VERSION 5.8 ;
BUSBITCHARS "[]" ;
DIVIDERCHAR "/" ;

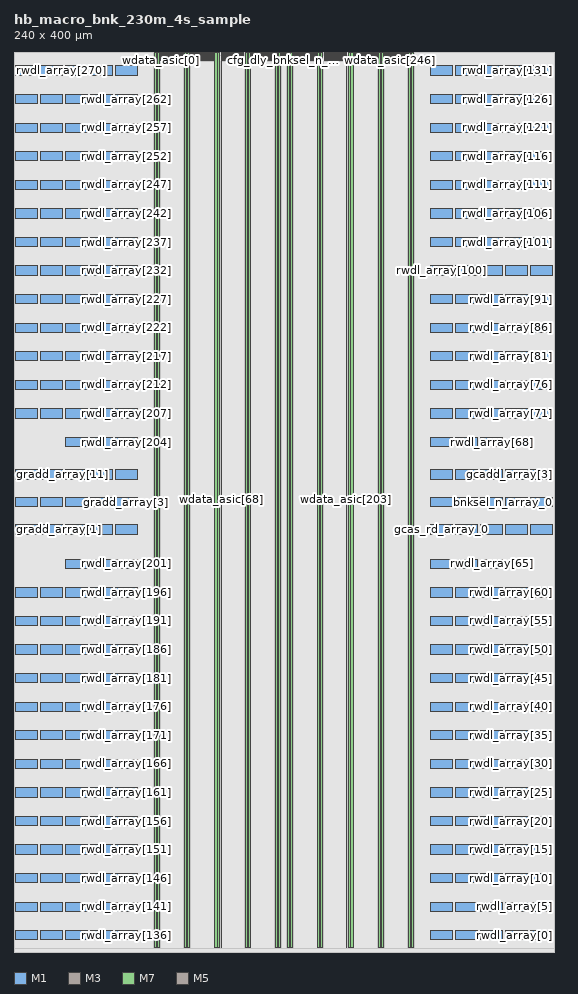
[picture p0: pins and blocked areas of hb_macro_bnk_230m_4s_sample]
MACRO hb_macro_bnk_230m_4s_sample
  CLASS RING ;
  ORIGIN 0 0 ;
  FOREIGN hb_macro_bnk_230m_4s_sample 0 0 ;
  SIZE 240 BY 400 ;
  SYMMETRY X Y R90 ;
  PIN bnksel_n_array_0
    DIRECTION OUTPUT ;
    USE SIGNAL ;
    PORT
      LAYER M1 ;
        RECT 218.53 197.94 228.21 202.06 ;
    END
  END bnksel_n_array_0
  PIN bnksel_n_array_1
    DIRECTION OUTPUT ;
    USE SIGNAL ;
    PORT
      LAYER M1 ;
        RECT 229.65 197.94 239.33 202.06 ;
    END
  END bnksel_n_array_1
  PIN gcadd_array[0]
    DIRECTION OUTPUT ;
    USE SIGNAL ;
    PORT
      LAYER M1 ;
        RECT 207.41 197.94 217.09 202.06 ;
    END
  END gcadd_array[0]
  PIN gcadd_array[1]
    DIRECTION OUTPUT ;
    USE SIGNAL ;
    PORT
      LAYER M1 ;
        RECT 196.29 197.94 205.97 202.06 ;
    END
  END gcadd_array[1]
  PIN gcadd_array[2]
    DIRECTION OUTPUT ;
    USE SIGNAL ;
    PORT
      LAYER M1 ;
        RECT 185.17 197.94 194.85 202.06 ;
    END
  END gcadd_array[2]
  PIN gcadd_array[3]
    DIRECTION OUTPUT ;
    USE SIGNAL ;
    PORT
      LAYER M1 ;
        RECT 229.65 210.22 239.33 214.34 ;
    END
  END gcadd_array[3]
  PIN gcadd_array[4]
    DIRECTION OUTPUT ;
    USE SIGNAL ;
    PORT
      LAYER M1 ;
        RECT 218.53 210.22 228.21 214.34 ;
    END
  END gcadd_array[4]
  PIN gcadd_array[5]
    DIRECTION OUTPUT ;
    USE SIGNAL ;
    PORT
      LAYER M1 ;
        RECT 207.41 210.22 217.09 214.34 ;
    END
  END gcadd_array[5]
  PIN gcadd_array[6]
    DIRECTION OUTPUT ;
    USE SIGNAL ;
    PORT
      LAYER M1 ;
        RECT 196.29 210.22 205.97 214.34 ;
    END
  END gcadd_array[6]
  PIN gcadd_array[7]
    DIRECTION OUTPUT ;
    USE SIGNAL ;
    PORT
      LAYER M1 ;
        RECT 185.17 210.22 194.85 214.34 ;
    END
  END gcadd_array[7]
  PIN gcas_rd_array_0
    DIRECTION OUTPUT ;
    USE SIGNAL ;
    PORT
      LAYER M1 ;
        RECT 185.17 185.66 194.85 189.78 ;
    END
  END gcas_rd_array_0
  PIN gcas_rd_array_1
    DIRECTION OUTPUT ;
    USE SIGNAL ;
    PORT
      LAYER M1 ;
        RECT 196.29 185.66 205.97 189.78 ;
    END
  END gcas_rd_array_1
  PIN gcas_wr_array_0
    DIRECTION OUTPUT ;
    USE SIGNAL ;
    PORT
      LAYER M1 ;
        RECT 207.41 185.66 217.09 189.78 ;
    END
  END gcas_wr_array_0
  PIN gcas_wr_array_1
    DIRECTION OUTPUT ;
    USE SIGNAL ;
    PORT
      LAYER M1 ;
        RECT 218.53 185.66 228.21 189.78 ;
    END
  END gcas_wr_array_1
  PIN gradd_array[0]
    DIRECTION OUTPUT ;
    USE SIGNAL ;
    PORT
      LAYER M1 ;
        RECT 22.91 185.66 32.59 189.78 ;
    END
  END gradd_array[0]
  PIN gradd_array[10]
    DIRECTION OUTPUT ;
    USE SIGNAL ;
    PORT
      LAYER M1 ;
        RECT 22.91 210.22 32.59 214.34 ;
    END
  END gradd_array[10]
  PIN gradd_array[11]
    DIRECTION OUTPUT ;
    USE SIGNAL ;
    PORT
      LAYER M1 ;
        RECT 11.79 210.22 21.47 214.34 ;
    END
  END gradd_array[11]
  PIN gradd_array[12]
    DIRECTION OUTPUT ;
    USE SIGNAL ;
    PORT
      LAYER M1 ;
        RECT 0.67 210.22 10.35 214.34 ;
    END
  END gradd_array[12]
  PIN gradd_array[1]
    DIRECTION OUTPUT ;
    USE SIGNAL ;
    PORT
      LAYER M1 ;
        RECT 11.79 185.66 21.47 189.78 ;
    END
  END gradd_array[1]
  PIN gradd_array[2]
    DIRECTION OUTPUT ;
    USE SIGNAL ;
    PORT
      LAYER M1 ;
        RECT 0.67 185.66 10.35 189.78 ;
    END
  END gradd_array[2]
  PIN gradd_array[3]
    DIRECTION OUTPUT ;
    USE SIGNAL ;
    PORT
      LAYER M1 ;
        RECT 45.15 197.94 54.83 202.06 ;
    END
  END gradd_array[3]
  PIN gradd_array[4]
    DIRECTION OUTPUT ;
    USE SIGNAL ;
    PORT
      LAYER M1 ;
        RECT 34.03 197.94 43.71 202.06 ;
    END
  END gradd_array[4]
  PIN gradd_array[5]
    DIRECTION OUTPUT ;
    USE SIGNAL ;
    PORT
      LAYER M1 ;
        RECT 22.91 197.94 32.59 202.06 ;
    END
  END gradd_array[5]
  PIN gradd_array[6]
    DIRECTION OUTPUT ;
    USE SIGNAL ;
    PORT
      LAYER M1 ;
        RECT 11.79 197.94 21.47 202.06 ;
    END
  END gradd_array[6]
  PIN gradd_array[7]
    DIRECTION OUTPUT ;
    USE SIGNAL ;
    PORT
      LAYER M1 ;
        RECT 0.67 197.94 10.35 202.06 ;
    END
  END gradd_array[7]
  PIN gradd_array[8]
    DIRECTION OUTPUT ;
    USE SIGNAL ;
    PORT
      LAYER M1 ;
        RECT 45.15 210.22 54.83 214.34 ;
    END
  END gradd_array[8]
  PIN gradd_array[9]
    DIRECTION OUTPUT ;
    USE SIGNAL ;
    PORT
      LAYER M1 ;
        RECT 34.03 210.22 43.71 214.34 ;
    END
  END gradd_array[9]
  PIN rdrdy_n_array_0
    DIRECTION INPUT ;
    USE SIGNAL ;
    PORT
      LAYER M1 ;
        RECT 34.03 185.66 43.71 189.78 ;
    END
  END rdrdy_n_array_0
  PIN rdrdy_n_array_1
    DIRECTION INPUT ;
    USE SIGNAL ;
    PORT
      LAYER M1 ;
        RECT 45.15 185.66 54.83 189.78 ;
    END
  END rdrdy_n_array_1
  PIN reset_n_array
    DIRECTION OUTPUT ;
    USE SIGNAL ;
    PORT
      LAYER M1 ;
        RECT 229.65 185.66 239.33 189.78 ;
    END
  END reset_n_array
  PIN rwdl_array[0]
    DIRECTION INOUT ;
    USE SIGNAL ;
    PORT
      LAYER M1 ;
        RECT 229.65 5.36 239.33 9.48 ;
    END
  END rwdl_array[0]
  PIN rwdl_array[100]
    DIRECTION INOUT ;
    USE SIGNAL ;
    PORT
      LAYER M1 ;
        RECT 185.17 300.785 194.85 304.905 ;
    END
  END rwdl_array[100]
  PIN rwdl_array[101]
    DIRECTION INOUT ;
    USE SIGNAL ;
    PORT
      LAYER M1 ;
        RECT 229.65 313.485 239.33 317.605 ;
    END
  END rwdl_array[101]
  PIN rwdl_array[102]
    DIRECTION INOUT ;
    USE SIGNAL ;
    PORT
      LAYER M1 ;
        RECT 218.53 313.485 228.21 317.605 ;
    END
  END rwdl_array[102]
  PIN rwdl_array[103]
    DIRECTION INOUT ;
    USE SIGNAL ;
    PORT
      LAYER M1 ;
        RECT 207.41 313.485 217.09 317.605 ;
    END
  END rwdl_array[103]
  PIN rwdl_array[104]
    DIRECTION INOUT ;
    USE SIGNAL ;
    PORT
      LAYER M1 ;
        RECT 196.29 313.485 205.97 317.605 ;
    END
  END rwdl_array[104]
  PIN rwdl_array[105]
    DIRECTION INOUT ;
    USE SIGNAL ;
    PORT
      LAYER M1 ;
        RECT 185.17 313.485 194.85 317.605 ;
    END
  END rwdl_array[105]
  PIN rwdl_array[106]
    DIRECTION INOUT ;
    USE SIGNAL ;
    PORT
      LAYER M1 ;
        RECT 229.65 326.185 239.33 330.305 ;
    END
  END rwdl_array[106]
  PIN rwdl_array[107]
    DIRECTION INOUT ;
    USE SIGNAL ;
    PORT
      LAYER M1 ;
        RECT 218.53 326.185 228.21 330.305 ;
    END
  END rwdl_array[107]
  PIN rwdl_array[108]
    DIRECTION INOUT ;
    USE SIGNAL ;
    PORT
      LAYER M1 ;
        RECT 207.41 326.185 217.09 330.305 ;
    END
  END rwdl_array[108]
  PIN rwdl_array[109]
    DIRECTION INOUT ;
    USE SIGNAL ;
    PORT
      LAYER M1 ;
        RECT 196.29 326.185 205.97 330.305 ;
    END
  END rwdl_array[109]
  PIN rwdl_array[10]
    DIRECTION INOUT ;
    USE SIGNAL ;
    PORT
      LAYER M1 ;
        RECT 229.65 30.76 239.33 34.88 ;
    END
  END rwdl_array[10]
  PIN rwdl_array[110]
    DIRECTION INOUT ;
    USE SIGNAL ;
    PORT
      LAYER M1 ;
        RECT 185.17 326.185 194.85 330.305 ;
    END
  END rwdl_array[110]
  PIN rwdl_array[111]
    DIRECTION INOUT ;
    USE SIGNAL ;
    PORT
      LAYER M1 ;
        RECT 229.65 338.885 239.33 343.005 ;
    END
  END rwdl_array[111]
  PIN rwdl_array[112]
    DIRECTION INOUT ;
    USE SIGNAL ;
    PORT
      LAYER M1 ;
        RECT 218.53 338.885 228.21 343.005 ;
    END
  END rwdl_array[112]
  PIN rwdl_array[113]
    DIRECTION INOUT ;
    USE SIGNAL ;
    PORT
      LAYER M1 ;
        RECT 207.41 338.885 217.09 343.005 ;
    END
  END rwdl_array[113]
  PIN rwdl_array[114]
    DIRECTION INOUT ;
    USE SIGNAL ;
    PORT
      LAYER M1 ;
        RECT 196.29 338.885 205.97 343.005 ;
    END
  END rwdl_array[114]
  PIN rwdl_array[115]
    DIRECTION INOUT ;
    USE SIGNAL ;
    PORT
      LAYER M1 ;
        RECT 185.17 338.885 194.85 343.005 ;
    END
  END rwdl_array[115]
  PIN rwdl_array[116]
    DIRECTION INOUT ;
    USE SIGNAL ;
    PORT
      LAYER M1 ;
        RECT 229.65 351.585 239.33 355.705 ;
    END
  END rwdl_array[116]
  PIN rwdl_array[117]
    DIRECTION INOUT ;
    USE SIGNAL ;
    PORT
      LAYER M1 ;
        RECT 218.53 351.585 228.21 355.705 ;
    END
  END rwdl_array[117]
  PIN rwdl_array[118]
    DIRECTION INOUT ;
    USE SIGNAL ;
    PORT
      LAYER M1 ;
        RECT 207.41 351.585 217.09 355.705 ;
    END
  END rwdl_array[118]
  PIN rwdl_array[119]
    DIRECTION INOUT ;
    USE SIGNAL ;
    PORT
      LAYER M1 ;
        RECT 196.29 351.585 205.97 355.705 ;
    END
  END rwdl_array[119]
  PIN rwdl_array[11]
    DIRECTION INOUT ;
    USE SIGNAL ;
    PORT
      LAYER M1 ;
        RECT 218.53 30.76 228.21 34.88 ;
    END
  END rwdl_array[11]
  PIN rwdl_array[120]
    DIRECTION INOUT ;
    USE SIGNAL ;
    PORT
      LAYER M1 ;
        RECT 185.17 351.585 194.85 355.705 ;
    END
  END rwdl_array[120]
  PIN rwdl_array[121]
    DIRECTION INOUT ;
    USE SIGNAL ;
    PORT
      LAYER M1 ;
        RECT 229.65 364.285 239.33 368.405 ;
    END
  END rwdl_array[121]
  PIN rwdl_array[122]
    DIRECTION INOUT ;
    USE SIGNAL ;
    PORT
      LAYER M1 ;
        RECT 218.53 364.285 228.21 368.405 ;
    END
  END rwdl_array[122]
  PIN rwdl_array[123]
    DIRECTION INOUT ;
    USE SIGNAL ;
    PORT
      LAYER M1 ;
        RECT 207.41 364.285 217.09 368.405 ;
    END
  END rwdl_array[123]
  PIN rwdl_array[124]
    DIRECTION INOUT ;
    USE SIGNAL ;
    PORT
      LAYER M1 ;
        RECT 196.29 364.285 205.97 368.405 ;
    END
  END rwdl_array[124]
  PIN rwdl_array[125]
    DIRECTION INOUT ;
    USE SIGNAL ;
    PORT
      LAYER M1 ;
        RECT 185.17 364.285 194.85 368.405 ;
    END
  END rwdl_array[125]
  PIN rwdl_array[126]
    DIRECTION INOUT ;
    USE SIGNAL ;
    PORT
      LAYER M1 ;
        RECT 229.65 376.985 239.33 381.105 ;
    END
  END rwdl_array[126]
  PIN rwdl_array[127]
    DIRECTION INOUT ;
    USE SIGNAL ;
    PORT
      LAYER M1 ;
        RECT 218.53 376.985 228.21 381.105 ;
    END
  END rwdl_array[127]
  PIN rwdl_array[128]
    DIRECTION INOUT ;
    USE SIGNAL ;
    PORT
      LAYER M1 ;
        RECT 207.41 376.985 217.09 381.105 ;
    END
  END rwdl_array[128]
  PIN rwdl_array[129]
    DIRECTION INOUT ;
    USE SIGNAL ;
    PORT
      LAYER M1 ;
        RECT 196.29 376.985 205.97 381.105 ;
    END
  END rwdl_array[129]
  PIN rwdl_array[12]
    DIRECTION INOUT ;
    USE SIGNAL ;
    PORT
      LAYER M1 ;
        RECT 207.41 30.76 217.09 34.88 ;
    END
  END rwdl_array[12]
  PIN rwdl_array[130]
    DIRECTION INOUT ;
    USE SIGNAL ;
    PORT
      LAYER M1 ;
        RECT 185.17 376.985 194.85 381.105 ;
    END
  END rwdl_array[130]
  PIN rwdl_array[131]
    DIRECTION INOUT ;
    USE SIGNAL ;
    PORT
      LAYER M1 ;
        RECT 229.65 389.685 239.33 393.805 ;
    END
  END rwdl_array[131]
  PIN rwdl_array[132]
    DIRECTION INOUT ;
    USE SIGNAL ;
    PORT
      LAYER M1 ;
        RECT 218.53 389.685 228.21 393.805 ;
    END
  END rwdl_array[132]
  PIN rwdl_array[133]
    DIRECTION INOUT ;
    USE SIGNAL ;
    PORT
      LAYER M1 ;
        RECT 207.41 389.685 217.09 393.805 ;
    END
  END rwdl_array[133]
  PIN rwdl_array[134]
    DIRECTION INOUT ;
    USE SIGNAL ;
    PORT
      LAYER M1 ;
        RECT 196.29 389.685 205.97 393.805 ;
    END
  END rwdl_array[134]
  PIN rwdl_array[135]
    DIRECTION INOUT ;
    USE SIGNAL ;
    PORT
      LAYER M1 ;
        RECT 185.17 389.685 194.85 393.805 ;
    END
  END rwdl_array[135]
  PIN rwdl_array[136]
    DIRECTION INOUT ;
    USE SIGNAL ;
    PORT
      LAYER M1 ;
        RECT 45.15 5.36 54.83 9.48 ;
    END
  END rwdl_array[136]
  PIN rwdl_array[137]
    DIRECTION INOUT ;
    USE SIGNAL ;
    PORT
      LAYER M1 ;
        RECT 34.03 5.36 43.71 9.48 ;
    END
  END rwdl_array[137]
  PIN rwdl_array[138]
    DIRECTION INOUT ;
    USE SIGNAL ;
    PORT
      LAYER M1 ;
        RECT 22.91 5.36 32.59 9.48 ;
    END
  END rwdl_array[138]
  PIN rwdl_array[139]
    DIRECTION INOUT ;
    USE SIGNAL ;
    PORT
      LAYER M1 ;
        RECT 11.79 5.36 21.47 9.48 ;
    END
  END rwdl_array[139]
  PIN rwdl_array[13]
    DIRECTION INOUT ;
    USE SIGNAL ;
    PORT
      LAYER M1 ;
        RECT 196.29 30.76 205.97 34.88 ;
    END
  END rwdl_array[13]
  PIN rwdl_array[140]
    DIRECTION INOUT ;
    USE SIGNAL ;
    PORT
      LAYER M1 ;
        RECT 0.67 5.36 10.35 9.48 ;
    END
  END rwdl_array[140]
  PIN rwdl_array[141]
    DIRECTION INOUT ;
    USE SIGNAL ;
    PORT
      LAYER M1 ;
        RECT 45.15 18.06 54.83 22.18 ;
    END
  END rwdl_array[141]
  PIN rwdl_array[142]
    DIRECTION INOUT ;
    USE SIGNAL ;
    PORT
      LAYER M1 ;
        RECT 34.03 18.06 43.71 22.18 ;
    END
  END rwdl_array[142]
  PIN rwdl_array[143]
    DIRECTION INOUT ;
    USE SIGNAL ;
    PORT
      LAYER M1 ;
        RECT 22.91 18.06 32.59 22.18 ;
    END
  END rwdl_array[143]
  PIN rwdl_array[144]
    DIRECTION INOUT ;
    USE SIGNAL ;
    PORT
      LAYER M1 ;
        RECT 11.79 18.06 21.47 22.18 ;
    END
  END rwdl_array[144]
  PIN rwdl_array[145]
    DIRECTION INOUT ;
    USE SIGNAL ;
    PORT
      LAYER M1 ;
        RECT 0.67 18.06 10.35 22.18 ;
    END
  END rwdl_array[145]
  PIN rwdl_array[146]
    DIRECTION INOUT ;
    USE SIGNAL ;
    PORT
      LAYER M1 ;
        RECT 45.15 30.76 54.83 34.88 ;
    END
  END rwdl_array[146]
  PIN rwdl_array[147]
    DIRECTION INOUT ;
    USE SIGNAL ;
    PORT
      LAYER M1 ;
        RECT 34.03 30.76 43.71 34.88 ;
    END
  END rwdl_array[147]
  PIN rwdl_array[148]
    DIRECTION INOUT ;
    USE SIGNAL ;
    PORT
      LAYER M1 ;
        RECT 22.91 30.76 32.59 34.88 ;
    END
  END rwdl_array[148]
  PIN rwdl_array[149]
    DIRECTION INOUT ;
    USE SIGNAL ;
    PORT
      LAYER M1 ;
        RECT 11.79 30.76 21.47 34.88 ;
    END
  END rwdl_array[149]
  PIN rwdl_array[14]
    DIRECTION INOUT ;
    USE SIGNAL ;
    PORT
      LAYER M1 ;
        RECT 185.17 30.76 194.85 34.88 ;
    END
  END rwdl_array[14]
  PIN rwdl_array[150]
    DIRECTION INOUT ;
    USE SIGNAL ;
    PORT
      LAYER M1 ;
        RECT 0.67 30.76 10.35 34.88 ;
    END
  END rwdl_array[150]
  PIN rwdl_array[151]
    DIRECTION INOUT ;
    USE SIGNAL ;
    PORT
      LAYER M1 ;
        RECT 45.15 43.46 54.83 47.58 ;
    END
  END rwdl_array[151]
  PIN rwdl_array[152]
    DIRECTION INOUT ;
    USE SIGNAL ;
    PORT
      LAYER M1 ;
        RECT 34.03 43.46 43.71 47.58 ;
    END
  END rwdl_array[152]
  PIN rwdl_array[153]
    DIRECTION INOUT ;
    USE SIGNAL ;
    PORT
      LAYER M1 ;
        RECT 22.91 43.46 32.59 47.58 ;
    END
  END rwdl_array[153]
  PIN rwdl_array[154]
    DIRECTION INOUT ;
    USE SIGNAL ;
    PORT
      LAYER M1 ;
        RECT 11.79 43.46 21.47 47.58 ;
    END
  END rwdl_array[154]
  PIN rwdl_array[155]
    DIRECTION INOUT ;
    USE SIGNAL ;
    PORT
      LAYER M1 ;
        RECT 0.67 43.46 10.35 47.58 ;
    END
  END rwdl_array[155]
  PIN rwdl_array[156]
    DIRECTION INOUT ;
    USE SIGNAL ;
    PORT
      LAYER M1 ;
        RECT 45.15 56.16 54.83 60.28 ;
    END
  END rwdl_array[156]
  PIN rwdl_array[157]
    DIRECTION INOUT ;
    USE SIGNAL ;
    PORT
      LAYER M1 ;
        RECT 34.03 56.16 43.71 60.28 ;
    END
  END rwdl_array[157]
  PIN rwdl_array[158]
    DIRECTION INOUT ;
    USE SIGNAL ;
    PORT
      LAYER M1 ;
        RECT 22.91 56.16 32.59 60.28 ;
    END
  END rwdl_array[158]
  PIN rwdl_array[159]
    DIRECTION INOUT ;
    USE SIGNAL ;
    PORT
      LAYER M1 ;
        RECT 11.79 56.16 21.47 60.28 ;
    END
  END rwdl_array[159]
  PIN rwdl_array[15]
    DIRECTION INOUT ;
    USE SIGNAL ;
    PORT
      LAYER M1 ;
        RECT 229.65 43.46 239.33 47.58 ;
    END
  END rwdl_array[15]
  PIN rwdl_array[160]
    DIRECTION INOUT ;
    USE SIGNAL ;
    PORT
      LAYER M1 ;
        RECT 0.67 56.16 10.35 60.28 ;
    END
  END rwdl_array[160]
  PIN rwdl_array[161]
    DIRECTION INOUT ;
    USE SIGNAL ;
    PORT
      LAYER M1 ;
        RECT 45.15 68.86 54.83 72.98 ;
    END
  END rwdl_array[161]
  PIN rwdl_array[162]
    DIRECTION INOUT ;
    USE SIGNAL ;
    PORT
      LAYER M1 ;
        RECT 34.03 68.86 43.71 72.98 ;
    END
  END rwdl_array[162]
  PIN rwdl_array[163]
    DIRECTION INOUT ;
    USE SIGNAL ;
    PORT
      LAYER M1 ;
        RECT 22.91 68.86 32.59 72.98 ;
    END
  END rwdl_array[163]
  PIN rwdl_array[164]
    DIRECTION INOUT ;
    USE SIGNAL ;
    PORT
      LAYER M1 ;
        RECT 11.79 68.86 21.47 72.98 ;
    END
  END rwdl_array[164]
  PIN rwdl_array[165]
    DIRECTION INOUT ;
    USE SIGNAL ;
    PORT
      LAYER M1 ;
        RECT 0.67 68.86 10.35 72.98 ;
    END
  END rwdl_array[165]
  PIN rwdl_array[166]
    DIRECTION INOUT ;
    USE SIGNAL ;
    PORT
      LAYER M1 ;
        RECT 45.15 81.56 54.83 85.68 ;
    END
  END rwdl_array[166]
  PIN rwdl_array[167]
    DIRECTION INOUT ;
    USE SIGNAL ;
    PORT
      LAYER M1 ;
        RECT 34.03 81.56 43.71 85.68 ;
    END
  END rwdl_array[167]
  PIN rwdl_array[168]
    DIRECTION INOUT ;
    USE SIGNAL ;
    PORT
      LAYER M1 ;
        RECT 22.91 81.56 32.59 85.68 ;
    END
  END rwdl_array[168]
  PIN rwdl_array[169]
    DIRECTION INOUT ;
    USE SIGNAL ;
    PORT
      LAYER M1 ;
        RECT 11.79 81.56 21.47 85.68 ;
    END
  END rwdl_array[169]
  PIN rwdl_array[16]
    DIRECTION INOUT ;
    USE SIGNAL ;
    PORT
      LAYER M1 ;
        RECT 218.53 43.46 228.21 47.58 ;
    END
  END rwdl_array[16]
  PIN rwdl_array[170]
    DIRECTION INOUT ;
    USE SIGNAL ;
    PORT
      LAYER M1 ;
        RECT 0.67 81.56 10.35 85.68 ;
    END
  END rwdl_array[170]
  PIN rwdl_array[171]
    DIRECTION INOUT ;
    USE SIGNAL ;
    PORT
      LAYER M1 ;
        RECT 45.15 94.26 54.83 98.38 ;
    END
  END rwdl_array[171]
  PIN rwdl_array[172]
    DIRECTION INOUT ;
    USE SIGNAL ;
    PORT
      LAYER M1 ;
        RECT 34.03 94.26 43.71 98.38 ;
    END
  END rwdl_array[172]
  PIN rwdl_array[173]
    DIRECTION INOUT ;
    USE SIGNAL ;
    PORT
      LAYER M1 ;
        RECT 22.91 94.26 32.59 98.38 ;
    END
  END rwdl_array[173]
  PIN rwdl_array[174]
    DIRECTION INOUT ;
    USE SIGNAL ;
    PORT
      LAYER M1 ;
        RECT 11.79 94.26 21.47 98.38 ;
    END
  END rwdl_array[174]
  PIN rwdl_array[175]
    DIRECTION INOUT ;
    USE SIGNAL ;
    PORT
      LAYER M1 ;
        RECT 0.67 94.26 10.35 98.38 ;
    END
  END rwdl_array[175]
  PIN rwdl_array[176]
    DIRECTION INOUT ;
    USE SIGNAL ;
    PORT
      LAYER M1 ;
        RECT 45.15 106.96 54.83 111.08 ;
    END
  END rwdl_array[176]
  PIN rwdl_array[177]
    DIRECTION INOUT ;
    USE SIGNAL ;
    PORT
      LAYER M1 ;
        RECT 34.03 106.96 43.71 111.08 ;
    END
  END rwdl_array[177]
  PIN rwdl_array[178]
    DIRECTION INOUT ;
    USE SIGNAL ;
    PORT
      LAYER M1 ;
        RECT 22.91 106.96 32.59 111.08 ;
    END
  END rwdl_array[178]
  PIN rwdl_array[179]
    DIRECTION INOUT ;
    USE SIGNAL ;
    PORT
      LAYER M1 ;
        RECT 11.79 106.96 21.47 111.08 ;
    END
  END rwdl_array[179]
  PIN rwdl_array[17]
    DIRECTION INOUT ;
    USE SIGNAL ;
    PORT
      LAYER M1 ;
        RECT 207.41 43.46 217.09 47.58 ;
    END
  END rwdl_array[17]
  PIN rwdl_array[180]
    DIRECTION INOUT ;
    USE SIGNAL ;
    PORT
      LAYER M1 ;
        RECT 0.67 106.96 10.35 111.08 ;
    END
  END rwdl_array[180]
  PIN rwdl_array[181]
    DIRECTION INOUT ;
    USE SIGNAL ;
    PORT
      LAYER M1 ;
        RECT 45.15 119.66 54.83 123.78 ;
    END
  END rwdl_array[181]
  PIN rwdl_array[182]
    DIRECTION INOUT ;
    USE SIGNAL ;
    PORT
      LAYER M1 ;
        RECT 34.03 119.66 43.71 123.78 ;
    END
  END rwdl_array[182]
  PIN rwdl_array[183]
    DIRECTION INOUT ;
    USE SIGNAL ;
    PORT
      LAYER M1 ;
        RECT 22.91 119.66 32.59 123.78 ;
    END
  END rwdl_array[183]
  PIN rwdl_array[184]
    DIRECTION INOUT ;
    USE SIGNAL ;
    PORT
      LAYER M1 ;
        RECT 11.79 119.66 21.47 123.78 ;
    END
  END rwdl_array[184]
  PIN rwdl_array[185]
    DIRECTION INOUT ;
    USE SIGNAL ;
    PORT
      LAYER M1 ;
        RECT 0.67 119.66 10.35 123.78 ;
    END
  END rwdl_array[185]
  PIN rwdl_array[186]
    DIRECTION INOUT ;
    USE SIGNAL ;
    PORT
      LAYER M1 ;
        RECT 45.15 132.36 54.83 136.48 ;
    END
  END rwdl_array[186]
  PIN rwdl_array[187]
    DIRECTION INOUT ;
    USE SIGNAL ;
    PORT
      LAYER M1 ;
        RECT 34.03 132.36 43.71 136.48 ;
    END
  END rwdl_array[187]
  PIN rwdl_array[188]
    DIRECTION INOUT ;
    USE SIGNAL ;
    PORT
      LAYER M1 ;
        RECT 22.91 132.36 32.59 136.48 ;
    END
  END rwdl_array[188]
  PIN rwdl_array[189]
    DIRECTION INOUT ;
    USE SIGNAL ;
    PORT
      LAYER M1 ;
        RECT 11.79 132.36 21.47 136.48 ;
    END
  END rwdl_array[189]
  PIN rwdl_array[18]
    DIRECTION INOUT ;
    USE SIGNAL ;
    PORT
      LAYER M1 ;
        RECT 196.29 43.46 205.97 47.58 ;
    END
  END rwdl_array[18]
  PIN rwdl_array[190]
    DIRECTION INOUT ;
    USE SIGNAL ;
    PORT
      LAYER M1 ;
        RECT 0.67 132.36 10.35 136.48 ;
    END
  END rwdl_array[190]
  PIN rwdl_array[191]
    DIRECTION INOUT ;
    USE SIGNAL ;
    PORT
      LAYER M1 ;
        RECT 45.15 145.06 54.83 149.18 ;
    END
  END rwdl_array[191]
  PIN rwdl_array[192]
    DIRECTION INOUT ;
    USE SIGNAL ;
    PORT
      LAYER M1 ;
        RECT 34.03 145.06 43.71 149.18 ;
    END
  END rwdl_array[192]
  PIN rwdl_array[193]
    DIRECTION INOUT ;
    USE SIGNAL ;
    PORT
      LAYER M1 ;
        RECT 22.91 145.06 32.59 149.18 ;
    END
  END rwdl_array[193]
  PIN rwdl_array[194]
    DIRECTION INOUT ;
    USE SIGNAL ;
    PORT
      LAYER M1 ;
        RECT 11.79 145.06 21.47 149.18 ;
    END
  END rwdl_array[194]
  PIN rwdl_array[195]
    DIRECTION INOUT ;
    USE SIGNAL ;
    PORT
      LAYER M1 ;
        RECT 0.67 145.06 10.35 149.18 ;
    END
  END rwdl_array[195]
  PIN rwdl_array[196]
    DIRECTION INOUT ;
    USE SIGNAL ;
    PORT
      LAYER M1 ;
        RECT 45.15 157.76 54.83 161.88 ;
    END
  END rwdl_array[196]
  PIN rwdl_array[197]
    DIRECTION INOUT ;
    USE SIGNAL ;
    PORT
      LAYER M1 ;
        RECT 34.03 157.76 43.71 161.88 ;
    END
  END rwdl_array[197]
  PIN rwdl_array[198]
    DIRECTION INOUT ;
    USE SIGNAL ;
    PORT
      LAYER M1 ;
        RECT 22.91 157.76 32.59 161.88 ;
    END
  END rwdl_array[198]
  PIN rwdl_array[199]
    DIRECTION INOUT ;
    USE SIGNAL ;
    PORT
      LAYER M1 ;
        RECT 11.79 157.76 21.47 161.88 ;
    END
  END rwdl_array[199]
  PIN rwdl_array[19]
    DIRECTION INOUT ;
    USE SIGNAL ;
    PORT
      LAYER M1 ;
        RECT 185.17 43.46 194.85 47.58 ;
    END
  END rwdl_array[19]
  PIN rwdl_array[1]
    DIRECTION INOUT ;
    USE SIGNAL ;
    PORT
      LAYER M1 ;
        RECT 218.53 5.36 228.21 9.48 ;
    END
  END rwdl_array[1]
  PIN rwdl_array[200]
    DIRECTION INOUT ;
    USE SIGNAL ;
    PORT
      LAYER M1 ;
        RECT 0.67 157.76 10.35 161.88 ;
    END
  END rwdl_array[200]
  PIN rwdl_array[201]
    DIRECTION INOUT ;
    USE SIGNAL ;
    PORT
      LAYER M1 ;
        RECT 45.15 170.46 54.83 174.58 ;
    END
  END rwdl_array[201]
  PIN rwdl_array[202]
    DIRECTION INOUT ;
    USE SIGNAL ;
    PORT
      LAYER M1 ;
        RECT 34.03 170.46 43.71 174.58 ;
    END
  END rwdl_array[202]
  PIN rwdl_array[203]
    DIRECTION INOUT ;
    USE SIGNAL ;
    PORT
      LAYER M1 ;
        RECT 22.91 170.46 32.59 174.58 ;
    END
  END rwdl_array[203]
  PIN rwdl_array[204]
    DIRECTION INOUT ;
    USE SIGNAL ;
    PORT
      LAYER M1 ;
        RECT 45.15 224.585 54.83 228.705 ;
    END
  END rwdl_array[204]
  PIN rwdl_array[205]
    DIRECTION INOUT ;
    USE SIGNAL ;
    PORT
      LAYER M1 ;
        RECT 34.03 224.585 43.71 228.705 ;
    END
  END rwdl_array[205]
  PIN rwdl_array[206]
    DIRECTION INOUT ;
    USE SIGNAL ;
    PORT
      LAYER M1 ;
        RECT 22.91 224.585 32.59 228.705 ;
    END
  END rwdl_array[206]
  PIN rwdl_array[207]
    DIRECTION INOUT ;
    USE SIGNAL ;
    PORT
      LAYER M1 ;
        RECT 45.15 237.285 54.83 241.405 ;
    END
  END rwdl_array[207]
  PIN rwdl_array[208]
    DIRECTION INOUT ;
    USE SIGNAL ;
    PORT
      LAYER M1 ;
        RECT 34.03 237.285 43.71 241.405 ;
    END
  END rwdl_array[208]
  PIN rwdl_array[209]
    DIRECTION INOUT ;
    USE SIGNAL ;
    PORT
      LAYER M1 ;
        RECT 22.91 237.285 32.59 241.405 ;
    END
  END rwdl_array[209]
  PIN rwdl_array[20]
    DIRECTION INOUT ;
    USE SIGNAL ;
    PORT
      LAYER M1 ;
        RECT 229.65 56.16 239.33 60.28 ;
    END
  END rwdl_array[20]
  PIN rwdl_array[210]
    DIRECTION INOUT ;
    USE SIGNAL ;
    PORT
      LAYER M1 ;
        RECT 11.79 237.285 21.47 241.405 ;
    END
  END rwdl_array[210]
  PIN rwdl_array[211]
    DIRECTION INOUT ;
    USE SIGNAL ;
    PORT
      LAYER M1 ;
        RECT 0.67 237.285 10.35 241.405 ;
    END
  END rwdl_array[211]
  PIN rwdl_array[212]
    DIRECTION INOUT ;
    USE SIGNAL ;
    PORT
      LAYER M1 ;
        RECT 45.15 249.985 54.83 254.105 ;
    END
  END rwdl_array[212]
  PIN rwdl_array[213]
    DIRECTION INOUT ;
    USE SIGNAL ;
    PORT
      LAYER M1 ;
        RECT 34.03 249.985 43.71 254.105 ;
    END
  END rwdl_array[213]
  PIN rwdl_array[214]
    DIRECTION INOUT ;
    USE SIGNAL ;
    PORT
      LAYER M1 ;
        RECT 22.91 249.985 32.59 254.105 ;
    END
  END rwdl_array[214]
  PIN rwdl_array[215]
    DIRECTION INOUT ;
    USE SIGNAL ;
    PORT
      LAYER M1 ;
        RECT 11.79 249.985 21.47 254.105 ;
    END
  END rwdl_array[215]
  PIN rwdl_array[216]
    DIRECTION INOUT ;
    USE SIGNAL ;
    PORT
      LAYER M1 ;
        RECT 0.67 249.985 10.35 254.105 ;
    END
  END rwdl_array[216]
  PIN rwdl_array[217]
    DIRECTION INOUT ;
    USE SIGNAL ;
    PORT
      LAYER M1 ;
        RECT 45.15 262.685 54.83 266.805 ;
    END
  END rwdl_array[217]
  PIN rwdl_array[218]
    DIRECTION INOUT ;
    USE SIGNAL ;
    PORT
      LAYER M1 ;
        RECT 34.03 262.685 43.71 266.805 ;
    END
  END rwdl_array[218]
  PIN rwdl_array[219]
    DIRECTION INOUT ;
    USE SIGNAL ;
    PORT
      LAYER M1 ;
        RECT 22.91 262.685 32.59 266.805 ;
    END
  END rwdl_array[219]
  PIN rwdl_array[21]
    DIRECTION INOUT ;
    USE SIGNAL ;
    PORT
      LAYER M1 ;
        RECT 218.53 56.16 228.21 60.28 ;
    END
  END rwdl_array[21]
  PIN rwdl_array[220]
    DIRECTION INOUT ;
    USE SIGNAL ;
    PORT
      LAYER M1 ;
        RECT 11.79 262.685 21.47 266.805 ;
    END
  END rwdl_array[220]
  PIN rwdl_array[221]
    DIRECTION INOUT ;
    USE SIGNAL ;
    PORT
      LAYER M1 ;
        RECT 0.67 262.685 10.35 266.805 ;
    END
  END rwdl_array[221]
  PIN rwdl_array[222]
    DIRECTION INOUT ;
    USE SIGNAL ;
    PORT
      LAYER M1 ;
        RECT 45.15 275.385 54.83 279.505 ;
    END
  END rwdl_array[222]
  PIN rwdl_array[223]
    DIRECTION INOUT ;
    USE SIGNAL ;
    PORT
      LAYER M1 ;
        RECT 34.03 275.385 43.71 279.505 ;
    END
  END rwdl_array[223]
  PIN rwdl_array[224]
    DIRECTION INOUT ;
    USE SIGNAL ;
    PORT
      LAYER M1 ;
        RECT 22.91 275.385 32.59 279.505 ;
    END
  END rwdl_array[224]
  PIN rwdl_array[225]
    DIRECTION INOUT ;
    USE SIGNAL ;
    PORT
      LAYER M1 ;
        RECT 11.79 275.385 21.47 279.505 ;
    END
  END rwdl_array[225]
  PIN rwdl_array[226]
    DIRECTION INOUT ;
    USE SIGNAL ;
    PORT
      LAYER M1 ;
        RECT 0.67 275.385 10.35 279.505 ;
    END
  END rwdl_array[226]
  PIN rwdl_array[227]
    DIRECTION INOUT ;
    USE SIGNAL ;
    PORT
      LAYER M1 ;
        RECT 45.15 288.085 54.83 292.205 ;
    END
  END rwdl_array[227]
  PIN rwdl_array[228]
    DIRECTION INOUT ;
    USE SIGNAL ;
    PORT
      LAYER M1 ;
        RECT 34.03 288.085 43.71 292.205 ;
    END
  END rwdl_array[228]
  PIN rwdl_array[229]
    DIRECTION INOUT ;
    USE SIGNAL ;
    PORT
      LAYER M1 ;
        RECT 22.91 288.085 32.59 292.205 ;
    END
  END rwdl_array[229]
  PIN rwdl_array[22]
    DIRECTION INOUT ;
    USE SIGNAL ;
    PORT
      LAYER M1 ;
        RECT 207.41 56.16 217.09 60.28 ;
    END
  END rwdl_array[22]
  PIN rwdl_array[230]
    DIRECTION INOUT ;
    USE SIGNAL ;
    PORT
      LAYER M1 ;
        RECT 11.79 288.085 21.47 292.205 ;
    END
  END rwdl_array[230]
  PIN rwdl_array[231]
    DIRECTION INOUT ;
    USE SIGNAL ;
    PORT
      LAYER M1 ;
        RECT 0.67 288.085 10.35 292.205 ;
    END
  END rwdl_array[231]
  PIN rwdl_array[232]
    DIRECTION INOUT ;
    USE SIGNAL ;
    PORT
      LAYER M1 ;
        RECT 45.15 300.785 54.83 304.905 ;
    END
  END rwdl_array[232]
  PIN rwdl_array[233]
    DIRECTION INOUT ;
    USE SIGNAL ;
    PORT
      LAYER M1 ;
        RECT 34.03 300.785 43.71 304.905 ;
    END
  END rwdl_array[233]
  PIN rwdl_array[234]
    DIRECTION INOUT ;
    USE SIGNAL ;
    PORT
      LAYER M1 ;
        RECT 22.91 300.785 32.59 304.905 ;
    END
  END rwdl_array[234]
  PIN rwdl_array[235]
    DIRECTION INOUT ;
    USE SIGNAL ;
    PORT
      LAYER M1 ;
        RECT 11.79 300.785 21.47 304.905 ;
    END
  END rwdl_array[235]
  PIN rwdl_array[236]
    DIRECTION INOUT ;
    USE SIGNAL ;
    PORT
      LAYER M1 ;
        RECT 0.67 300.785 10.35 304.905 ;
    END
  END rwdl_array[236]
  PIN rwdl_array[237]
    DIRECTION INOUT ;
    USE SIGNAL ;
    PORT
      LAYER M1 ;
        RECT 45.15 313.485 54.83 317.605 ;
    END
  END rwdl_array[237]
  PIN rwdl_array[238]
    DIRECTION INOUT ;
    USE SIGNAL ;
    PORT
      LAYER M1 ;
        RECT 34.03 313.485 43.71 317.605 ;
    END
  END rwdl_array[238]
  PIN rwdl_array[239]
    DIRECTION INOUT ;
    USE SIGNAL ;
    PORT
      LAYER M1 ;
        RECT 22.91 313.485 32.59 317.605 ;
    END
  END rwdl_array[239]
  PIN rwdl_array[23]
    DIRECTION INOUT ;
    USE SIGNAL ;
    PORT
      LAYER M1 ;
        RECT 196.29 56.16 205.97 60.28 ;
    END
  END rwdl_array[23]
  PIN rwdl_array[240]
    DIRECTION INOUT ;
    USE SIGNAL ;
    PORT
      LAYER M1 ;
        RECT 11.79 313.485 21.47 317.605 ;
    END
  END rwdl_array[240]
  PIN rwdl_array[241]
    DIRECTION INOUT ;
    USE SIGNAL ;
    PORT
      LAYER M1 ;
        RECT 0.67 313.485 10.35 317.605 ;
    END
  END rwdl_array[241]
  PIN rwdl_array[242]
    DIRECTION INOUT ;
    USE SIGNAL ;
    PORT
      LAYER M1 ;
        RECT 45.15 326.185 54.83 330.305 ;
    END
  END rwdl_array[242]
  PIN rwdl_array[243]
    DIRECTION INOUT ;
    USE SIGNAL ;
    PORT
      LAYER M1 ;
        RECT 34.03 326.185 43.71 330.305 ;
    END
  END rwdl_array[243]
  PIN rwdl_array[244]
    DIRECTION INOUT ;
    USE SIGNAL ;
    PORT
      LAYER M1 ;
        RECT 22.91 326.185 32.59 330.305 ;
    END
  END rwdl_array[244]
  PIN rwdl_array[245]
    DIRECTION INOUT ;
    USE SIGNAL ;
    PORT
      LAYER M1 ;
        RECT 11.79 326.185 21.47 330.305 ;
    END
  END rwdl_array[245]
  PIN rwdl_array[246]
    DIRECTION INOUT ;
    USE SIGNAL ;
    PORT
      LAYER M1 ;
        RECT 0.67 326.185 10.35 330.305 ;
    END
  END rwdl_array[246]
  PIN rwdl_array[247]
    DIRECTION INOUT ;
    USE SIGNAL ;
    PORT
      LAYER M1 ;
        RECT 45.15 338.885 54.83 343.005 ;
    END
  END rwdl_array[247]
  PIN rwdl_array[248]
    DIRECTION INOUT ;
    USE SIGNAL ;
    PORT
      LAYER M1 ;
        RECT 34.03 338.885 43.71 343.005 ;
    END
  END rwdl_array[248]
  PIN rwdl_array[249]
    DIRECTION INOUT ;
    USE SIGNAL ;
    PORT
      LAYER M1 ;
        RECT 22.91 338.885 32.59 343.005 ;
    END
  END rwdl_array[249]
  PIN rwdl_array[24]
    DIRECTION INOUT ;
    USE SIGNAL ;
    PORT
      LAYER M1 ;
        RECT 185.17 56.16 194.85 60.28 ;
    END
  END rwdl_array[24]
  PIN rwdl_array[250]
    DIRECTION INOUT ;
    USE SIGNAL ;
    PORT
      LAYER M1 ;
        RECT 11.79 338.885 21.47 343.005 ;
    END
  END rwdl_array[250]
  PIN rwdl_array[251]
    DIRECTION INOUT ;
    USE SIGNAL ;
    PORT
      LAYER M1 ;
        RECT 0.67 338.885 10.35 343.005 ;
    END
  END rwdl_array[251]
  PIN rwdl_array[252]
    DIRECTION INOUT ;
    USE SIGNAL ;
    PORT
      LAYER M1 ;
        RECT 45.15 351.585 54.83 355.705 ;
    END
  END rwdl_array[252]
  PIN rwdl_array[253]
    DIRECTION INOUT ;
    USE SIGNAL ;
    PORT
      LAYER M1 ;
        RECT 34.03 351.585 43.71 355.705 ;
    END
  END rwdl_array[253]
  PIN rwdl_array[254]
    DIRECTION INOUT ;
    USE SIGNAL ;
    PORT
      LAYER M1 ;
        RECT 22.91 351.585 32.59 355.705 ;
    END
  END rwdl_array[254]
  PIN rwdl_array[255]
    DIRECTION INOUT ;
    USE SIGNAL ;
    PORT
      LAYER M1 ;
        RECT 11.79 351.585 21.47 355.705 ;
    END
  END rwdl_array[255]
  PIN rwdl_array[256]
    DIRECTION INOUT ;
    USE SIGNAL ;
    PORT
      LAYER M1 ;
        RECT 0.67 351.585 10.35 355.705 ;
    END
  END rwdl_array[256]
  PIN rwdl_array[257]
    DIRECTION INOUT ;
    USE SIGNAL ;
    PORT
      LAYER M1 ;
        RECT 45.15 364.285 54.83 368.405 ;
    END
  END rwdl_array[257]
  PIN rwdl_array[258]
    DIRECTION INOUT ;
    USE SIGNAL ;
    PORT
      LAYER M1 ;
        RECT 34.03 364.285 43.71 368.405 ;
    END
  END rwdl_array[258]
  PIN rwdl_array[259]
    DIRECTION INOUT ;
    USE SIGNAL ;
    PORT
      LAYER M1 ;
        RECT 22.91 364.285 32.59 368.405 ;
    END
  END rwdl_array[259]
  PIN rwdl_array[25]
    DIRECTION INOUT ;
    USE SIGNAL ;
    PORT
      LAYER M1 ;
        RECT 229.65 68.86 239.33 72.98 ;
    END
  END rwdl_array[25]
  PIN rwdl_array[260]
    DIRECTION INOUT ;
    USE SIGNAL ;
    PORT
      LAYER M1 ;
        RECT 11.79 364.285 21.47 368.405 ;
    END
  END rwdl_array[260]
  PIN rwdl_array[261]
    DIRECTION INOUT ;
    USE SIGNAL ;
    PORT
      LAYER M1 ;
        RECT 0.67 364.285 10.35 368.405 ;
    END
  END rwdl_array[261]
  PIN rwdl_array[262]
    DIRECTION INOUT ;
    USE SIGNAL ;
    PORT
      LAYER M1 ;
        RECT 45.15 376.985 54.83 381.105 ;
    END
  END rwdl_array[262]
  PIN rwdl_array[263]
    DIRECTION INOUT ;
    USE SIGNAL ;
    PORT
      LAYER M1 ;
        RECT 34.03 376.985 43.71 381.105 ;
    END
  END rwdl_array[263]
  PIN rwdl_array[264]
    DIRECTION INOUT ;
    USE SIGNAL ;
    PORT
      LAYER M1 ;
        RECT 22.91 376.985 32.59 381.105 ;
    END
  END rwdl_array[264]
  PIN rwdl_array[265]
    DIRECTION INOUT ;
    USE SIGNAL ;
    PORT
      LAYER M1 ;
        RECT 11.79 376.985 21.47 381.105 ;
    END
  END rwdl_array[265]
  PIN rwdl_array[266]
    DIRECTION INOUT ;
    USE SIGNAL ;
    PORT
      LAYER M1 ;
        RECT 0.67 376.985 10.35 381.105 ;
    END
  END rwdl_array[266]
  PIN rwdl_array[267]
    DIRECTION INOUT ;
    USE SIGNAL ;
    PORT
      LAYER M1 ;
        RECT 45.15 389.685 54.83 393.805 ;
    END
  END rwdl_array[267]
  PIN rwdl_array[268]
    DIRECTION INOUT ;
    USE SIGNAL ;
    PORT
      LAYER M1 ;
        RECT 34.03 389.685 43.71 393.805 ;
    END
  END rwdl_array[268]
  PIN rwdl_array[269]
    DIRECTION INOUT ;
    USE SIGNAL ;
    PORT
      LAYER M1 ;
        RECT 22.91 389.685 32.59 393.805 ;
    END
  END rwdl_array[269]
  PIN rwdl_array[26]
    DIRECTION INOUT ;
    USE SIGNAL ;
    PORT
      LAYER M1 ;
        RECT 218.53 68.86 228.21 72.98 ;
    END
  END rwdl_array[26]
  PIN rwdl_array[270]
    DIRECTION INOUT ;
    USE SIGNAL ;
    PORT
      LAYER M1 ;
        RECT 11.79 389.685 21.47 393.805 ;
    END
  END rwdl_array[270]
  PIN rwdl_array[271]
    DIRECTION INOUT ;
    USE SIGNAL ;
    PORT
      LAYER M1 ;
        RECT 0.67 389.685 10.35 393.805 ;
    END
  END rwdl_array[271]
  PIN rwdl_array[27]
    DIRECTION INOUT ;
    USE SIGNAL ;
    PORT
      LAYER M1 ;
        RECT 207.41 68.86 217.09 72.98 ;
    END
  END rwdl_array[27]
  PIN rwdl_array[28]
    DIRECTION INOUT ;
    USE SIGNAL ;
    PORT
      LAYER M1 ;
        RECT 196.29 68.86 205.97 72.98 ;
    END
  END rwdl_array[28]
  PIN rwdl_array[29]
    DIRECTION INOUT ;
    USE SIGNAL ;
    PORT
      LAYER M1 ;
        RECT 185.17 68.86 194.85 72.98 ;
    END
  END rwdl_array[29]
  PIN rwdl_array[2]
    DIRECTION INOUT ;
    USE SIGNAL ;
    PORT
      LAYER M1 ;
        RECT 207.41 5.36 217.09 9.48 ;
    END
  END rwdl_array[2]
  PIN rwdl_array[30]
    DIRECTION INOUT ;
    USE SIGNAL ;
    PORT
      LAYER M1 ;
        RECT 229.65 81.56 239.33 85.68 ;
    END
  END rwdl_array[30]
  PIN rwdl_array[31]
    DIRECTION INOUT ;
    USE SIGNAL ;
    PORT
      LAYER M1 ;
        RECT 218.53 81.56 228.21 85.68 ;
    END
  END rwdl_array[31]
  PIN rwdl_array[32]
    DIRECTION INOUT ;
    USE SIGNAL ;
    PORT
      LAYER M1 ;
        RECT 207.41 81.56 217.09 85.68 ;
    END
  END rwdl_array[32]
  PIN rwdl_array[33]
    DIRECTION INOUT ;
    USE SIGNAL ;
    PORT
      LAYER M1 ;
        RECT 196.29 81.56 205.97 85.68 ;
    END
  END rwdl_array[33]
  PIN rwdl_array[34]
    DIRECTION INOUT ;
    USE SIGNAL ;
    PORT
      LAYER M1 ;
        RECT 185.17 81.56 194.85 85.68 ;
    END
  END rwdl_array[34]
  PIN rwdl_array[35]
    DIRECTION INOUT ;
    USE SIGNAL ;
    PORT
      LAYER M1 ;
        RECT 229.65 94.26 239.33 98.38 ;
    END
  END rwdl_array[35]
  PIN rwdl_array[36]
    DIRECTION INOUT ;
    USE SIGNAL ;
    PORT
      LAYER M1 ;
        RECT 218.53 94.26 228.21 98.38 ;
    END
  END rwdl_array[36]
  PIN rwdl_array[37]
    DIRECTION INOUT ;
    USE SIGNAL ;
    PORT
      LAYER M1 ;
        RECT 207.41 94.26 217.09 98.38 ;
    END
  END rwdl_array[37]
  PIN rwdl_array[38]
    DIRECTION INOUT ;
    USE SIGNAL ;
    PORT
      LAYER M1 ;
        RECT 196.29 94.26 205.97 98.38 ;
    END
  END rwdl_array[38]
  PIN rwdl_array[39]
    DIRECTION INOUT ;
    USE SIGNAL ;
    PORT
      LAYER M1 ;
        RECT 185.17 94.26 194.85 98.38 ;
    END
  END rwdl_array[39]
  PIN rwdl_array[3]
    DIRECTION INOUT ;
    USE SIGNAL ;
    PORT
      LAYER M1 ;
        RECT 196.29 5.36 205.97 9.48 ;
    END
  END rwdl_array[3]
  PIN rwdl_array[40]
    DIRECTION INOUT ;
    USE SIGNAL ;
    PORT
      LAYER M1 ;
        RECT 229.65 106.96 239.33 111.08 ;
    END
  END rwdl_array[40]
  PIN rwdl_array[41]
    DIRECTION INOUT ;
    USE SIGNAL ;
    PORT
      LAYER M1 ;
        RECT 218.53 106.96 228.21 111.08 ;
    END
  END rwdl_array[41]
  PIN rwdl_array[42]
    DIRECTION INOUT ;
    USE SIGNAL ;
    PORT
      LAYER M1 ;
        RECT 207.41 106.96 217.09 111.08 ;
    END
  END rwdl_array[42]
  PIN rwdl_array[43]
    DIRECTION INOUT ;
    USE SIGNAL ;
    PORT
      LAYER M1 ;
        RECT 196.29 106.96 205.97 111.08 ;
    END
  END rwdl_array[43]
  PIN rwdl_array[44]
    DIRECTION INOUT ;
    USE SIGNAL ;
    PORT
      LAYER M1 ;
        RECT 185.17 106.96 194.85 111.08 ;
    END
  END rwdl_array[44]
  PIN rwdl_array[45]
    DIRECTION INOUT ;
    USE SIGNAL ;
    PORT
      LAYER M1 ;
        RECT 229.65 119.66 239.33 123.78 ;
    END
  END rwdl_array[45]
  PIN rwdl_array[46]
    DIRECTION INOUT ;
    USE SIGNAL ;
    PORT
      LAYER M1 ;
        RECT 218.53 119.66 228.21 123.78 ;
    END
  END rwdl_array[46]
  PIN rwdl_array[47]
    DIRECTION INOUT ;
    USE SIGNAL ;
    PORT
      LAYER M1 ;
        RECT 207.41 119.66 217.09 123.78 ;
    END
  END rwdl_array[47]
  PIN rwdl_array[48]
    DIRECTION INOUT ;
    USE SIGNAL ;
    PORT
      LAYER M1 ;
        RECT 196.29 119.66 205.97 123.78 ;
    END
  END rwdl_array[48]
  PIN rwdl_array[49]
    DIRECTION INOUT ;
    USE SIGNAL ;
    PORT
      LAYER M1 ;
        RECT 185.17 119.66 194.85 123.78 ;
    END
  END rwdl_array[49]
  PIN rwdl_array[4]
    DIRECTION INOUT ;
    USE SIGNAL ;
    PORT
      LAYER M1 ;
        RECT 185.17 5.36 194.85 9.48 ;
    END
  END rwdl_array[4]
  PIN rwdl_array[50]
    DIRECTION INOUT ;
    USE SIGNAL ;
    PORT
      LAYER M1 ;
        RECT 229.65 132.36 239.33 136.48 ;
    END
  END rwdl_array[50]
  PIN rwdl_array[51]
    DIRECTION INOUT ;
    USE SIGNAL ;
    PORT
      LAYER M1 ;
        RECT 218.53 132.36 228.21 136.48 ;
    END
  END rwdl_array[51]
  PIN rwdl_array[52]
    DIRECTION INOUT ;
    USE SIGNAL ;
    PORT
      LAYER M1 ;
        RECT 207.41 132.36 217.09 136.48 ;
    END
  END rwdl_array[52]
  PIN rwdl_array[53]
    DIRECTION INOUT ;
    USE SIGNAL ;
    PORT
      LAYER M1 ;
        RECT 196.29 132.36 205.97 136.48 ;
    END
  END rwdl_array[53]
  PIN rwdl_array[54]
    DIRECTION INOUT ;
    USE SIGNAL ;
    PORT
      LAYER M1 ;
        RECT 185.17 132.36 194.85 136.48 ;
    END
  END rwdl_array[54]
  PIN rwdl_array[55]
    DIRECTION INOUT ;
    USE SIGNAL ;
    PORT
      LAYER M1 ;
        RECT 229.65 145.06 239.33 149.18 ;
    END
  END rwdl_array[55]
  PIN rwdl_array[56]
    DIRECTION INOUT ;
    USE SIGNAL ;
    PORT
      LAYER M1 ;
        RECT 218.53 145.06 228.21 149.18 ;
    END
  END rwdl_array[56]
  PIN rwdl_array[57]
    DIRECTION INOUT ;
    USE SIGNAL ;
    PORT
      LAYER M1 ;
        RECT 207.41 145.06 217.09 149.18 ;
    END
  END rwdl_array[57]
  PIN rwdl_array[58]
    DIRECTION INOUT ;
    USE SIGNAL ;
    PORT
      LAYER M1 ;
        RECT 196.29 145.06 205.97 149.18 ;
    END
  END rwdl_array[58]
  PIN rwdl_array[59]
    DIRECTION INOUT ;
    USE SIGNAL ;
    PORT
      LAYER M1 ;
        RECT 185.17 145.06 194.85 149.18 ;
    END
  END rwdl_array[59]
  PIN rwdl_array[5]
    DIRECTION INOUT ;
    USE SIGNAL ;
    PORT
      LAYER M1 ;
        RECT 229.65 18.06 239.33 22.18 ;
    END
  END rwdl_array[5]
  PIN rwdl_array[60]
    DIRECTION INOUT ;
    USE SIGNAL ;
    PORT
      LAYER M1 ;
        RECT 229.65 157.76 239.33 161.88 ;
    END
  END rwdl_array[60]
  PIN rwdl_array[61]
    DIRECTION INOUT ;
    USE SIGNAL ;
    PORT
      LAYER M1 ;
        RECT 218.53 157.76 228.21 161.88 ;
    END
  END rwdl_array[61]
  PIN rwdl_array[62]
    DIRECTION INOUT ;
    USE SIGNAL ;
    PORT
      LAYER M1 ;
        RECT 207.41 157.76 217.09 161.88 ;
    END
  END rwdl_array[62]
  PIN rwdl_array[63]
    DIRECTION INOUT ;
    USE SIGNAL ;
    PORT
      LAYER M1 ;
        RECT 196.29 157.76 205.97 161.88 ;
    END
  END rwdl_array[63]
  PIN rwdl_array[64]
    DIRECTION INOUT ;
    USE SIGNAL ;
    PORT
      LAYER M1 ;
        RECT 185.17 157.76 194.85 161.88 ;
    END
  END rwdl_array[64]
  PIN rwdl_array[65]
    DIRECTION INOUT ;
    USE SIGNAL ;
    PORT
      LAYER M1 ;
        RECT 207.41 170.46 217.09 174.58 ;
    END
  END rwdl_array[65]
  PIN rwdl_array[66]
    DIRECTION INOUT ;
    USE SIGNAL ;
    PORT
      LAYER M1 ;
        RECT 196.29 170.46 205.97 174.58 ;
    END
  END rwdl_array[66]
  PIN rwdl_array[67]
    DIRECTION INOUT ;
    USE SIGNAL ;
    PORT
      LAYER M1 ;
        RECT 185.17 170.46 194.85 174.58 ;
    END
  END rwdl_array[67]
  PIN rwdl_array[68]
    DIRECTION INOUT ;
    USE SIGNAL ;
    PORT
      LAYER M1 ;
        RECT 207.41 224.585 217.09 228.705 ;
    END
  END rwdl_array[68]
  PIN rwdl_array[69]
    DIRECTION INOUT ;
    USE SIGNAL ;
    PORT
      LAYER M1 ;
        RECT 196.29 224.585 205.97 228.705 ;
    END
  END rwdl_array[69]
  PIN rwdl_array[6]
    DIRECTION INOUT ;
    USE SIGNAL ;
    PORT
      LAYER M1 ;
        RECT 218.53 18.06 228.21 22.18 ;
    END
  END rwdl_array[6]
  PIN rwdl_array[70]
    DIRECTION INOUT ;
    USE SIGNAL ;
    PORT
      LAYER M1 ;
        RECT 185.17 224.585 194.85 228.705 ;
    END
  END rwdl_array[70]
  PIN rwdl_array[71]
    DIRECTION INOUT ;
    USE SIGNAL ;
    PORT
      LAYER M1 ;
        RECT 229.65 237.285 239.33 241.405 ;
    END
  END rwdl_array[71]
  PIN rwdl_array[72]
    DIRECTION INOUT ;
    USE SIGNAL ;
    PORT
      LAYER M1 ;
        RECT 218.53 237.285 228.21 241.405 ;
    END
  END rwdl_array[72]
  PIN rwdl_array[73]
    DIRECTION INOUT ;
    USE SIGNAL ;
    PORT
      LAYER M1 ;
        RECT 207.41 237.285 217.09 241.405 ;
    END
  END rwdl_array[73]
  PIN rwdl_array[74]
    DIRECTION INOUT ;
    USE SIGNAL ;
    PORT
      LAYER M1 ;
        RECT 196.29 237.285 205.97 241.405 ;
    END
  END rwdl_array[74]
  PIN rwdl_array[75]
    DIRECTION INOUT ;
    USE SIGNAL ;
    PORT
      LAYER M1 ;
        RECT 185.17 237.285 194.85 241.405 ;
    END
  END rwdl_array[75]
  PIN rwdl_array[76]
    DIRECTION INOUT ;
    USE SIGNAL ;
    PORT
      LAYER M1 ;
        RECT 229.65 249.985 239.33 254.105 ;
    END
  END rwdl_array[76]
  PIN rwdl_array[77]
    DIRECTION INOUT ;
    USE SIGNAL ;
    PORT
      LAYER M1 ;
        RECT 218.53 249.985 228.21 254.105 ;
    END
  END rwdl_array[77]
  PIN rwdl_array[78]
    DIRECTION INOUT ;
    USE SIGNAL ;
    PORT
      LAYER M1 ;
        RECT 207.41 249.985 217.09 254.105 ;
    END
  END rwdl_array[78]
  PIN rwdl_array[79]
    DIRECTION INOUT ;
    USE SIGNAL ;
    PORT
      LAYER M1 ;
        RECT 196.29 249.985 205.97 254.105 ;
    END
  END rwdl_array[79]
  PIN rwdl_array[7]
    DIRECTION INOUT ;
    USE SIGNAL ;
    PORT
      LAYER M1 ;
        RECT 207.41 18.06 217.09 22.18 ;
    END
  END rwdl_array[7]
  PIN rwdl_array[80]
    DIRECTION INOUT ;
    USE SIGNAL ;
    PORT
      LAYER M1 ;
        RECT 185.17 249.985 194.85 254.105 ;
    END
  END rwdl_array[80]
  PIN rwdl_array[81]
    DIRECTION INOUT ;
    USE SIGNAL ;
    PORT
      LAYER M1 ;
        RECT 229.65 262.685 239.33 266.805 ;
    END
  END rwdl_array[81]
  PIN rwdl_array[82]
    DIRECTION INOUT ;
    USE SIGNAL ;
    PORT
      LAYER M1 ;
        RECT 218.53 262.685 228.21 266.805 ;
    END
  END rwdl_array[82]
  PIN rwdl_array[83]
    DIRECTION INOUT ;
    USE SIGNAL ;
    PORT
      LAYER M1 ;
        RECT 207.41 262.685 217.09 266.805 ;
    END
  END rwdl_array[83]
  PIN rwdl_array[84]
    DIRECTION INOUT ;
    USE SIGNAL ;
    PORT
      LAYER M1 ;
        RECT 196.29 262.685 205.97 266.805 ;
    END
  END rwdl_array[84]
  PIN rwdl_array[85]
    DIRECTION INOUT ;
    USE SIGNAL ;
    PORT
      LAYER M1 ;
        RECT 185.17 262.685 194.85 266.805 ;
    END
  END rwdl_array[85]
  PIN rwdl_array[86]
    DIRECTION INOUT ;
    USE SIGNAL ;
    PORT
      LAYER M1 ;
        RECT 229.65 275.385 239.33 279.505 ;
    END
  END rwdl_array[86]
  PIN rwdl_array[87]
    DIRECTION INOUT ;
    USE SIGNAL ;
    PORT
      LAYER M1 ;
        RECT 218.53 275.385 228.21 279.505 ;
    END
  END rwdl_array[87]
  PIN rwdl_array[88]
    DIRECTION INOUT ;
    USE SIGNAL ;
    PORT
      LAYER M1 ;
        RECT 207.41 275.385 217.09 279.505 ;
    END
  END rwdl_array[88]
  PIN rwdl_array[89]
    DIRECTION INOUT ;
    USE SIGNAL ;
    PORT
      LAYER M1 ;
        RECT 196.29 275.385 205.97 279.505 ;
    END
  END rwdl_array[89]
  PIN rwdl_array[8]
    DIRECTION INOUT ;
    USE SIGNAL ;
    PORT
      LAYER M1 ;
        RECT 196.29 18.06 205.97 22.18 ;
    END
  END rwdl_array[8]
  PIN rwdl_array[90]
    DIRECTION INOUT ;
    USE SIGNAL ;
    PORT
      LAYER M1 ;
        RECT 185.17 275.385 194.85 279.505 ;
    END
  END rwdl_array[90]
  PIN rwdl_array[91]
    DIRECTION INOUT ;
    USE SIGNAL ;
    PORT
      LAYER M1 ;
        RECT 229.65 288.085 239.33 292.205 ;
    END
  END rwdl_array[91]
  PIN rwdl_array[92]
    DIRECTION INOUT ;
    USE SIGNAL ;
    PORT
      LAYER M1 ;
        RECT 218.53 288.085 228.21 292.205 ;
    END
  END rwdl_array[92]
  PIN rwdl_array[93]
    DIRECTION INOUT ;
    USE SIGNAL ;
    PORT
      LAYER M1 ;
        RECT 207.41 288.085 217.09 292.205 ;
    END
  END rwdl_array[93]
  PIN rwdl_array[94]
    DIRECTION INOUT ;
    USE SIGNAL ;
    PORT
      LAYER M1 ;
        RECT 196.29 288.085 205.97 292.205 ;
    END
  END rwdl_array[94]
  PIN rwdl_array[95]
    DIRECTION INOUT ;
    USE SIGNAL ;
    PORT
      LAYER M1 ;
        RECT 185.17 288.085 194.85 292.205 ;
    END
  END rwdl_array[95]
  PIN rwdl_array[96]
    DIRECTION INOUT ;
    USE SIGNAL ;
    PORT
      LAYER M1 ;
        RECT 229.65 300.785 239.33 304.905 ;
    END
  END rwdl_array[96]
  PIN rwdl_array[97]
    DIRECTION INOUT ;
    USE SIGNAL ;
    PORT
      LAYER M1 ;
        RECT 218.53 300.785 228.21 304.905 ;
    END
  END rwdl_array[97]
  PIN rwdl_array[98]
    DIRECTION INOUT ;
    USE SIGNAL ;
    PORT
      LAYER M1 ;
        RECT 207.41 300.785 217.09 304.905 ;
    END
  END rwdl_array[98]
  PIN rwdl_array[99]
    DIRECTION INOUT ;
    USE SIGNAL ;
    PORT
      LAYER M1 ;
        RECT 196.29 300.785 205.97 304.905 ;
    END
  END rwdl_array[99]
  PIN rwdl_array[9]
    DIRECTION INOUT ;
    USE SIGNAL ;
    PORT
      LAYER M1 ;
        RECT 185.17 18.06 194.85 22.18 ;
    END
  END rwdl_array[9]
  PIN bnksel_n_asic_0
    DIRECTION INPUT ;
    USE SIGNAL ;
    PORT
      LAYER M3 ;
        RECT 111.205 398.59 111.305 400 ;
    END
  END bnksel_n_asic_0
  PIN bnksel_n_asic_1
    DIRECTION INPUT ;
    USE SIGNAL ;
    PORT
      LAYER M3 ;
        RECT 111.505 398.59 111.605 400 ;
    END
  END bnksel_n_asic_1
  PIN cfg_dly_gcadd[0]
    DIRECTION INPUT ;
    USE SIGNAL ;
    PORT
      LAYER M3 ;
        RECT 114.205 398.59 114.305 400 ;
    END
  END cfg_dly_gcadd[0]
  PIN cfg_dly_gcadd[1]
    DIRECTION INPUT ;
    USE SIGNAL ;
    PORT
      LAYER M3 ;
        RECT 113.905 398.59 114.005 400 ;
    END
  END cfg_dly_gcadd[1]
  PIN cfg_dly_gcas_wr_0[0]
    DIRECTION INPUT ;
    USE SIGNAL ;
    PORT
      LAYER M3 ;
        RECT 115.405 398.59 115.505 400 ;
    END
  END cfg_dly_gcas_wr_0[0]
  PIN cfg_dly_gcas_wr_0[1]
    DIRECTION INPUT ;
    USE SIGNAL ;
    PORT
      LAYER M3 ;
        RECT 115.105 398.59 115.205 400 ;
    END
  END cfg_dly_gcas_wr_0[1]
  PIN cfg_dly_gcas_wr_1[0]
    DIRECTION INPUT ;
    USE SIGNAL ;
    PORT
      LAYER M3 ;
        RECT 114.805 398.59 114.905 400 ;
    END
  END cfg_dly_gcas_wr_1[0]
  PIN cfg_dly_gcas_wr_1[1]
    DIRECTION INPUT ;
    USE SIGNAL ;
    PORT
      LAYER M3 ;
        RECT 114.505 398.59 114.605 400 ;
    END
  END cfg_dly_gcas_wr_1[1]
  PIN clk_in_asic
    DIRECTION INPUT ;
    USE SIGNAL ;
    PORT
      LAYER M3 ;
        RECT 110.305 398.59 110.405 400 ;
    END
  END clk_in_asic
  PIN gcas_rd_en_asic_0
    DIRECTION INPUT ;
    USE SIGNAL ;
    PORT
      LAYER M3 ;
        RECT 111.805 398.59 111.905 400 ;
    END
  END gcas_rd_en_asic_0
  PIN gcas_rd_en_asic_1
    DIRECTION INPUT ;
    USE SIGNAL ;
    PORT
      LAYER M3 ;
        RECT 112.105 398.59 112.205 400 ;
    END
  END gcas_rd_en_asic_1
  PIN gcas_wr_en_asic_0
    DIRECTION INPUT ;
    USE SIGNAL ;
    PORT
      LAYER M3 ;
        RECT 112.405 398.59 112.505 400 ;
    END
  END gcas_wr_en_asic_0
  PIN gcas_wr_en_asic_1
    DIRECTION INPUT ;
    USE SIGNAL ;
    PORT
      LAYER M3 ;
        RECT 112.705 398.59 112.805 400 ;
    END
  END gcas_wr_en_asic_1
  PIN gradd_asic[0]
    DIRECTION INPUT ;
    USE SIGNAL ;
    PORT
      LAYER M3 ;
        RECT 109.705 398.59 109.805 400 ;
    END
  END gradd_asic[0]
  PIN gradd_asic[10]
    DIRECTION INPUT ;
    USE SIGNAL ;
    PORT
      LAYER M3 ;
        RECT 106.705 398.59 106.805 400 ;
    END
  END gradd_asic[10]
  PIN gradd_asic[11]
    DIRECTION INPUT ;
    USE SIGNAL ;
    PORT
      LAYER M3 ;
        RECT 106.405 398.59 106.505 400 ;
    END
  END gradd_asic[11]
  PIN gradd_asic[12]
    DIRECTION INPUT ;
    USE SIGNAL ;
    PORT
      LAYER M3 ;
        RECT 106.105 398.59 106.205 400 ;
    END
  END gradd_asic[12]
  PIN gradd_asic[1]
    DIRECTION INPUT ;
    USE SIGNAL ;
    PORT
      LAYER M3 ;
        RECT 109.405 398.59 109.505 400 ;
    END
  END gradd_asic[1]
  PIN gradd_asic[2]
    DIRECTION INPUT ;
    USE SIGNAL ;
    PORT
      LAYER M3 ;
        RECT 109.105 398.59 109.205 400 ;
    END
  END gradd_asic[2]
  PIN gradd_asic[3]
    DIRECTION INPUT ;
    USE SIGNAL ;
    PORT
      LAYER M3 ;
        RECT 108.805 398.59 108.905 400 ;
    END
  END gradd_asic[3]
  PIN gradd_asic[4]
    DIRECTION INPUT ;
    USE SIGNAL ;
    PORT
      LAYER M3 ;
        RECT 108.505 398.59 108.605 400 ;
    END
  END gradd_asic[4]
  PIN gradd_asic[5]
    DIRECTION INPUT ;
    USE SIGNAL ;
    PORT
      LAYER M3 ;
        RECT 108.205 398.59 108.305 400 ;
    END
  END gradd_asic[5]
  PIN gradd_asic[6]
    DIRECTION INPUT ;
    USE SIGNAL ;
    PORT
      LAYER M3 ;
        RECT 107.905 398.59 108.005 400 ;
    END
  END gradd_asic[6]
  PIN gradd_asic[7]
    DIRECTION INPUT ;
    USE SIGNAL ;
    PORT
      LAYER M3 ;
        RECT 107.605 398.59 107.705 400 ;
    END
  END gradd_asic[7]
  PIN gradd_asic[8]
    DIRECTION INPUT ;
    USE SIGNAL ;
    PORT
      LAYER M3 ;
        RECT 107.305 398.59 107.405 400 ;
    END
  END gradd_asic[8]
  PIN gradd_asic[9]
    DIRECTION INPUT ;
    USE SIGNAL ;
    PORT
      LAYER M3 ;
        RECT 107.005 398.59 107.105 400 ;
    END
  END gradd_asic[9]
  PIN ls_en_asic
    DIRECTION INPUT ;
    USE SIGNAL ;
    PORT
      LAYER M3 ;
        RECT 113.605 398.59 113.705 400 ;
    END
  END ls_en_asic
  PIN rdrdy_n_asic
    DIRECTION OUTPUT ;
    USE SIGNAL ;
    PORT
      LAYER M3 ;
        RECT 113.005 398.59 113.105 400 ;
    END
  END rdrdy_n_asic
  PIN reset_n_asic
    DIRECTION INPUT ;
    USE SIGNAL ;
    PORT
      LAYER M3 ;
        RECT 110.905 398.59 111.005 400 ;
    END
  END reset_n_asic
  PIN vss
    DIRECTION INOUT ;
    USE GROUND ;
    SHAPE RING ;
    PORT
      LAYER M7 ;
        RECT 62.355 1.98 63.355 400 ;
    END
    PORT
      LAYER M7 ;
        RECT 75.805 1.98 76.805 400 ;
    END
    PORT
      LAYER M7 ;
        RECT 89.255 1.98 90.255 400 ;
    END
    PORT
      LAYER M7 ;
        RECT 102.705 1.98 103.705 400 ;
    END
    PORT
      LAYER M7 ;
        RECT 116.155 1.98 117.155 400 ;
    END
    PORT
      LAYER M7 ;
        RECT 122.845 1.98 123.845 400 ;
    END
    PORT
      LAYER M7 ;
        RECT 136.295 1.98 137.295 400 ;
    END
    PORT
      LAYER M7 ;
        RECT 149.745 1.98 150.745 400 ;
    END
    PORT
      LAYER M7 ;
        RECT 163.195 1.98 164.195 400 ;
    END
    PORT
      LAYER M7 ;
        RECT 176.645 1.98 177.645 400 ;
    END
    PORT
      LAYER M3 ;
        RECT 110.005 398.59 110.105 400 ;
    END
    PORT
      LAYER M3 ;
        RECT 110.605 398.59 110.705 400 ;
    END
  END vss
  PIN wdata_oe_asic
    DIRECTION INPUT ;
    USE SIGNAL ;
    PORT
      LAYER M3 ;
        RECT 113.305 398.59 113.405 400 ;
    END
  END wdata_oe_asic
  PIN cfg_dly_bnksel_n_0[0]
    DIRECTION INPUT ;
    USE SIGNAL ;
    PORT
      LAYER M5 ;
        RECT 119.255 398.59 119.355 400 ;
    END
  END cfg_dly_bnksel_n_0[0]
  PIN cfg_dly_bnksel_n_0[1]
    DIRECTION INPUT ;
    USE SIGNAL ;
    PORT
      LAYER M5 ;
        RECT 118.955 398.59 119.055 400 ;
    END
  END cfg_dly_bnksel_n_0[1]
  PIN cfg_dly_bnksel_n_1[0]
    DIRECTION INPUT ;
    USE SIGNAL ;
    PORT
      LAYER M5 ;
        RECT 119.855 398.59 119.955 400 ;
    END
  END cfg_dly_bnksel_n_1[0]
  PIN cfg_dly_bnksel_n_1[1]
    DIRECTION INPUT ;
    USE SIGNAL ;
    PORT
      LAYER M5 ;
        RECT 119.555 398.59 119.655 400 ;
    END
  END cfg_dly_bnksel_n_1[1]
  PIN cfg_dly_gcas_rd_0[0]
    DIRECTION INPUT ;
    USE SIGNAL ;
    PORT
      LAYER M5 ;
        RECT 120.455 398.59 120.555 400 ;
    END
  END cfg_dly_gcas_rd_0[0]
  PIN cfg_dly_gcas_rd_0[1]
    DIRECTION INPUT ;
    USE SIGNAL ;
    PORT
      LAYER M5 ;
        RECT 120.155 398.59 120.255 400 ;
    END
  END cfg_dly_gcas_rd_0[1]
  PIN cfg_dly_gcas_rd_1[0]
    DIRECTION INPUT ;
    USE SIGNAL ;
    PORT
      LAYER M5 ;
        RECT 121.055 398.59 121.155 400 ;
    END
  END cfg_dly_gcas_rd_1[0]
  PIN cfg_dly_gcas_rd_1[1]
    DIRECTION INPUT ;
    USE SIGNAL ;
    PORT
      LAYER M5 ;
        RECT 120.755 398.59 120.855 400 ;
    END
  END cfg_dly_gcas_rd_1[1]
  PIN wdata_asic[0]
    DIRECTION INPUT ;
    USE SIGNAL ;
    PORT
      LAYER M5 ;
        RECT 65.305 398.59 65.405 400 ;
    END
  END wdata_asic[0]
  PIN wdata_asic[100]
    DIRECTION INPUT ;
    USE SIGNAL ;
    PORT
      LAYER M5 ;
        RECT 101.805 398.59 101.905 400 ;
    END
  END wdata_asic[100]
  PIN wdata_asic[101]
    DIRECTION INPUT ;
    USE SIGNAL ;
    PORT
      LAYER M5 ;
        RECT 102.105 398.59 102.205 400 ;
    END
  END wdata_asic[101]
  PIN wdata_asic[102]
    DIRECTION INPUT ;
    USE SIGNAL ;
    PORT
      LAYER M5 ;
        RECT 105.655 398.59 105.755 400 ;
    END
  END wdata_asic[102]
  PIN wdata_asic[103]
    DIRECTION INPUT ;
    USE SIGNAL ;
    PORT
      LAYER M5 ;
        RECT 105.955 398.59 106.055 400 ;
    END
  END wdata_asic[103]
  PIN wdata_asic[104]
    DIRECTION INPUT ;
    USE SIGNAL ;
    PORT
      LAYER M5 ;
        RECT 106.255 398.59 106.355 400 ;
    END
  END wdata_asic[104]
  PIN wdata_asic[105]
    DIRECTION INPUT ;
    USE SIGNAL ;
    PORT
      LAYER M5 ;
        RECT 106.555 398.59 106.655 400 ;
    END
  END wdata_asic[105]
  PIN wdata_asic[106]
    DIRECTION INPUT ;
    USE SIGNAL ;
    PORT
      LAYER M5 ;
        RECT 106.855 398.59 106.955 400 ;
    END
  END wdata_asic[106]
  PIN wdata_asic[107]
    DIRECTION INPUT ;
    USE SIGNAL ;
    PORT
      LAYER M5 ;
        RECT 107.155 398.59 107.255 400 ;
    END
  END wdata_asic[107]
  PIN wdata_asic[108]
    DIRECTION INPUT ;
    USE SIGNAL ;
    PORT
      LAYER M5 ;
        RECT 107.455 398.59 107.555 400 ;
    END
  END wdata_asic[108]
  PIN wdata_asic[109]
    DIRECTION INPUT ;
    USE SIGNAL ;
    PORT
      LAYER M5 ;
        RECT 107.755 398.59 107.855 400 ;
    END
  END wdata_asic[109]
  PIN wdata_asic[10]
    DIRECTION INPUT ;
    USE SIGNAL ;
    PORT
      LAYER M5 ;
        RECT 68.305 398.59 68.405 400 ;
    END
  END wdata_asic[10]
  PIN wdata_asic[110]
    DIRECTION INPUT ;
    USE SIGNAL ;
    PORT
      LAYER M5 ;
        RECT 108.055 398.59 108.155 400 ;
    END
  END wdata_asic[110]
  PIN wdata_asic[111]
    DIRECTION INPUT ;
    USE SIGNAL ;
    PORT
      LAYER M5 ;
        RECT 108.355 398.59 108.455 400 ;
    END
  END wdata_asic[111]
  PIN wdata_asic[112]
    DIRECTION INPUT ;
    USE SIGNAL ;
    PORT
      LAYER M5 ;
        RECT 108.655 398.59 108.755 400 ;
    END
  END wdata_asic[112]
  PIN wdata_asic[113]
    DIRECTION INPUT ;
    USE SIGNAL ;
    PORT
      LAYER M5 ;
        RECT 108.955 398.59 109.055 400 ;
    END
  END wdata_asic[113]
  PIN wdata_asic[114]
    DIRECTION INPUT ;
    USE SIGNAL ;
    PORT
      LAYER M5 ;
        RECT 109.255 398.59 109.355 400 ;
    END
  END wdata_asic[114]
  PIN wdata_asic[115]
    DIRECTION INPUT ;
    USE SIGNAL ;
    PORT
      LAYER M5 ;
        RECT 109.555 398.59 109.655 400 ;
    END
  END wdata_asic[115]
  PIN wdata_asic[116]
    DIRECTION INPUT ;
    USE SIGNAL ;
    PORT
      LAYER M5 ;
        RECT 109.855 398.59 109.955 400 ;
    END
  END wdata_asic[116]
  PIN wdata_asic[117]
    DIRECTION INPUT ;
    USE SIGNAL ;
    PORT
      LAYER M5 ;
        RECT 110.155 398.59 110.255 400 ;
    END
  END wdata_asic[117]
  PIN wdata_asic[118]
    DIRECTION INPUT ;
    USE SIGNAL ;
    PORT
      LAYER M5 ;
        RECT 110.455 398.59 110.555 400 ;
    END
  END wdata_asic[118]
  PIN wdata_asic[119]
    DIRECTION INPUT ;
    USE SIGNAL ;
    PORT
      LAYER M5 ;
        RECT 110.755 398.59 110.855 400 ;
    END
  END wdata_asic[119]
  PIN wdata_asic[11]
    DIRECTION INPUT ;
    USE SIGNAL ;
    PORT
      LAYER M5 ;
        RECT 68.605 398.59 68.705 400 ;
    END
  END wdata_asic[11]
  PIN wdata_asic[120]
    DIRECTION INPUT ;
    USE SIGNAL ;
    PORT
      LAYER M5 ;
        RECT 111.055 398.59 111.155 400 ;
    END
  END wdata_asic[120]
  PIN wdata_asic[121]
    DIRECTION INPUT ;
    USE SIGNAL ;
    PORT
      LAYER M5 ;
        RECT 111.355 398.59 111.455 400 ;
    END
  END wdata_asic[121]
  PIN wdata_asic[122]
    DIRECTION INPUT ;
    USE SIGNAL ;
    PORT
      LAYER M5 ;
        RECT 111.655 398.59 111.755 400 ;
    END
  END wdata_asic[122]
  PIN wdata_asic[123]
    DIRECTION INPUT ;
    USE SIGNAL ;
    PORT
      LAYER M5 ;
        RECT 111.955 398.59 112.055 400 ;
    END
  END wdata_asic[123]
  PIN wdata_asic[124]
    DIRECTION INPUT ;
    USE SIGNAL ;
    PORT
      LAYER M5 ;
        RECT 112.255 398.59 112.355 400 ;
    END
  END wdata_asic[124]
  PIN wdata_asic[125]
    DIRECTION INPUT ;
    USE SIGNAL ;
    PORT
      LAYER M5 ;
        RECT 112.555 398.59 112.655 400 ;
    END
  END wdata_asic[125]
  PIN wdata_asic[126]
    DIRECTION INPUT ;
    USE SIGNAL ;
    PORT
      LAYER M5 ;
        RECT 112.855 398.59 112.955 400 ;
    END
  END wdata_asic[126]
  PIN wdata_asic[127]
    DIRECTION INPUT ;
    USE SIGNAL ;
    PORT
      LAYER M5 ;
        RECT 113.155 398.59 113.255 400 ;
    END
  END wdata_asic[127]
  PIN wdata_asic[128]
    DIRECTION INPUT ;
    USE SIGNAL ;
    PORT
      LAYER M5 ;
        RECT 113.455 398.59 113.555 400 ;
    END
  END wdata_asic[128]
  PIN wdata_asic[129]
    DIRECTION INPUT ;
    USE SIGNAL ;
    PORT
      LAYER M5 ;
        RECT 113.755 398.59 113.855 400 ;
    END
  END wdata_asic[129]
  PIN wdata_asic[12]
    DIRECTION INPUT ;
    USE SIGNAL ;
    PORT
      LAYER M5 ;
        RECT 68.905 398.59 69.005 400 ;
    END
  END wdata_asic[12]
  PIN wdata_asic[130]
    DIRECTION INPUT ;
    USE SIGNAL ;
    PORT
      LAYER M5 ;
        RECT 114.055 398.59 114.155 400 ;
    END
  END wdata_asic[130]
  PIN wdata_asic[131]
    DIRECTION INPUT ;
    USE SIGNAL ;
    PORT
      LAYER M5 ;
        RECT 114.355 398.59 114.455 400 ;
    END
  END wdata_asic[131]
  PIN wdata_asic[132]
    DIRECTION INPUT ;
    USE SIGNAL ;
    PORT
      LAYER M5 ;
        RECT 114.655 398.59 114.755 400 ;
    END
  END wdata_asic[132]
  PIN wdata_asic[133]
    DIRECTION INPUT ;
    USE SIGNAL ;
    PORT
      LAYER M5 ;
        RECT 114.955 398.59 115.055 400 ;
    END
  END wdata_asic[133]
  PIN wdata_asic[134]
    DIRECTION INPUT ;
    USE SIGNAL ;
    PORT
      LAYER M5 ;
        RECT 115.255 398.59 115.355 400 ;
    END
  END wdata_asic[134]
  PIN wdata_asic[135]
    DIRECTION INPUT ;
    USE SIGNAL ;
    PORT
      LAYER M5 ;
        RECT 115.555 398.59 115.655 400 ;
    END
  END wdata_asic[135]
  PIN wdata_asic[136]
    DIRECTION INPUT ;
    USE SIGNAL ;
    PORT
      LAYER M5 ;
        RECT 124.345 398.59 124.445 400 ;
    END
  END wdata_asic[136]
  PIN wdata_asic[137]
    DIRECTION INPUT ;
    USE SIGNAL ;
    PORT
      LAYER M5 ;
        RECT 124.645 398.59 124.745 400 ;
    END
  END wdata_asic[137]
  PIN wdata_asic[138]
    DIRECTION INPUT ;
    USE SIGNAL ;
    PORT
      LAYER M5 ;
        RECT 124.945 398.59 125.045 400 ;
    END
  END wdata_asic[138]
  PIN wdata_asic[139]
    DIRECTION INPUT ;
    USE SIGNAL ;
    PORT
      LAYER M5 ;
        RECT 125.245 398.59 125.345 400 ;
    END
  END wdata_asic[139]
  PIN wdata_asic[13]
    DIRECTION INPUT ;
    USE SIGNAL ;
    PORT
      LAYER M5 ;
        RECT 69.205 398.59 69.305 400 ;
    END
  END wdata_asic[13]
  PIN wdata_asic[140]
    DIRECTION INPUT ;
    USE SIGNAL ;
    PORT
      LAYER M5 ;
        RECT 125.545 398.59 125.645 400 ;
    END
  END wdata_asic[140]
  PIN wdata_asic[141]
    DIRECTION INPUT ;
    USE SIGNAL ;
    PORT
      LAYER M5 ;
        RECT 125.845 398.59 125.945 400 ;
    END
  END wdata_asic[141]
  PIN wdata_asic[142]
    DIRECTION INPUT ;
    USE SIGNAL ;
    PORT
      LAYER M5 ;
        RECT 126.145 398.59 126.245 400 ;
    END
  END wdata_asic[142]
  PIN wdata_asic[143]
    DIRECTION INPUT ;
    USE SIGNAL ;
    PORT
      LAYER M5 ;
        RECT 126.445 398.59 126.545 400 ;
    END
  END wdata_asic[143]
  PIN wdata_asic[144]
    DIRECTION INPUT ;
    USE SIGNAL ;
    PORT
      LAYER M5 ;
        RECT 126.745 398.59 126.845 400 ;
    END
  END wdata_asic[144]
  PIN wdata_asic[145]
    DIRECTION INPUT ;
    USE SIGNAL ;
    PORT
      LAYER M5 ;
        RECT 127.045 398.59 127.145 400 ;
    END
  END wdata_asic[145]
  PIN wdata_asic[146]
    DIRECTION INPUT ;
    USE SIGNAL ;
    PORT
      LAYER M5 ;
        RECT 127.345 398.59 127.445 400 ;
    END
  END wdata_asic[146]
  PIN wdata_asic[147]
    DIRECTION INPUT ;
    USE SIGNAL ;
    PORT
      LAYER M5 ;
        RECT 127.645 398.59 127.745 400 ;
    END
  END wdata_asic[147]
  PIN wdata_asic[148]
    DIRECTION INPUT ;
    USE SIGNAL ;
    PORT
      LAYER M5 ;
        RECT 127.945 398.59 128.045 400 ;
    END
  END wdata_asic[148]
  PIN wdata_asic[149]
    DIRECTION INPUT ;
    USE SIGNAL ;
    PORT
      LAYER M5 ;
        RECT 128.245 398.59 128.345 400 ;
    END
  END wdata_asic[149]
  PIN wdata_asic[14]
    DIRECTION INPUT ;
    USE SIGNAL ;
    PORT
      LAYER M5 ;
        RECT 69.505 398.59 69.605 400 ;
    END
  END wdata_asic[14]
  PIN wdata_asic[150]
    DIRECTION INPUT ;
    USE SIGNAL ;
    PORT
      LAYER M5 ;
        RECT 128.545 398.59 128.645 400 ;
    END
  END wdata_asic[150]
  PIN wdata_asic[151]
    DIRECTION INPUT ;
    USE SIGNAL ;
    PORT
      LAYER M5 ;
        RECT 128.845 398.59 128.945 400 ;
    END
  END wdata_asic[151]
  PIN wdata_asic[152]
    DIRECTION INPUT ;
    USE SIGNAL ;
    PORT
      LAYER M5 ;
        RECT 129.145 398.59 129.245 400 ;
    END
  END wdata_asic[152]
  PIN wdata_asic[153]
    DIRECTION INPUT ;
    USE SIGNAL ;
    PORT
      LAYER M5 ;
        RECT 129.445 398.59 129.545 400 ;
    END
  END wdata_asic[153]
  PIN wdata_asic[154]
    DIRECTION INPUT ;
    USE SIGNAL ;
    PORT
      LAYER M5 ;
        RECT 129.745 398.59 129.845 400 ;
    END
  END wdata_asic[154]
  PIN wdata_asic[155]
    DIRECTION INPUT ;
    USE SIGNAL ;
    PORT
      LAYER M5 ;
        RECT 130.045 398.59 130.145 400 ;
    END
  END wdata_asic[155]
  PIN wdata_asic[156]
    DIRECTION INPUT ;
    USE SIGNAL ;
    PORT
      LAYER M5 ;
        RECT 130.345 398.59 130.445 400 ;
    END
  END wdata_asic[156]
  PIN wdata_asic[157]
    DIRECTION INPUT ;
    USE SIGNAL ;
    PORT
      LAYER M5 ;
        RECT 130.645 398.59 130.745 400 ;
    END
  END wdata_asic[157]
  PIN wdata_asic[158]
    DIRECTION INPUT ;
    USE SIGNAL ;
    PORT
      LAYER M5 ;
        RECT 130.945 398.59 131.045 400 ;
    END
  END wdata_asic[158]
  PIN wdata_asic[159]
    DIRECTION INPUT ;
    USE SIGNAL ;
    PORT
      LAYER M5 ;
        RECT 131.245 398.59 131.345 400 ;
    END
  END wdata_asic[159]
  PIN wdata_asic[15]
    DIRECTION INPUT ;
    USE SIGNAL ;
    PORT
      LAYER M5 ;
        RECT 69.805 398.59 69.905 400 ;
    END
  END wdata_asic[15]
  PIN wdata_asic[160]
    DIRECTION INPUT ;
    USE SIGNAL ;
    PORT
      LAYER M5 ;
        RECT 131.545 398.59 131.645 400 ;
    END
  END wdata_asic[160]
  PIN wdata_asic[161]
    DIRECTION INPUT ;
    USE SIGNAL ;
    PORT
      LAYER M5 ;
        RECT 131.845 398.59 131.945 400 ;
    END
  END wdata_asic[161]
  PIN wdata_asic[162]
    DIRECTION INPUT ;
    USE SIGNAL ;
    PORT
      LAYER M5 ;
        RECT 132.145 398.59 132.245 400 ;
    END
  END wdata_asic[162]
  PIN wdata_asic[163]
    DIRECTION INPUT ;
    USE SIGNAL ;
    PORT
      LAYER M5 ;
        RECT 132.445 398.59 132.545 400 ;
    END
  END wdata_asic[163]
  PIN wdata_asic[164]
    DIRECTION INPUT ;
    USE SIGNAL ;
    PORT
      LAYER M5 ;
        RECT 132.745 398.59 132.845 400 ;
    END
  END wdata_asic[164]
  PIN wdata_asic[165]
    DIRECTION INPUT ;
    USE SIGNAL ;
    PORT
      LAYER M5 ;
        RECT 133.045 398.59 133.145 400 ;
    END
  END wdata_asic[165]
  PIN wdata_asic[166]
    DIRECTION INPUT ;
    USE SIGNAL ;
    PORT
      LAYER M5 ;
        RECT 133.345 398.59 133.445 400 ;
    END
  END wdata_asic[166]
  PIN wdata_asic[167]
    DIRECTION INPUT ;
    USE SIGNAL ;
    PORT
      LAYER M5 ;
        RECT 133.645 398.59 133.745 400 ;
    END
  END wdata_asic[167]
  PIN wdata_asic[168]
    DIRECTION INPUT ;
    USE SIGNAL ;
    PORT
      LAYER M5 ;
        RECT 133.945 398.59 134.045 400 ;
    END
  END wdata_asic[168]
  PIN wdata_asic[169]
    DIRECTION INPUT ;
    USE SIGNAL ;
    PORT
      LAYER M5 ;
        RECT 134.245 398.59 134.345 400 ;
    END
  END wdata_asic[169]
  PIN wdata_asic[16]
    DIRECTION INPUT ;
    USE SIGNAL ;
    PORT
      LAYER M5 ;
        RECT 70.105 398.59 70.205 400 ;
    END
  END wdata_asic[16]
  PIN wdata_asic[170]
    DIRECTION INPUT ;
    USE SIGNAL ;
    PORT
      LAYER M5 ;
        RECT 137.795 398.59 137.895 400 ;
    END
  END wdata_asic[170]
  PIN wdata_asic[171]
    DIRECTION INPUT ;
    USE SIGNAL ;
    PORT
      LAYER M5 ;
        RECT 138.095 398.59 138.195 400 ;
    END
  END wdata_asic[171]
  PIN wdata_asic[172]
    DIRECTION INPUT ;
    USE SIGNAL ;
    PORT
      LAYER M5 ;
        RECT 138.395 398.59 138.495 400 ;
    END
  END wdata_asic[172]
  PIN wdata_asic[173]
    DIRECTION INPUT ;
    USE SIGNAL ;
    PORT
      LAYER M5 ;
        RECT 138.695 398.59 138.795 400 ;
    END
  END wdata_asic[173]
  PIN wdata_asic[174]
    DIRECTION INPUT ;
    USE SIGNAL ;
    PORT
      LAYER M5 ;
        RECT 138.995 398.59 139.095 400 ;
    END
  END wdata_asic[174]
  PIN wdata_asic[175]
    DIRECTION INPUT ;
    USE SIGNAL ;
    PORT
      LAYER M5 ;
        RECT 139.295 398.59 139.395 400 ;
    END
  END wdata_asic[175]
  PIN wdata_asic[176]
    DIRECTION INPUT ;
    USE SIGNAL ;
    PORT
      LAYER M5 ;
        RECT 139.595 398.59 139.695 400 ;
    END
  END wdata_asic[176]
  PIN wdata_asic[177]
    DIRECTION INPUT ;
    USE SIGNAL ;
    PORT
      LAYER M5 ;
        RECT 139.895 398.59 139.995 400 ;
    END
  END wdata_asic[177]
  PIN wdata_asic[178]
    DIRECTION INPUT ;
    USE SIGNAL ;
    PORT
      LAYER M5 ;
        RECT 140.195 398.59 140.295 400 ;
    END
  END wdata_asic[178]
  PIN wdata_asic[179]
    DIRECTION INPUT ;
    USE SIGNAL ;
    PORT
      LAYER M5 ;
        RECT 140.495 398.59 140.595 400 ;
    END
  END wdata_asic[179]
  PIN wdata_asic[17]
    DIRECTION INPUT ;
    USE SIGNAL ;
    PORT
      LAYER M5 ;
        RECT 70.405 398.59 70.505 400 ;
    END
  END wdata_asic[17]
  PIN wdata_asic[180]
    DIRECTION INPUT ;
    USE SIGNAL ;
    PORT
      LAYER M5 ;
        RECT 140.795 398.59 140.895 400 ;
    END
  END wdata_asic[180]
  PIN wdata_asic[181]
    DIRECTION INPUT ;
    USE SIGNAL ;
    PORT
      LAYER M5 ;
        RECT 141.095 398.59 141.195 400 ;
    END
  END wdata_asic[181]
  PIN wdata_asic[182]
    DIRECTION INPUT ;
    USE SIGNAL ;
    PORT
      LAYER M5 ;
        RECT 141.395 398.59 141.495 400 ;
    END
  END wdata_asic[182]
  PIN wdata_asic[183]
    DIRECTION INPUT ;
    USE SIGNAL ;
    PORT
      LAYER M5 ;
        RECT 141.695 398.59 141.795 400 ;
    END
  END wdata_asic[183]
  PIN wdata_asic[184]
    DIRECTION INPUT ;
    USE SIGNAL ;
    PORT
      LAYER M5 ;
        RECT 141.995 398.59 142.095 400 ;
    END
  END wdata_asic[184]
  PIN wdata_asic[185]
    DIRECTION INPUT ;
    USE SIGNAL ;
    PORT
      LAYER M5 ;
        RECT 142.295 398.59 142.395 400 ;
    END
  END wdata_asic[185]
  PIN wdata_asic[186]
    DIRECTION INPUT ;
    USE SIGNAL ;
    PORT
      LAYER M5 ;
        RECT 142.595 398.59 142.695 400 ;
    END
  END wdata_asic[186]
  PIN wdata_asic[187]
    DIRECTION INPUT ;
    USE SIGNAL ;
    PORT
      LAYER M5 ;
        RECT 142.895 398.59 142.995 400 ;
    END
  END wdata_asic[187]
  PIN wdata_asic[188]
    DIRECTION INPUT ;
    USE SIGNAL ;
    PORT
      LAYER M5 ;
        RECT 143.195 398.59 143.295 400 ;
    END
  END wdata_asic[188]
  PIN wdata_asic[189]
    DIRECTION INPUT ;
    USE SIGNAL ;
    PORT
      LAYER M5 ;
        RECT 143.495 398.59 143.595 400 ;
    END
  END wdata_asic[189]
  PIN wdata_asic[18]
    DIRECTION INPUT ;
    USE SIGNAL ;
    PORT
      LAYER M5 ;
        RECT 70.705 398.59 70.805 400 ;
    END
  END wdata_asic[18]
  PIN wdata_asic[190]
    DIRECTION INPUT ;
    USE SIGNAL ;
    PORT
      LAYER M5 ;
        RECT 143.795 398.59 143.895 400 ;
    END
  END wdata_asic[190]
  PIN wdata_asic[191]
    DIRECTION INPUT ;
    USE SIGNAL ;
    PORT
      LAYER M5 ;
        RECT 144.095 398.59 144.195 400 ;
    END
  END wdata_asic[191]
  PIN wdata_asic[192]
    DIRECTION INPUT ;
    USE SIGNAL ;
    PORT
      LAYER M5 ;
        RECT 144.395 398.59 144.495 400 ;
    END
  END wdata_asic[192]
  PIN wdata_asic[193]
    DIRECTION INPUT ;
    USE SIGNAL ;
    PORT
      LAYER M5 ;
        RECT 144.695 398.59 144.795 400 ;
    END
  END wdata_asic[193]
  PIN wdata_asic[194]
    DIRECTION INPUT ;
    USE SIGNAL ;
    PORT
      LAYER M5 ;
        RECT 144.995 398.59 145.095 400 ;
    END
  END wdata_asic[194]
  PIN wdata_asic[195]
    DIRECTION INPUT ;
    USE SIGNAL ;
    PORT
      LAYER M5 ;
        RECT 145.295 398.59 145.395 400 ;
    END
  END wdata_asic[195]
  PIN wdata_asic[196]
    DIRECTION INPUT ;
    USE SIGNAL ;
    PORT
      LAYER M5 ;
        RECT 145.595 398.59 145.695 400 ;
    END
  END wdata_asic[196]
  PIN wdata_asic[197]
    DIRECTION INPUT ;
    USE SIGNAL ;
    PORT
      LAYER M5 ;
        RECT 145.895 398.59 145.995 400 ;
    END
  END wdata_asic[197]
  PIN wdata_asic[198]
    DIRECTION INPUT ;
    USE SIGNAL ;
    PORT
      LAYER M5 ;
        RECT 146.195 398.59 146.295 400 ;
    END
  END wdata_asic[198]
  PIN wdata_asic[199]
    DIRECTION INPUT ;
    USE SIGNAL ;
    PORT
      LAYER M5 ;
        RECT 146.495 398.59 146.595 400 ;
    END
  END wdata_asic[199]
  PIN wdata_asic[19]
    DIRECTION INPUT ;
    USE SIGNAL ;
    PORT
      LAYER M5 ;
        RECT 71.005 398.59 71.105 400 ;
    END
  END wdata_asic[19]
  PIN wdata_asic[1]
    DIRECTION INPUT ;
    USE SIGNAL ;
    PORT
      LAYER M5 ;
        RECT 65.605 398.59 65.705 400 ;
    END
  END wdata_asic[1]
  PIN wdata_asic[200]
    DIRECTION INPUT ;
    USE SIGNAL ;
    PORT
      LAYER M5 ;
        RECT 146.795 398.59 146.895 400 ;
    END
  END wdata_asic[200]
  PIN wdata_asic[201]
    DIRECTION INPUT ;
    USE SIGNAL ;
    PORT
      LAYER M5 ;
        RECT 147.095 398.59 147.195 400 ;
    END
  END wdata_asic[201]
  PIN wdata_asic[202]
    DIRECTION INPUT ;
    USE SIGNAL ;
    PORT
      LAYER M5 ;
        RECT 147.395 398.59 147.495 400 ;
    END
  END wdata_asic[202]
  PIN wdata_asic[203]
    DIRECTION INPUT ;
    USE SIGNAL ;
    PORT
      LAYER M5 ;
        RECT 147.695 2.015 147.795 400 ;
    END
  END wdata_asic[203]
  PIN wdata_asic[204]
    DIRECTION INPUT ;
    USE SIGNAL ;
    PORT
      LAYER M5 ;
        RECT 151.245 398.59 151.345 400 ;
    END
  END wdata_asic[204]
  PIN wdata_asic[205]
    DIRECTION INPUT ;
    USE SIGNAL ;
    PORT
      LAYER M5 ;
        RECT 151.545 398.59 151.645 400 ;
    END
  END wdata_asic[205]
  PIN wdata_asic[206]
    DIRECTION INPUT ;
    USE SIGNAL ;
    PORT
      LAYER M5 ;
        RECT 151.845 398.59 151.945 400 ;
    END
  END wdata_asic[206]
  PIN wdata_asic[207]
    DIRECTION INPUT ;
    USE SIGNAL ;
    PORT
      LAYER M5 ;
        RECT 152.145 398.59 152.245 400 ;
    END
  END wdata_asic[207]
  PIN wdata_asic[208]
    DIRECTION INPUT ;
    USE SIGNAL ;
    PORT
      LAYER M5 ;
        RECT 152.445 398.59 152.545 400 ;
    END
  END wdata_asic[208]
  PIN wdata_asic[209]
    DIRECTION INPUT ;
    USE SIGNAL ;
    PORT
      LAYER M5 ;
        RECT 152.745 398.59 152.845 400 ;
    END
  END wdata_asic[209]
  PIN wdata_asic[20]
    DIRECTION INPUT ;
    USE SIGNAL ;
    PORT
      LAYER M5 ;
        RECT 71.305 398.59 71.405 400 ;
    END
  END wdata_asic[20]
  PIN wdata_asic[210]
    DIRECTION INPUT ;
    USE SIGNAL ;
    PORT
      LAYER M5 ;
        RECT 153.045 398.59 153.145 400 ;
    END
  END wdata_asic[210]
  PIN wdata_asic[211]
    DIRECTION INPUT ;
    USE SIGNAL ;
    PORT
      LAYER M5 ;
        RECT 153.345 398.59 153.445 400 ;
    END
  END wdata_asic[211]
  PIN wdata_asic[212]
    DIRECTION INPUT ;
    USE SIGNAL ;
    PORT
      LAYER M5 ;
        RECT 153.645 398.59 153.745 400 ;
    END
  END wdata_asic[212]
  PIN wdata_asic[213]
    DIRECTION INPUT ;
    USE SIGNAL ;
    PORT
      LAYER M5 ;
        RECT 153.945 398.59 154.045 400 ;
    END
  END wdata_asic[213]
  PIN wdata_asic[214]
    DIRECTION INPUT ;
    USE SIGNAL ;
    PORT
      LAYER M5 ;
        RECT 154.245 398.59 154.345 400 ;
    END
  END wdata_asic[214]
  PIN wdata_asic[215]
    DIRECTION INPUT ;
    USE SIGNAL ;
    PORT
      LAYER M5 ;
        RECT 154.545 398.59 154.645 400 ;
    END
  END wdata_asic[215]
  PIN wdata_asic[216]
    DIRECTION INPUT ;
    USE SIGNAL ;
    PORT
      LAYER M5 ;
        RECT 154.845 398.59 154.945 400 ;
    END
  END wdata_asic[216]
  PIN wdata_asic[217]
    DIRECTION INPUT ;
    USE SIGNAL ;
    PORT
      LAYER M5 ;
        RECT 155.145 398.59 155.245 400 ;
    END
  END wdata_asic[217]
  PIN wdata_asic[218]
    DIRECTION INPUT ;
    USE SIGNAL ;
    PORT
      LAYER M5 ;
        RECT 155.445 398.59 155.545 400 ;
    END
  END wdata_asic[218]
  PIN wdata_asic[219]
    DIRECTION INPUT ;
    USE SIGNAL ;
    PORT
      LAYER M5 ;
        RECT 155.745 398.59 155.845 400 ;
    END
  END wdata_asic[219]
  PIN wdata_asic[21]
    DIRECTION INPUT ;
    USE SIGNAL ;
    PORT
      LAYER M5 ;
        RECT 71.605 398.59 71.705 400 ;
    END
  END wdata_asic[21]
  PIN wdata_asic[220]
    DIRECTION INPUT ;
    USE SIGNAL ;
    PORT
      LAYER M5 ;
        RECT 156.045 398.59 156.145 400 ;
    END
  END wdata_asic[220]
  PIN wdata_asic[221]
    DIRECTION INPUT ;
    USE SIGNAL ;
    PORT
      LAYER M5 ;
        RECT 156.345 398.59 156.445 400 ;
    END
  END wdata_asic[221]
  PIN wdata_asic[222]
    DIRECTION INPUT ;
    USE SIGNAL ;
    PORT
      LAYER M5 ;
        RECT 156.645 398.59 156.745 400 ;
    END
  END wdata_asic[222]
  PIN wdata_asic[223]
    DIRECTION INPUT ;
    USE SIGNAL ;
    PORT
      LAYER M5 ;
        RECT 156.945 398.59 157.045 400 ;
    END
  END wdata_asic[223]
  PIN wdata_asic[224]
    DIRECTION INPUT ;
    USE SIGNAL ;
    PORT
      LAYER M5 ;
        RECT 157.245 398.59 157.345 400 ;
    END
  END wdata_asic[224]
  PIN wdata_asic[225]
    DIRECTION INPUT ;
    USE SIGNAL ;
    PORT
      LAYER M5 ;
        RECT 157.545 398.59 157.645 400 ;
    END
  END wdata_asic[225]
  PIN wdata_asic[226]
    DIRECTION INPUT ;
    USE SIGNAL ;
    PORT
      LAYER M5 ;
        RECT 157.845 398.59 157.945 400 ;
    END
  END wdata_asic[226]
  PIN wdata_asic[227]
    DIRECTION INPUT ;
    USE SIGNAL ;
    PORT
      LAYER M5 ;
        RECT 158.145 398.59 158.245 400 ;
    END
  END wdata_asic[227]
  PIN wdata_asic[228]
    DIRECTION INPUT ;
    USE SIGNAL ;
    PORT
      LAYER M5 ;
        RECT 158.445 398.59 158.545 400 ;
    END
  END wdata_asic[228]
  PIN wdata_asic[229]
    DIRECTION INPUT ;
    USE SIGNAL ;
    PORT
      LAYER M5 ;
        RECT 158.745 398.59 158.845 400 ;
    END
  END wdata_asic[229]
  PIN wdata_asic[22]
    DIRECTION INPUT ;
    USE SIGNAL ;
    PORT
      LAYER M5 ;
        RECT 71.905 398.59 72.005 400 ;
    END
  END wdata_asic[22]
  PIN wdata_asic[230]
    DIRECTION INPUT ;
    USE SIGNAL ;
    PORT
      LAYER M5 ;
        RECT 159.045 398.59 159.145 400 ;
    END
  END wdata_asic[230]
  PIN wdata_asic[231]
    DIRECTION INPUT ;
    USE SIGNAL ;
    PORT
      LAYER M5 ;
        RECT 159.345 398.59 159.445 400 ;
    END
  END wdata_asic[231]
  PIN wdata_asic[232]
    DIRECTION INPUT ;
    USE SIGNAL ;
    PORT
      LAYER M5 ;
        RECT 159.645 398.59 159.745 400 ;
    END
  END wdata_asic[232]
  PIN wdata_asic[233]
    DIRECTION INPUT ;
    USE SIGNAL ;
    PORT
      LAYER M5 ;
        RECT 159.945 398.59 160.045 400 ;
    END
  END wdata_asic[233]
  PIN wdata_asic[234]
    DIRECTION INPUT ;
    USE SIGNAL ;
    PORT
      LAYER M5 ;
        RECT 160.245 398.59 160.345 400 ;
    END
  END wdata_asic[234]
  PIN wdata_asic[235]
    DIRECTION INPUT ;
    USE SIGNAL ;
    PORT
      LAYER M5 ;
        RECT 160.545 398.59 160.645 400 ;
    END
  END wdata_asic[235]
  PIN wdata_asic[236]
    DIRECTION INPUT ;
    USE SIGNAL ;
    PORT
      LAYER M5 ;
        RECT 160.845 398.59 160.945 400 ;
    END
  END wdata_asic[236]
  PIN wdata_asic[237]
    DIRECTION INPUT ;
    USE SIGNAL ;
    PORT
      LAYER M5 ;
        RECT 161.145 398.59 161.245 400 ;
    END
  END wdata_asic[237]
  PIN wdata_asic[238]
    DIRECTION INPUT ;
    USE SIGNAL ;
    PORT
      LAYER M5 ;
        RECT 164.695 398.59 164.795 400 ;
    END
  END wdata_asic[238]
  PIN wdata_asic[239]
    DIRECTION INPUT ;
    USE SIGNAL ;
    PORT
      LAYER M5 ;
        RECT 164.995 398.59 165.095 400 ;
    END
  END wdata_asic[239]
  PIN wdata_asic[23]
    DIRECTION INPUT ;
    USE SIGNAL ;
    PORT
      LAYER M5 ;
        RECT 72.205 398.59 72.305 400 ;
    END
  END wdata_asic[23]
  PIN wdata_asic[240]
    DIRECTION INPUT ;
    USE SIGNAL ;
    PORT
      LAYER M5 ;
        RECT 165.295 398.59 165.395 400 ;
    END
  END wdata_asic[240]
  PIN wdata_asic[241]
    DIRECTION INPUT ;
    USE SIGNAL ;
    PORT
      LAYER M5 ;
        RECT 165.595 398.59 165.695 400 ;
    END
  END wdata_asic[241]
  PIN wdata_asic[242]
    DIRECTION INPUT ;
    USE SIGNAL ;
    PORT
      LAYER M5 ;
        RECT 165.895 398.59 165.995 400 ;
    END
  END wdata_asic[242]
  PIN wdata_asic[243]
    DIRECTION INPUT ;
    USE SIGNAL ;
    PORT
      LAYER M5 ;
        RECT 166.195 398.59 166.295 400 ;
    END
  END wdata_asic[243]
  PIN wdata_asic[244]
    DIRECTION INPUT ;
    USE SIGNAL ;
    PORT
      LAYER M5 ;
        RECT 166.495 398.59 166.595 400 ;
    END
  END wdata_asic[244]
  PIN wdata_asic[245]
    DIRECTION INPUT ;
    USE SIGNAL ;
    PORT
      LAYER M5 ;
        RECT 166.795 398.59 166.895 400 ;
    END
  END wdata_asic[245]
  PIN wdata_asic[246]
    DIRECTION INPUT ;
    USE SIGNAL ;
    PORT
      LAYER M5 ;
        RECT 167.095 398.59 167.195 400 ;
    END
  END wdata_asic[246]
  PIN wdata_asic[247]
    DIRECTION INPUT ;
    USE SIGNAL ;
    PORT
      LAYER M5 ;
        RECT 167.395 398.59 167.495 400 ;
    END
  END wdata_asic[247]
  PIN wdata_asic[248]
    DIRECTION INPUT ;
    USE SIGNAL ;
    PORT
      LAYER M5 ;
        RECT 167.695 398.59 167.795 400 ;
    END
  END wdata_asic[248]
  PIN wdata_asic[249]
    DIRECTION INPUT ;
    USE SIGNAL ;
    PORT
      LAYER M5 ;
        RECT 167.995 398.59 168.095 400 ;
    END
  END wdata_asic[249]
  PIN wdata_asic[24]
    DIRECTION INPUT ;
    USE SIGNAL ;
    PORT
      LAYER M5 ;
        RECT 72.505 398.59 72.605 400 ;
    END
  END wdata_asic[24]
  PIN wdata_asic[250]
    DIRECTION INPUT ;
    USE SIGNAL ;
    PORT
      LAYER M5 ;
        RECT 168.295 398.59 168.395 400 ;
    END
  END wdata_asic[250]
  PIN wdata_asic[251]
    DIRECTION INPUT ;
    USE SIGNAL ;
    PORT
      LAYER M5 ;
        RECT 168.595 398.59 168.695 400 ;
    END
  END wdata_asic[251]
  PIN wdata_asic[252]
    DIRECTION INPUT ;
    USE SIGNAL ;
    PORT
      LAYER M5 ;
        RECT 168.895 398.59 168.995 400 ;
    END
  END wdata_asic[252]
  PIN wdata_asic[253]
    DIRECTION INPUT ;
    USE SIGNAL ;
    PORT
      LAYER M5 ;
        RECT 169.195 398.59 169.295 400 ;
    END
  END wdata_asic[253]
  PIN wdata_asic[254]
    DIRECTION INPUT ;
    USE SIGNAL ;
    PORT
      LAYER M5 ;
        RECT 169.495 398.59 169.595 400 ;
    END
  END wdata_asic[254]
  PIN wdata_asic[255]
    DIRECTION INPUT ;
    USE SIGNAL ;
    PORT
      LAYER M5 ;
        RECT 169.795 398.59 169.895 400 ;
    END
  END wdata_asic[255]
  PIN wdata_asic[256]
    DIRECTION INPUT ;
    USE SIGNAL ;
    PORT
      LAYER M5 ;
        RECT 170.095 398.59 170.195 400 ;
    END
  END wdata_asic[256]
  PIN wdata_asic[257]
    DIRECTION INPUT ;
    USE SIGNAL ;
    PORT
      LAYER M5 ;
        RECT 170.395 398.59 170.495 400 ;
    END
  END wdata_asic[257]
  PIN wdata_asic[258]
    DIRECTION INPUT ;
    USE SIGNAL ;
    PORT
      LAYER M5 ;
        RECT 170.695 398.59 170.795 400 ;
    END
  END wdata_asic[258]
  PIN wdata_asic[259]
    DIRECTION INPUT ;
    USE SIGNAL ;
    PORT
      LAYER M5 ;
        RECT 170.995 398.59 171.095 400 ;
    END
  END wdata_asic[259]
  PIN wdata_asic[25]
    DIRECTION INPUT ;
    USE SIGNAL ;
    PORT
      LAYER M5 ;
        RECT 72.805 398.59 72.905 400 ;
    END
  END wdata_asic[25]
  PIN wdata_asic[260]
    DIRECTION INPUT ;
    USE SIGNAL ;
    PORT
      LAYER M5 ;
        RECT 171.295 398.59 171.395 400 ;
    END
  END wdata_asic[260]
  PIN wdata_asic[261]
    DIRECTION INPUT ;
    USE SIGNAL ;
    PORT
      LAYER M5 ;
        RECT 171.595 398.59 171.695 400 ;
    END
  END wdata_asic[261]
  PIN wdata_asic[262]
    DIRECTION INPUT ;
    USE SIGNAL ;
    PORT
      LAYER M5 ;
        RECT 171.895 398.59 171.995 400 ;
    END
  END wdata_asic[262]
  PIN wdata_asic[263]
    DIRECTION INPUT ;
    USE SIGNAL ;
    PORT
      LAYER M5 ;
        RECT 172.195 398.59 172.295 400 ;
    END
  END wdata_asic[263]
  PIN wdata_asic[264]
    DIRECTION INPUT ;
    USE SIGNAL ;
    PORT
      LAYER M5 ;
        RECT 172.495 398.59 172.595 400 ;
    END
  END wdata_asic[264]
  PIN wdata_asic[265]
    DIRECTION INPUT ;
    USE SIGNAL ;
    PORT
      LAYER M5 ;
        RECT 172.795 398.59 172.895 400 ;
    END
  END wdata_asic[265]
  PIN wdata_asic[266]
    DIRECTION INPUT ;
    USE SIGNAL ;
    PORT
      LAYER M5 ;
        RECT 173.095 398.59 173.195 400 ;
    END
  END wdata_asic[266]
  PIN wdata_asic[267]
    DIRECTION INPUT ;
    USE SIGNAL ;
    PORT
      LAYER M5 ;
        RECT 173.395 398.59 173.495 400 ;
    END
  END wdata_asic[267]
  PIN wdata_asic[268]
    DIRECTION INPUT ;
    USE SIGNAL ;
    PORT
      LAYER M5 ;
        RECT 173.695 398.59 173.795 400 ;
    END
  END wdata_asic[268]
  PIN wdata_asic[269]
    DIRECTION INPUT ;
    USE SIGNAL ;
    PORT
      LAYER M5 ;
        RECT 173.995 398.59 174.095 400 ;
    END
  END wdata_asic[269]
  PIN wdata_asic[26]
    DIRECTION INPUT ;
    USE SIGNAL ;
    PORT
      LAYER M5 ;
        RECT 73.105 398.59 73.205 400 ;
    END
  END wdata_asic[26]
  PIN wdata_asic[270]
    DIRECTION INPUT ;
    USE SIGNAL ;
    PORT
      LAYER M5 ;
        RECT 174.295 398.59 174.395 400 ;
    END
  END wdata_asic[270]
  PIN wdata_asic[271]
    DIRECTION INPUT ;
    USE SIGNAL ;
    PORT
      LAYER M5 ;
        RECT 174.595 398.59 174.695 400 ;
    END
  END wdata_asic[271]
  PIN wdata_asic[27]
    DIRECTION INPUT ;
    USE SIGNAL ;
    PORT
      LAYER M5 ;
        RECT 73.405 398.59 73.505 400 ;
    END
  END wdata_asic[27]
  PIN wdata_asic[28]
    DIRECTION INPUT ;
    USE SIGNAL ;
    PORT
      LAYER M5 ;
        RECT 73.705 398.59 73.805 400 ;
    END
  END wdata_asic[28]
  PIN wdata_asic[29]
    DIRECTION INPUT ;
    USE SIGNAL ;
    PORT
      LAYER M5 ;
        RECT 74.005 398.59 74.105 400 ;
    END
  END wdata_asic[29]
  PIN wdata_asic[2]
    DIRECTION INPUT ;
    USE SIGNAL ;
    PORT
      LAYER M5 ;
        RECT 65.905 398.59 66.005 400 ;
    END
  END wdata_asic[2]
  PIN wdata_asic[30]
    DIRECTION INPUT ;
    USE SIGNAL ;
    PORT
      LAYER M5 ;
        RECT 74.305 398.59 74.405 400 ;
    END
  END wdata_asic[30]
  PIN wdata_asic[31]
    DIRECTION INPUT ;
    USE SIGNAL ;
    PORT
      LAYER M5 ;
        RECT 74.605 398.59 74.705 400 ;
    END
  END wdata_asic[31]
  PIN wdata_asic[32]
    DIRECTION INPUT ;
    USE SIGNAL ;
    PORT
      LAYER M5 ;
        RECT 74.905 398.59 75.005 400 ;
    END
  END wdata_asic[32]
  PIN wdata_asic[33]
    DIRECTION INPUT ;
    USE SIGNAL ;
    PORT
      LAYER M5 ;
        RECT 75.205 398.59 75.305 400 ;
    END
  END wdata_asic[33]
  PIN wdata_asic[34]
    DIRECTION INPUT ;
    USE SIGNAL ;
    PORT
      LAYER M5 ;
        RECT 78.755 398.59 78.855 400 ;
    END
  END wdata_asic[34]
  PIN wdata_asic[35]
    DIRECTION INPUT ;
    USE SIGNAL ;
    PORT
      LAYER M5 ;
        RECT 79.055 398.59 79.155 400 ;
    END
  END wdata_asic[35]
  PIN wdata_asic[36]
    DIRECTION INPUT ;
    USE SIGNAL ;
    PORT
      LAYER M5 ;
        RECT 79.355 398.59 79.455 400 ;
    END
  END wdata_asic[36]
  PIN wdata_asic[37]
    DIRECTION INPUT ;
    USE SIGNAL ;
    PORT
      LAYER M5 ;
        RECT 79.655 398.59 79.755 400 ;
    END
  END wdata_asic[37]
  PIN wdata_asic[38]
    DIRECTION INPUT ;
    USE SIGNAL ;
    PORT
      LAYER M5 ;
        RECT 79.955 398.59 80.055 400 ;
    END
  END wdata_asic[38]
  PIN wdata_asic[39]
    DIRECTION INPUT ;
    USE SIGNAL ;
    PORT
      LAYER M5 ;
        RECT 80.255 398.59 80.355 400 ;
    END
  END wdata_asic[39]
  PIN wdata_asic[3]
    DIRECTION INPUT ;
    USE SIGNAL ;
    PORT
      LAYER M5 ;
        RECT 66.205 398.59 66.305 400 ;
    END
  END wdata_asic[3]
  PIN wdata_asic[40]
    DIRECTION INPUT ;
    USE SIGNAL ;
    PORT
      LAYER M5 ;
        RECT 80.555 398.59 80.655 400 ;
    END
  END wdata_asic[40]
  PIN wdata_asic[41]
    DIRECTION INPUT ;
    USE SIGNAL ;
    PORT
      LAYER M5 ;
        RECT 80.855 398.59 80.955 400 ;
    END
  END wdata_asic[41]
  PIN wdata_asic[42]
    DIRECTION INPUT ;
    USE SIGNAL ;
    PORT
      LAYER M5 ;
        RECT 81.155 398.59 81.255 400 ;
    END
  END wdata_asic[42]
  PIN wdata_asic[43]
    DIRECTION INPUT ;
    USE SIGNAL ;
    PORT
      LAYER M5 ;
        RECT 81.455 398.59 81.555 400 ;
    END
  END wdata_asic[43]
  PIN wdata_asic[44]
    DIRECTION INPUT ;
    USE SIGNAL ;
    PORT
      LAYER M5 ;
        RECT 81.755 398.59 81.855 400 ;
    END
  END wdata_asic[44]
  PIN wdata_asic[45]
    DIRECTION INPUT ;
    USE SIGNAL ;
    PORT
      LAYER M5 ;
        RECT 82.055 398.59 82.155 400 ;
    END
  END wdata_asic[45]
  PIN wdata_asic[46]
    DIRECTION INPUT ;
    USE SIGNAL ;
    PORT
      LAYER M5 ;
        RECT 82.355 398.59 82.455 400 ;
    END
  END wdata_asic[46]
  PIN wdata_asic[47]
    DIRECTION INPUT ;
    USE SIGNAL ;
    PORT
      LAYER M5 ;
        RECT 82.655 398.59 82.755 400 ;
    END
  END wdata_asic[47]
  PIN wdata_asic[48]
    DIRECTION INPUT ;
    USE SIGNAL ;
    PORT
      LAYER M5 ;
        RECT 82.955 398.59 83.055 400 ;
    END
  END wdata_asic[48]
  PIN wdata_asic[49]
    DIRECTION INPUT ;
    USE SIGNAL ;
    PORT
      LAYER M5 ;
        RECT 83.255 398.59 83.355 400 ;
    END
  END wdata_asic[49]
  PIN wdata_asic[4]
    DIRECTION INPUT ;
    USE SIGNAL ;
    PORT
      LAYER M5 ;
        RECT 66.505 398.59 66.605 400 ;
    END
  END wdata_asic[4]
  PIN wdata_asic[50]
    DIRECTION INPUT ;
    USE SIGNAL ;
    PORT
      LAYER M5 ;
        RECT 83.555 398.59 83.655 400 ;
    END
  END wdata_asic[50]
  PIN wdata_asic[51]
    DIRECTION INPUT ;
    USE SIGNAL ;
    PORT
      LAYER M5 ;
        RECT 83.855 398.59 83.955 400 ;
    END
  END wdata_asic[51]
  PIN wdata_asic[52]
    DIRECTION INPUT ;
    USE SIGNAL ;
    PORT
      LAYER M5 ;
        RECT 84.155 398.59 84.255 400 ;
    END
  END wdata_asic[52]
  PIN wdata_asic[53]
    DIRECTION INPUT ;
    USE SIGNAL ;
    PORT
      LAYER M5 ;
        RECT 84.455 398.59 84.555 400 ;
    END
  END wdata_asic[53]
  PIN wdata_asic[54]
    DIRECTION INPUT ;
    USE SIGNAL ;
    PORT
      LAYER M5 ;
        RECT 84.755 398.59 84.855 400 ;
    END
  END wdata_asic[54]
  PIN wdata_asic[55]
    DIRECTION INPUT ;
    USE SIGNAL ;
    PORT
      LAYER M5 ;
        RECT 85.055 398.59 85.155 400 ;
    END
  END wdata_asic[55]
  PIN wdata_asic[56]
    DIRECTION INPUT ;
    USE SIGNAL ;
    PORT
      LAYER M5 ;
        RECT 85.355 398.59 85.455 400 ;
    END
  END wdata_asic[56]
  PIN wdata_asic[57]
    DIRECTION INPUT ;
    USE SIGNAL ;
    PORT
      LAYER M5 ;
        RECT 85.655 398.59 85.755 400 ;
    END
  END wdata_asic[57]
  PIN wdata_asic[58]
    DIRECTION INPUT ;
    USE SIGNAL ;
    PORT
      LAYER M5 ;
        RECT 85.955 398.59 86.055 400 ;
    END
  END wdata_asic[58]
  PIN wdata_asic[59]
    DIRECTION INPUT ;
    USE SIGNAL ;
    PORT
      LAYER M5 ;
        RECT 86.255 398.59 86.355 400 ;
    END
  END wdata_asic[59]
  PIN wdata_asic[5]
    DIRECTION INPUT ;
    USE SIGNAL ;
    PORT
      LAYER M5 ;
        RECT 66.805 398.59 66.905 400 ;
    END
  END wdata_asic[5]
  PIN wdata_asic[60]
    DIRECTION INPUT ;
    USE SIGNAL ;
    PORT
      LAYER M5 ;
        RECT 86.555 398.59 86.655 400 ;
    END
  END wdata_asic[60]
  PIN wdata_asic[61]
    DIRECTION INPUT ;
    USE SIGNAL ;
    PORT
      LAYER M5 ;
        RECT 86.855 398.59 86.955 400 ;
    END
  END wdata_asic[61]
  PIN wdata_asic[62]
    DIRECTION INPUT ;
    USE SIGNAL ;
    PORT
      LAYER M5 ;
        RECT 87.155 398.59 87.255 400 ;
    END
  END wdata_asic[62]
  PIN wdata_asic[63]
    DIRECTION INPUT ;
    USE SIGNAL ;
    PORT
      LAYER M5 ;
        RECT 87.455 398.59 87.555 400 ;
    END
  END wdata_asic[63]
  PIN wdata_asic[64]
    DIRECTION INPUT ;
    USE SIGNAL ;
    PORT
      LAYER M5 ;
        RECT 87.755 398.59 87.855 400 ;
    END
  END wdata_asic[64]
  PIN wdata_asic[65]
    DIRECTION INPUT ;
    USE SIGNAL ;
    PORT
      LAYER M5 ;
        RECT 88.055 398.59 88.155 400 ;
    END
  END wdata_asic[65]
  PIN wdata_asic[66]
    DIRECTION INPUT ;
    USE SIGNAL ;
    PORT
      LAYER M5 ;
        RECT 88.355 398.59 88.455 400 ;
    END
  END wdata_asic[66]
  PIN wdata_asic[67]
    DIRECTION INPUT ;
    USE SIGNAL ;
    PORT
      LAYER M5 ;
        RECT 88.655 398.59 88.755 400 ;
    END
  END wdata_asic[67]
  PIN wdata_asic[68]
    DIRECTION INPUT ;
    USE SIGNAL ;
    PORT
      LAYER M5 ;
        RECT 92.205 2.015 92.305 400 ;
    END
  END wdata_asic[68]
  PIN wdata_asic[69]
    DIRECTION INPUT ;
    USE SIGNAL ;
    PORT
      LAYER M5 ;
        RECT 92.505 398.59 92.605 400 ;
    END
  END wdata_asic[69]
  PIN wdata_asic[6]
    DIRECTION INPUT ;
    USE SIGNAL ;
    PORT
      LAYER M5 ;
        RECT 67.105 398.59 67.205 400 ;
    END
  END wdata_asic[6]
  PIN wdata_asic[70]
    DIRECTION INPUT ;
    USE SIGNAL ;
    PORT
      LAYER M5 ;
        RECT 92.805 398.59 92.905 400 ;
    END
  END wdata_asic[70]
  PIN wdata_asic[71]
    DIRECTION INPUT ;
    USE SIGNAL ;
    PORT
      LAYER M5 ;
        RECT 93.105 398.59 93.205 400 ;
    END
  END wdata_asic[71]
  PIN wdata_asic[72]
    DIRECTION INPUT ;
    USE SIGNAL ;
    PORT
      LAYER M5 ;
        RECT 93.405 398.59 93.505 400 ;
    END
  END wdata_asic[72]
  PIN wdata_asic[73]
    DIRECTION INPUT ;
    USE SIGNAL ;
    PORT
      LAYER M5 ;
        RECT 93.705 398.59 93.805 400 ;
    END
  END wdata_asic[73]
  PIN wdata_asic[74]
    DIRECTION INPUT ;
    USE SIGNAL ;
    PORT
      LAYER M5 ;
        RECT 94.005 398.59 94.105 400 ;
    END
  END wdata_asic[74]
  PIN wdata_asic[75]
    DIRECTION INPUT ;
    USE SIGNAL ;
    PORT
      LAYER M5 ;
        RECT 94.305 398.59 94.405 400 ;
    END
  END wdata_asic[75]
  PIN wdata_asic[76]
    DIRECTION INPUT ;
    USE SIGNAL ;
    PORT
      LAYER M5 ;
        RECT 94.605 398.59 94.705 400 ;
    END
  END wdata_asic[76]
  PIN wdata_asic[77]
    DIRECTION INPUT ;
    USE SIGNAL ;
    PORT
      LAYER M5 ;
        RECT 94.905 398.59 95.005 400 ;
    END
  END wdata_asic[77]
  PIN wdata_asic[78]
    DIRECTION INPUT ;
    USE SIGNAL ;
    PORT
      LAYER M5 ;
        RECT 95.205 398.59 95.305 400 ;
    END
  END wdata_asic[78]
  PIN wdata_asic[79]
    DIRECTION INPUT ;
    USE SIGNAL ;
    PORT
      LAYER M5 ;
        RECT 95.505 398.59 95.605 400 ;
    END
  END wdata_asic[79]
  PIN wdata_asic[7]
    DIRECTION INPUT ;
    USE SIGNAL ;
    PORT
      LAYER M5 ;
        RECT 67.405 398.59 67.505 400 ;
    END
  END wdata_asic[7]
  PIN wdata_asic[80]
    DIRECTION INPUT ;
    USE SIGNAL ;
    PORT
      LAYER M5 ;
        RECT 95.805 398.59 95.905 400 ;
    END
  END wdata_asic[80]
  PIN wdata_asic[81]
    DIRECTION INPUT ;
    USE SIGNAL ;
    PORT
      LAYER M5 ;
        RECT 96.105 398.59 96.205 400 ;
    END
  END wdata_asic[81]
  PIN wdata_asic[82]
    DIRECTION INPUT ;
    USE SIGNAL ;
    PORT
      LAYER M5 ;
        RECT 96.405 398.59 96.505 400 ;
    END
  END wdata_asic[82]
  PIN wdata_asic[83]
    DIRECTION INPUT ;
    USE SIGNAL ;
    PORT
      LAYER M5 ;
        RECT 96.705 398.59 96.805 400 ;
    END
  END wdata_asic[83]
  PIN wdata_asic[84]
    DIRECTION INPUT ;
    USE SIGNAL ;
    PORT
      LAYER M5 ;
        RECT 97.005 398.59 97.105 400 ;
    END
  END wdata_asic[84]
  PIN wdata_asic[85]
    DIRECTION INPUT ;
    USE SIGNAL ;
    PORT
      LAYER M5 ;
        RECT 97.305 398.59 97.405 400 ;
    END
  END wdata_asic[85]
  PIN wdata_asic[86]
    DIRECTION INPUT ;
    USE SIGNAL ;
    PORT
      LAYER M5 ;
        RECT 97.605 398.59 97.705 400 ;
    END
  END wdata_asic[86]
  PIN wdata_asic[87]
    DIRECTION INPUT ;
    USE SIGNAL ;
    PORT
      LAYER M5 ;
        RECT 97.905 398.59 98.005 400 ;
    END
  END wdata_asic[87]
  PIN wdata_asic[88]
    DIRECTION INPUT ;
    USE SIGNAL ;
    PORT
      LAYER M5 ;
        RECT 98.205 398.59 98.305 400 ;
    END
  END wdata_asic[88]
  PIN wdata_asic[89]
    DIRECTION INPUT ;
    USE SIGNAL ;
    PORT
      LAYER M5 ;
        RECT 98.505 398.59 98.605 400 ;
    END
  END wdata_asic[89]
  PIN wdata_asic[8]
    DIRECTION INPUT ;
    USE SIGNAL ;
    PORT
      LAYER M5 ;
        RECT 67.705 398.59 67.805 400 ;
    END
  END wdata_asic[8]
  PIN wdata_asic[90]
    DIRECTION INPUT ;
    USE SIGNAL ;
    PORT
      LAYER M5 ;
        RECT 98.805 398.59 98.905 400 ;
    END
  END wdata_asic[90]
  PIN wdata_asic[91]
    DIRECTION INPUT ;
    USE SIGNAL ;
    PORT
      LAYER M5 ;
        RECT 99.105 398.59 99.205 400 ;
    END
  END wdata_asic[91]
  PIN wdata_asic[92]
    DIRECTION INPUT ;
    USE SIGNAL ;
    PORT
      LAYER M5 ;
        RECT 99.405 398.59 99.505 400 ;
    END
  END wdata_asic[92]
  PIN wdata_asic[93]
    DIRECTION INPUT ;
    USE SIGNAL ;
    PORT
      LAYER M5 ;
        RECT 99.705 398.59 99.805 400 ;
    END
  END wdata_asic[93]
  PIN wdata_asic[94]
    DIRECTION INPUT ;
    USE SIGNAL ;
    PORT
      LAYER M5 ;
        RECT 100.005 398.59 100.105 400 ;
    END
  END wdata_asic[94]
  PIN wdata_asic[95]
    DIRECTION INPUT ;
    USE SIGNAL ;
    PORT
      LAYER M5 ;
        RECT 100.305 398.59 100.405 400 ;
    END
  END wdata_asic[95]
  PIN wdata_asic[96]
    DIRECTION INPUT ;
    USE SIGNAL ;
    PORT
      LAYER M5 ;
        RECT 100.605 398.59 100.705 400 ;
    END
  END wdata_asic[96]
  PIN wdata_asic[97]
    DIRECTION INPUT ;
    USE SIGNAL ;
    PORT
      LAYER M5 ;
        RECT 100.905 398.59 101.005 400 ;
    END
  END wdata_asic[97]
  PIN wdata_asic[98]
    DIRECTION INPUT ;
    USE SIGNAL ;
    PORT
      LAYER M5 ;
        RECT 101.205 398.59 101.305 400 ;
    END
  END wdata_asic[98]
  PIN wdata_asic[99]
    DIRECTION INPUT ;
    USE SIGNAL ;
    PORT
      LAYER M5 ;
        RECT 101.505 398.59 101.605 400 ;
    END
  END wdata_asic[99]
  PIN wdata_asic[9]
    DIRECTION INPUT ;
    USE SIGNAL ;
    PORT
      LAYER M5 ;
        RECT 68.005 398.59 68.105 400 ;
    END
  END wdata_asic[9]
  PIN rdata_asic[0]
    DIRECTION OUTPUT ;
    USE SIGNAL ;
    PORT
      LAYER M7 ;
        RECT 65.155 396.265 65.255 400 ;
    END
  END rdata_asic[0]
  PIN rdata_asic[100]
    DIRECTION OUTPUT ;
    USE SIGNAL ;
    PORT
      LAYER M7 ;
        RECT 101.655 396.265 101.755 400 ;
    END
  END rdata_asic[100]
  PIN rdata_asic[101]
    DIRECTION OUTPUT ;
    USE SIGNAL ;
    PORT
      LAYER M7 ;
        RECT 101.955 396.265 102.055 400 ;
    END
  END rdata_asic[101]
  PIN rdata_asic[102]
    DIRECTION OUTPUT ;
    USE SIGNAL ;
    PORT
      LAYER M7 ;
        RECT 105.505 396.265 105.605 400 ;
    END
  END rdata_asic[102]
  PIN rdata_asic[103]
    DIRECTION OUTPUT ;
    USE SIGNAL ;
    PORT
      LAYER M7 ;
        RECT 105.805 396.265 105.905 400 ;
    END
  END rdata_asic[103]
  PIN rdata_asic[104]
    DIRECTION OUTPUT ;
    USE SIGNAL ;
    PORT
      LAYER M7 ;
        RECT 106.105 396.265 106.205 400 ;
    END
  END rdata_asic[104]
  PIN rdata_asic[105]
    DIRECTION OUTPUT ;
    USE SIGNAL ;
    PORT
      LAYER M7 ;
        RECT 106.405 396.265 106.505 400 ;
    END
  END rdata_asic[105]
  PIN rdata_asic[106]
    DIRECTION OUTPUT ;
    USE SIGNAL ;
    PORT
      LAYER M7 ;
        RECT 106.705 396.265 106.805 400 ;
    END
  END rdata_asic[106]
  PIN rdata_asic[107]
    DIRECTION OUTPUT ;
    USE SIGNAL ;
    PORT
      LAYER M7 ;
        RECT 107.005 396.265 107.105 400 ;
    END
  END rdata_asic[107]
  PIN rdata_asic[108]
    DIRECTION OUTPUT ;
    USE SIGNAL ;
    PORT
      LAYER M7 ;
        RECT 107.305 396.265 107.405 400 ;
    END
  END rdata_asic[108]
  PIN rdata_asic[109]
    DIRECTION OUTPUT ;
    USE SIGNAL ;
    PORT
      LAYER M7 ;
        RECT 107.605 396.265 107.705 400 ;
    END
  END rdata_asic[109]
  PIN rdata_asic[10]
    DIRECTION OUTPUT ;
    USE SIGNAL ;
    PORT
      LAYER M7 ;
        RECT 68.155 396.265 68.255 400 ;
    END
  END rdata_asic[10]
  PIN rdata_asic[110]
    DIRECTION OUTPUT ;
    USE SIGNAL ;
    PORT
      LAYER M7 ;
        RECT 107.905 396.265 108.005 400 ;
    END
  END rdata_asic[110]
  PIN rdata_asic[111]
    DIRECTION OUTPUT ;
    USE SIGNAL ;
    PORT
      LAYER M7 ;
        RECT 108.205 396.265 108.305 400 ;
    END
  END rdata_asic[111]
  PIN rdata_asic[112]
    DIRECTION OUTPUT ;
    USE SIGNAL ;
    PORT
      LAYER M7 ;
        RECT 108.505 396.265 108.605 400 ;
    END
  END rdata_asic[112]
  PIN rdata_asic[113]
    DIRECTION OUTPUT ;
    USE SIGNAL ;
    PORT
      LAYER M7 ;
        RECT 108.805 396.265 108.905 400 ;
    END
  END rdata_asic[113]
  PIN rdata_asic[114]
    DIRECTION OUTPUT ;
    USE SIGNAL ;
    PORT
      LAYER M7 ;
        RECT 109.105 396.265 109.205 400 ;
    END
  END rdata_asic[114]
  PIN rdata_asic[115]
    DIRECTION OUTPUT ;
    USE SIGNAL ;
    PORT
      LAYER M7 ;
        RECT 109.405 396.265 109.505 400 ;
    END
  END rdata_asic[115]
  PIN rdata_asic[116]
    DIRECTION OUTPUT ;
    USE SIGNAL ;
    PORT
      LAYER M7 ;
        RECT 109.705 396.265 109.805 400 ;
    END
  END rdata_asic[116]
  PIN rdata_asic[117]
    DIRECTION OUTPUT ;
    USE SIGNAL ;
    PORT
      LAYER M7 ;
        RECT 110.005 396.265 110.105 400 ;
    END
  END rdata_asic[117]
  PIN rdata_asic[118]
    DIRECTION OUTPUT ;
    USE SIGNAL ;
    PORT
      LAYER M7 ;
        RECT 110.305 396.265 110.405 400 ;
    END
  END rdata_asic[118]
  PIN rdata_asic[119]
    DIRECTION OUTPUT ;
    USE SIGNAL ;
    PORT
      LAYER M7 ;
        RECT 110.605 396.265 110.705 400 ;
    END
  END rdata_asic[119]
  PIN rdata_asic[11]
    DIRECTION OUTPUT ;
    USE SIGNAL ;
    PORT
      LAYER M7 ;
        RECT 68.455 396.265 68.555 400 ;
    END
  END rdata_asic[11]
  PIN rdata_asic[120]
    DIRECTION OUTPUT ;
    USE SIGNAL ;
    PORT
      LAYER M7 ;
        RECT 110.905 396.265 111.005 400 ;
    END
  END rdata_asic[120]
  PIN rdata_asic[121]
    DIRECTION OUTPUT ;
    USE SIGNAL ;
    PORT
      LAYER M7 ;
        RECT 111.205 396.265 111.305 400 ;
    END
  END rdata_asic[121]
  PIN rdata_asic[122]
    DIRECTION OUTPUT ;
    USE SIGNAL ;
    PORT
      LAYER M7 ;
        RECT 111.505 396.265 111.605 400 ;
    END
  END rdata_asic[122]
  PIN rdata_asic[123]
    DIRECTION OUTPUT ;
    USE SIGNAL ;
    PORT
      LAYER M7 ;
        RECT 111.805 396.265 111.905 400 ;
    END
  END rdata_asic[123]
  PIN rdata_asic[124]
    DIRECTION OUTPUT ;
    USE SIGNAL ;
    PORT
      LAYER M7 ;
        RECT 112.105 396.265 112.205 400 ;
    END
  END rdata_asic[124]
  PIN rdata_asic[125]
    DIRECTION OUTPUT ;
    USE SIGNAL ;
    PORT
      LAYER M7 ;
        RECT 112.405 396.265 112.505 400 ;
    END
  END rdata_asic[125]
  PIN rdata_asic[126]
    DIRECTION OUTPUT ;
    USE SIGNAL ;
    PORT
      LAYER M7 ;
        RECT 112.705 396.265 112.805 400 ;
    END
  END rdata_asic[126]
  PIN rdata_asic[127]
    DIRECTION OUTPUT ;
    USE SIGNAL ;
    PORT
      LAYER M7 ;
        RECT 113.005 396.265 113.105 400 ;
    END
  END rdata_asic[127]
  PIN rdata_asic[128]
    DIRECTION OUTPUT ;
    USE SIGNAL ;
    PORT
      LAYER M7 ;
        RECT 113.305 396.265 113.405 400 ;
    END
  END rdata_asic[128]
  PIN rdata_asic[129]
    DIRECTION OUTPUT ;
    USE SIGNAL ;
    PORT
      LAYER M7 ;
        RECT 113.605 396.265 113.705 400 ;
    END
  END rdata_asic[129]
  PIN rdata_asic[12]
    DIRECTION OUTPUT ;
    USE SIGNAL ;
    PORT
      LAYER M7 ;
        RECT 68.755 396.265 68.855 400 ;
    END
  END rdata_asic[12]
  PIN rdata_asic[130]
    DIRECTION OUTPUT ;
    USE SIGNAL ;
    PORT
      LAYER M7 ;
        RECT 113.905 396.265 114.005 400 ;
    END
  END rdata_asic[130]
  PIN rdata_asic[131]
    DIRECTION OUTPUT ;
    USE SIGNAL ;
    PORT
      LAYER M7 ;
        RECT 114.205 396.265 114.305 400 ;
    END
  END rdata_asic[131]
  PIN rdata_asic[132]
    DIRECTION OUTPUT ;
    USE SIGNAL ;
    PORT
      LAYER M7 ;
        RECT 114.505 396.265 114.605 400 ;
    END
  END rdata_asic[132]
  PIN rdata_asic[133]
    DIRECTION OUTPUT ;
    USE SIGNAL ;
    PORT
      LAYER M7 ;
        RECT 114.805 396.265 114.905 400 ;
    END
  END rdata_asic[133]
  PIN rdata_asic[134]
    DIRECTION OUTPUT ;
    USE SIGNAL ;
    PORT
      LAYER M7 ;
        RECT 115.105 396.265 115.205 400 ;
    END
  END rdata_asic[134]
  PIN rdata_asic[135]
    DIRECTION OUTPUT ;
    USE SIGNAL ;
    PORT
      LAYER M7 ;
        RECT 115.405 396.265 115.505 400 ;
    END
  END rdata_asic[135]
  PIN rdata_asic[136]
    DIRECTION OUTPUT ;
    USE SIGNAL ;
    PORT
      LAYER M7 ;
        RECT 124.495 396.265 124.595 400 ;
    END
  END rdata_asic[136]
  PIN rdata_asic[137]
    DIRECTION OUTPUT ;
    USE SIGNAL ;
    PORT
      LAYER M7 ;
        RECT 124.795 396.265 124.895 400 ;
    END
  END rdata_asic[137]
  PIN rdata_asic[138]
    DIRECTION OUTPUT ;
    USE SIGNAL ;
    PORT
      LAYER M7 ;
        RECT 125.095 396.265 125.195 400 ;
    END
  END rdata_asic[138]
  PIN rdata_asic[139]
    DIRECTION OUTPUT ;
    USE SIGNAL ;
    PORT
      LAYER M7 ;
        RECT 125.395 396.265 125.495 400 ;
    END
  END rdata_asic[139]
  PIN rdata_asic[13]
    DIRECTION OUTPUT ;
    USE SIGNAL ;
    PORT
      LAYER M7 ;
        RECT 69.055 396.265 69.155 400 ;
    END
  END rdata_asic[13]
  PIN rdata_asic[140]
    DIRECTION OUTPUT ;
    USE SIGNAL ;
    PORT
      LAYER M7 ;
        RECT 125.695 396.265 125.795 400 ;
    END
  END rdata_asic[140]
  PIN rdata_asic[141]
    DIRECTION OUTPUT ;
    USE SIGNAL ;
    PORT
      LAYER M7 ;
        RECT 125.995 396.265 126.095 400 ;
    END
  END rdata_asic[141]
  PIN rdata_asic[142]
    DIRECTION OUTPUT ;
    USE SIGNAL ;
    PORT
      LAYER M7 ;
        RECT 126.295 396.265 126.395 400 ;
    END
  END rdata_asic[142]
  PIN rdata_asic[143]
    DIRECTION OUTPUT ;
    USE SIGNAL ;
    PORT
      LAYER M7 ;
        RECT 126.595 396.265 126.695 400 ;
    END
  END rdata_asic[143]
  PIN rdata_asic[144]
    DIRECTION OUTPUT ;
    USE SIGNAL ;
    PORT
      LAYER M7 ;
        RECT 126.895 396.265 126.995 400 ;
    END
  END rdata_asic[144]
  PIN rdata_asic[145]
    DIRECTION OUTPUT ;
    USE SIGNAL ;
    PORT
      LAYER M7 ;
        RECT 127.195 396.265 127.295 400 ;
    END
  END rdata_asic[145]
  PIN rdata_asic[146]
    DIRECTION OUTPUT ;
    USE SIGNAL ;
    PORT
      LAYER M7 ;
        RECT 127.495 396.265 127.595 400 ;
    END
  END rdata_asic[146]
  PIN rdata_asic[147]
    DIRECTION OUTPUT ;
    USE SIGNAL ;
    PORT
      LAYER M7 ;
        RECT 127.795 396.265 127.895 400 ;
    END
  END rdata_asic[147]
  PIN rdata_asic[148]
    DIRECTION OUTPUT ;
    USE SIGNAL ;
    PORT
      LAYER M7 ;
        RECT 128.095 396.265 128.195 400 ;
    END
  END rdata_asic[148]
  PIN rdata_asic[149]
    DIRECTION OUTPUT ;
    USE SIGNAL ;
    PORT
      LAYER M7 ;
        RECT 128.395 396.265 128.495 400 ;
    END
  END rdata_asic[149]
  PIN rdata_asic[14]
    DIRECTION OUTPUT ;
    USE SIGNAL ;
    PORT
      LAYER M7 ;
        RECT 69.355 396.265 69.455 400 ;
    END
  END rdata_asic[14]
  PIN rdata_asic[150]
    DIRECTION OUTPUT ;
    USE SIGNAL ;
    PORT
      LAYER M7 ;
        RECT 128.695 396.265 128.795 400 ;
    END
  END rdata_asic[150]
  PIN rdata_asic[151]
    DIRECTION OUTPUT ;
    USE SIGNAL ;
    PORT
      LAYER M7 ;
        RECT 128.995 396.265 129.095 400 ;
    END
  END rdata_asic[151]
  PIN rdata_asic[152]
    DIRECTION OUTPUT ;
    USE SIGNAL ;
    PORT
      LAYER M7 ;
        RECT 129.295 396.265 129.395 400 ;
    END
  END rdata_asic[152]
  PIN rdata_asic[153]
    DIRECTION OUTPUT ;
    USE SIGNAL ;
    PORT
      LAYER M7 ;
        RECT 129.595 396.265 129.695 400 ;
    END
  END rdata_asic[153]
  PIN rdata_asic[154]
    DIRECTION OUTPUT ;
    USE SIGNAL ;
    PORT
      LAYER M7 ;
        RECT 129.895 396.265 129.995 400 ;
    END
  END rdata_asic[154]
  PIN rdata_asic[155]
    DIRECTION OUTPUT ;
    USE SIGNAL ;
    PORT
      LAYER M7 ;
        RECT 130.195 396.265 130.295 400 ;
    END
  END rdata_asic[155]
  PIN rdata_asic[156]
    DIRECTION OUTPUT ;
    USE SIGNAL ;
    PORT
      LAYER M7 ;
        RECT 130.495 396.265 130.595 400 ;
    END
  END rdata_asic[156]
  PIN rdata_asic[157]
    DIRECTION OUTPUT ;
    USE SIGNAL ;
    PORT
      LAYER M7 ;
        RECT 130.795 396.265 130.895 400 ;
    END
  END rdata_asic[157]
  PIN rdata_asic[158]
    DIRECTION OUTPUT ;
    USE SIGNAL ;
    PORT
      LAYER M7 ;
        RECT 131.095 396.265 131.195 400 ;
    END
  END rdata_asic[158]
  PIN rdata_asic[159]
    DIRECTION OUTPUT ;
    USE SIGNAL ;
    PORT
      LAYER M7 ;
        RECT 131.395 396.265 131.495 400 ;
    END
  END rdata_asic[159]
  PIN rdata_asic[15]
    DIRECTION OUTPUT ;
    USE SIGNAL ;
    PORT
      LAYER M7 ;
        RECT 69.655 396.265 69.755 400 ;
    END
  END rdata_asic[15]
  PIN rdata_asic[160]
    DIRECTION OUTPUT ;
    USE SIGNAL ;
    PORT
      LAYER M7 ;
        RECT 131.695 396.265 131.795 400 ;
    END
  END rdata_asic[160]
  PIN rdata_asic[161]
    DIRECTION OUTPUT ;
    USE SIGNAL ;
    PORT
      LAYER M7 ;
        RECT 131.995 396.265 132.095 400 ;
    END
  END rdata_asic[161]
  PIN rdata_asic[162]
    DIRECTION OUTPUT ;
    USE SIGNAL ;
    PORT
      LAYER M7 ;
        RECT 132.295 396.265 132.395 400 ;
    END
  END rdata_asic[162]
  PIN rdata_asic[163]
    DIRECTION OUTPUT ;
    USE SIGNAL ;
    PORT
      LAYER M7 ;
        RECT 132.595 396.265 132.695 400 ;
    END
  END rdata_asic[163]
  PIN rdata_asic[164]
    DIRECTION OUTPUT ;
    USE SIGNAL ;
    PORT
      LAYER M7 ;
        RECT 132.895 396.265 132.995 400 ;
    END
  END rdata_asic[164]
  PIN rdata_asic[165]
    DIRECTION OUTPUT ;
    USE SIGNAL ;
    PORT
      LAYER M7 ;
        RECT 133.195 396.265 133.295 400 ;
    END
  END rdata_asic[165]
  PIN rdata_asic[166]
    DIRECTION OUTPUT ;
    USE SIGNAL ;
    PORT
      LAYER M7 ;
        RECT 133.495 396.265 133.595 400 ;
    END
  END rdata_asic[166]
  PIN rdata_asic[167]
    DIRECTION OUTPUT ;
    USE SIGNAL ;
    PORT
      LAYER M7 ;
        RECT 133.795 396.265 133.895 400 ;
    END
  END rdata_asic[167]
  PIN rdata_asic[168]
    DIRECTION OUTPUT ;
    USE SIGNAL ;
    PORT
      LAYER M7 ;
        RECT 134.095 396.265 134.195 400 ;
    END
  END rdata_asic[168]
  PIN rdata_asic[169]
    DIRECTION OUTPUT ;
    USE SIGNAL ;
    PORT
      LAYER M7 ;
        RECT 134.395 396.265 134.495 400 ;
    END
  END rdata_asic[169]
  PIN rdata_asic[16]
    DIRECTION OUTPUT ;
    USE SIGNAL ;
    PORT
      LAYER M7 ;
        RECT 69.955 396.265 70.055 400 ;
    END
  END rdata_asic[16]
  PIN rdata_asic[170]
    DIRECTION OUTPUT ;
    USE SIGNAL ;
    PORT
      LAYER M7 ;
        RECT 137.945 396.265 138.045 400 ;
    END
  END rdata_asic[170]
  PIN rdata_asic[171]
    DIRECTION OUTPUT ;
    USE SIGNAL ;
    PORT
      LAYER M7 ;
        RECT 138.245 396.265 138.345 400 ;
    END
  END rdata_asic[171]
  PIN rdata_asic[172]
    DIRECTION OUTPUT ;
    USE SIGNAL ;
    PORT
      LAYER M7 ;
        RECT 138.545 396.265 138.645 400 ;
    END
  END rdata_asic[172]
  PIN rdata_asic[173]
    DIRECTION OUTPUT ;
    USE SIGNAL ;
    PORT
      LAYER M7 ;
        RECT 138.845 396.265 138.945 400 ;
    END
  END rdata_asic[173]
  PIN rdata_asic[174]
    DIRECTION OUTPUT ;
    USE SIGNAL ;
    PORT
      LAYER M7 ;
        RECT 139.145 396.265 139.245 400 ;
    END
  END rdata_asic[174]
  PIN rdata_asic[175]
    DIRECTION OUTPUT ;
    USE SIGNAL ;
    PORT
      LAYER M7 ;
        RECT 139.445 396.265 139.545 400 ;
    END
  END rdata_asic[175]
  PIN rdata_asic[176]
    DIRECTION OUTPUT ;
    USE SIGNAL ;
    PORT
      LAYER M7 ;
        RECT 139.745 396.265 139.845 400 ;
    END
  END rdata_asic[176]
  PIN rdata_asic[177]
    DIRECTION OUTPUT ;
    USE SIGNAL ;
    PORT
      LAYER M7 ;
        RECT 140.045 396.265 140.145 400 ;
    END
  END rdata_asic[177]
  PIN rdata_asic[178]
    DIRECTION OUTPUT ;
    USE SIGNAL ;
    PORT
      LAYER M7 ;
        RECT 140.345 396.265 140.445 400 ;
    END
  END rdata_asic[178]
  PIN rdata_asic[179]
    DIRECTION OUTPUT ;
    USE SIGNAL ;
    PORT
      LAYER M7 ;
        RECT 140.645 396.265 140.745 400 ;
    END
  END rdata_asic[179]
  PIN rdata_asic[17]
    DIRECTION OUTPUT ;
    USE SIGNAL ;
    PORT
      LAYER M7 ;
        RECT 70.255 396.265 70.355 400 ;
    END
  END rdata_asic[17]
  PIN rdata_asic[180]
    DIRECTION OUTPUT ;
    USE SIGNAL ;
    PORT
      LAYER M7 ;
        RECT 140.945 396.265 141.045 400 ;
    END
  END rdata_asic[180]
  PIN rdata_asic[181]
    DIRECTION OUTPUT ;
    USE SIGNAL ;
    PORT
      LAYER M7 ;
        RECT 141.245 396.265 141.345 400 ;
    END
  END rdata_asic[181]
  PIN rdata_asic[182]
    DIRECTION OUTPUT ;
    USE SIGNAL ;
    PORT
      LAYER M7 ;
        RECT 141.545 396.265 141.645 400 ;
    END
  END rdata_asic[182]
  PIN rdata_asic[183]
    DIRECTION OUTPUT ;
    USE SIGNAL ;
    PORT
      LAYER M7 ;
        RECT 141.845 396.265 141.945 400 ;
    END
  END rdata_asic[183]
  PIN rdata_asic[184]
    DIRECTION OUTPUT ;
    USE SIGNAL ;
    PORT
      LAYER M7 ;
        RECT 142.145 396.265 142.245 400 ;
    END
  END rdata_asic[184]
  PIN rdata_asic[185]
    DIRECTION OUTPUT ;
    USE SIGNAL ;
    PORT
      LAYER M7 ;
        RECT 142.445 396.265 142.545 400 ;
    END
  END rdata_asic[185]
  PIN rdata_asic[186]
    DIRECTION OUTPUT ;
    USE SIGNAL ;
    PORT
      LAYER M7 ;
        RECT 142.745 396.265 142.845 400 ;
    END
  END rdata_asic[186]
  PIN rdata_asic[187]
    DIRECTION OUTPUT ;
    USE SIGNAL ;
    PORT
      LAYER M7 ;
        RECT 143.045 396.265 143.145 400 ;
    END
  END rdata_asic[187]
  PIN rdata_asic[188]
    DIRECTION OUTPUT ;
    USE SIGNAL ;
    PORT
      LAYER M7 ;
        RECT 143.345 396.265 143.445 400 ;
    END
  END rdata_asic[188]
  PIN rdata_asic[189]
    DIRECTION OUTPUT ;
    USE SIGNAL ;
    PORT
      LAYER M7 ;
        RECT 143.645 396.265 143.745 400 ;
    END
  END rdata_asic[189]
  PIN rdata_asic[18]
    DIRECTION OUTPUT ;
    USE SIGNAL ;
    PORT
      LAYER M7 ;
        RECT 70.555 396.265 70.655 400 ;
    END
  END rdata_asic[18]
  PIN rdata_asic[190]
    DIRECTION OUTPUT ;
    USE SIGNAL ;
    PORT
      LAYER M7 ;
        RECT 143.945 396.265 144.045 400 ;
    END
  END rdata_asic[190]
  PIN rdata_asic[191]
    DIRECTION OUTPUT ;
    USE SIGNAL ;
    PORT
      LAYER M7 ;
        RECT 144.245 396.265 144.345 400 ;
    END
  END rdata_asic[191]
  PIN rdata_asic[192]
    DIRECTION OUTPUT ;
    USE SIGNAL ;
    PORT
      LAYER M7 ;
        RECT 144.545 396.265 144.645 400 ;
    END
  END rdata_asic[192]
  PIN rdata_asic[193]
    DIRECTION OUTPUT ;
    USE SIGNAL ;
    PORT
      LAYER M7 ;
        RECT 144.845 396.265 144.945 400 ;
    END
  END rdata_asic[193]
  PIN rdata_asic[194]
    DIRECTION OUTPUT ;
    USE SIGNAL ;
    PORT
      LAYER M7 ;
        RECT 145.145 396.265 145.245 400 ;
    END
  END rdata_asic[194]
  PIN rdata_asic[195]
    DIRECTION OUTPUT ;
    USE SIGNAL ;
    PORT
      LAYER M7 ;
        RECT 145.445 396.265 145.545 400 ;
    END
  END rdata_asic[195]
  PIN rdata_asic[196]
    DIRECTION OUTPUT ;
    USE SIGNAL ;
    PORT
      LAYER M7 ;
        RECT 145.745 396.265 145.845 400 ;
    END
  END rdata_asic[196]
  PIN rdata_asic[197]
    DIRECTION OUTPUT ;
    USE SIGNAL ;
    PORT
      LAYER M7 ;
        RECT 146.045 396.265 146.145 400 ;
    END
  END rdata_asic[197]
  PIN rdata_asic[198]
    DIRECTION OUTPUT ;
    USE SIGNAL ;
    PORT
      LAYER M7 ;
        RECT 146.345 396.265 146.445 400 ;
    END
  END rdata_asic[198]
  PIN rdata_asic[199]
    DIRECTION OUTPUT ;
    USE SIGNAL ;
    PORT
      LAYER M7 ;
        RECT 146.645 396.265 146.745 400 ;
    END
  END rdata_asic[199]
  PIN rdata_asic[19]
    DIRECTION OUTPUT ;
    USE SIGNAL ;
    PORT
      LAYER M7 ;
        RECT 70.855 396.265 70.955 400 ;
    END
  END rdata_asic[19]
  PIN rdata_asic[1]
    DIRECTION OUTPUT ;
    USE SIGNAL ;
    PORT
      LAYER M7 ;
        RECT 65.455 396.265 65.555 400 ;
    END
  END rdata_asic[1]
  PIN rdata_asic[200]
    DIRECTION OUTPUT ;
    USE SIGNAL ;
    PORT
      LAYER M7 ;
        RECT 146.945 396.265 147.045 400 ;
    END
  END rdata_asic[200]
  PIN rdata_asic[201]
    DIRECTION OUTPUT ;
    USE SIGNAL ;
    PORT
      LAYER M7 ;
        RECT 147.245 396.265 147.345 400 ;
    END
  END rdata_asic[201]
  PIN rdata_asic[202]
    DIRECTION OUTPUT ;
    USE SIGNAL ;
    PORT
      LAYER M7 ;
        RECT 147.545 396.265 147.645 400 ;
    END
  END rdata_asic[202]
  PIN rdata_asic[203]
    DIRECTION OUTPUT ;
    USE SIGNAL ;
    PORT
      LAYER M7 ;
        RECT 147.845 396.265 147.945 400 ;
    END
  END rdata_asic[203]
  PIN rdata_asic[204]
    DIRECTION OUTPUT ;
    USE SIGNAL ;
    PORT
      LAYER M7 ;
        RECT 151.395 396.265 151.495 400 ;
    END
  END rdata_asic[204]
  PIN rdata_asic[205]
    DIRECTION OUTPUT ;
    USE SIGNAL ;
    PORT
      LAYER M7 ;
        RECT 151.695 396.265 151.795 400 ;
    END
  END rdata_asic[205]
  PIN rdata_asic[206]
    DIRECTION OUTPUT ;
    USE SIGNAL ;
    PORT
      LAYER M7 ;
        RECT 151.995 396.265 152.095 400 ;
    END
  END rdata_asic[206]
  PIN rdata_asic[207]
    DIRECTION OUTPUT ;
    USE SIGNAL ;
    PORT
      LAYER M7 ;
        RECT 152.295 396.265 152.395 400 ;
    END
  END rdata_asic[207]
  PIN rdata_asic[208]
    DIRECTION OUTPUT ;
    USE SIGNAL ;
    PORT
      LAYER M7 ;
        RECT 152.595 396.265 152.695 400 ;
    END
  END rdata_asic[208]
  PIN rdata_asic[209]
    DIRECTION OUTPUT ;
    USE SIGNAL ;
    PORT
      LAYER M7 ;
        RECT 152.895 396.265 152.995 400 ;
    END
  END rdata_asic[209]
  PIN rdata_asic[20]
    DIRECTION OUTPUT ;
    USE SIGNAL ;
    PORT
      LAYER M7 ;
        RECT 71.155 396.265 71.255 400 ;
    END
  END rdata_asic[20]
  PIN rdata_asic[210]
    DIRECTION OUTPUT ;
    USE SIGNAL ;
    PORT
      LAYER M7 ;
        RECT 153.195 396.265 153.295 400 ;
    END
  END rdata_asic[210]
  PIN rdata_asic[211]
    DIRECTION OUTPUT ;
    USE SIGNAL ;
    PORT
      LAYER M7 ;
        RECT 153.495 396.265 153.595 400 ;
    END
  END rdata_asic[211]
  PIN rdata_asic[212]
    DIRECTION OUTPUT ;
    USE SIGNAL ;
    PORT
      LAYER M7 ;
        RECT 153.795 396.265 153.895 400 ;
    END
  END rdata_asic[212]
  PIN rdata_asic[213]
    DIRECTION OUTPUT ;
    USE SIGNAL ;
    PORT
      LAYER M7 ;
        RECT 154.095 396.265 154.195 400 ;
    END
  END rdata_asic[213]
  PIN rdata_asic[214]
    DIRECTION OUTPUT ;
    USE SIGNAL ;
    PORT
      LAYER M7 ;
        RECT 154.395 396.265 154.495 400 ;
    END
  END rdata_asic[214]
  PIN rdata_asic[215]
    DIRECTION OUTPUT ;
    USE SIGNAL ;
    PORT
      LAYER M7 ;
        RECT 154.695 396.265 154.795 400 ;
    END
  END rdata_asic[215]
  PIN rdata_asic[216]
    DIRECTION OUTPUT ;
    USE SIGNAL ;
    PORT
      LAYER M7 ;
        RECT 154.995 396.265 155.095 400 ;
    END
  END rdata_asic[216]
  PIN rdata_asic[217]
    DIRECTION OUTPUT ;
    USE SIGNAL ;
    PORT
      LAYER M7 ;
        RECT 155.295 396.265 155.395 400 ;
    END
  END rdata_asic[217]
  PIN rdata_asic[218]
    DIRECTION OUTPUT ;
    USE SIGNAL ;
    PORT
      LAYER M7 ;
        RECT 155.595 396.265 155.695 400 ;
    END
  END rdata_asic[218]
  PIN rdata_asic[219]
    DIRECTION OUTPUT ;
    USE SIGNAL ;
    PORT
      LAYER M7 ;
        RECT 155.895 396.265 155.995 400 ;
    END
  END rdata_asic[219]
  PIN rdata_asic[21]
    DIRECTION OUTPUT ;
    USE SIGNAL ;
    PORT
      LAYER M7 ;
        RECT 71.455 396.265 71.555 400 ;
    END
  END rdata_asic[21]
  PIN rdata_asic[220]
    DIRECTION OUTPUT ;
    USE SIGNAL ;
    PORT
      LAYER M7 ;
        RECT 156.195 396.265 156.295 400 ;
    END
  END rdata_asic[220]
  PIN rdata_asic[221]
    DIRECTION OUTPUT ;
    USE SIGNAL ;
    PORT
      LAYER M7 ;
        RECT 156.495 396.265 156.595 400 ;
    END
  END rdata_asic[221]
  PIN rdata_asic[222]
    DIRECTION OUTPUT ;
    USE SIGNAL ;
    PORT
      LAYER M7 ;
        RECT 156.795 396.265 156.895 400 ;
    END
  END rdata_asic[222]
  PIN rdata_asic[223]
    DIRECTION OUTPUT ;
    USE SIGNAL ;
    PORT
      LAYER M7 ;
        RECT 157.095 396.265 157.195 400 ;
    END
  END rdata_asic[223]
  PIN rdata_asic[224]
    DIRECTION OUTPUT ;
    USE SIGNAL ;
    PORT
      LAYER M7 ;
        RECT 157.395 396.265 157.495 400 ;
    END
  END rdata_asic[224]
  PIN rdata_asic[225]
    DIRECTION OUTPUT ;
    USE SIGNAL ;
    PORT
      LAYER M7 ;
        RECT 157.695 396.265 157.795 400 ;
    END
  END rdata_asic[225]
  PIN rdata_asic[226]
    DIRECTION OUTPUT ;
    USE SIGNAL ;
    PORT
      LAYER M7 ;
        RECT 157.995 396.265 158.095 400 ;
    END
  END rdata_asic[226]
  PIN rdata_asic[227]
    DIRECTION OUTPUT ;
    USE SIGNAL ;
    PORT
      LAYER M7 ;
        RECT 158.295 396.265 158.395 400 ;
    END
  END rdata_asic[227]
  PIN rdata_asic[228]
    DIRECTION OUTPUT ;
    USE SIGNAL ;
    PORT
      LAYER M7 ;
        RECT 158.595 396.265 158.695 400 ;
    END
  END rdata_asic[228]
  PIN rdata_asic[229]
    DIRECTION OUTPUT ;
    USE SIGNAL ;
    PORT
      LAYER M7 ;
        RECT 158.895 396.265 158.995 400 ;
    END
  END rdata_asic[229]
  PIN rdata_asic[22]
    DIRECTION OUTPUT ;
    USE SIGNAL ;
    PORT
      LAYER M7 ;
        RECT 71.755 396.265 71.855 400 ;
    END
  END rdata_asic[22]
  PIN rdata_asic[230]
    DIRECTION OUTPUT ;
    USE SIGNAL ;
    PORT
      LAYER M7 ;
        RECT 159.195 396.265 159.295 400 ;
    END
  END rdata_asic[230]
  PIN rdata_asic[231]
    DIRECTION OUTPUT ;
    USE SIGNAL ;
    PORT
      LAYER M7 ;
        RECT 159.495 396.265 159.595 400 ;
    END
  END rdata_asic[231]
  PIN rdata_asic[232]
    DIRECTION OUTPUT ;
    USE SIGNAL ;
    PORT
      LAYER M7 ;
        RECT 159.795 396.265 159.895 400 ;
    END
  END rdata_asic[232]
  PIN rdata_asic[233]
    DIRECTION OUTPUT ;
    USE SIGNAL ;
    PORT
      LAYER M7 ;
        RECT 160.095 396.265 160.195 400 ;
    END
  END rdata_asic[233]
  PIN rdata_asic[234]
    DIRECTION OUTPUT ;
    USE SIGNAL ;
    PORT
      LAYER M7 ;
        RECT 160.395 396.265 160.495 400 ;
    END
  END rdata_asic[234]
  PIN rdata_asic[235]
    DIRECTION OUTPUT ;
    USE SIGNAL ;
    PORT
      LAYER M7 ;
        RECT 160.695 396.265 160.795 400 ;
    END
  END rdata_asic[235]
  PIN rdata_asic[236]
    DIRECTION OUTPUT ;
    USE SIGNAL ;
    PORT
      LAYER M7 ;
        RECT 160.995 396.265 161.095 400 ;
    END
  END rdata_asic[236]
  PIN rdata_asic[237]
    DIRECTION OUTPUT ;
    USE SIGNAL ;
    PORT
      LAYER M7 ;
        RECT 161.295 396.265 161.395 400 ;
    END
  END rdata_asic[237]
  PIN rdata_asic[238]
    DIRECTION OUTPUT ;
    USE SIGNAL ;
    PORT
      LAYER M7 ;
        RECT 164.845 396.265 164.945 400 ;
    END
  END rdata_asic[238]
  PIN rdata_asic[239]
    DIRECTION OUTPUT ;
    USE SIGNAL ;
    PORT
      LAYER M7 ;
        RECT 165.145 396.265 165.245 400 ;
    END
  END rdata_asic[239]
  PIN rdata_asic[23]
    DIRECTION OUTPUT ;
    USE SIGNAL ;
    PORT
      LAYER M7 ;
        RECT 72.055 396.265 72.155 400 ;
    END
  END rdata_asic[23]
  PIN rdata_asic[240]
    DIRECTION OUTPUT ;
    USE SIGNAL ;
    PORT
      LAYER M7 ;
        RECT 165.445 396.265 165.545 400 ;
    END
  END rdata_asic[240]
  PIN rdata_asic[241]
    DIRECTION OUTPUT ;
    USE SIGNAL ;
    PORT
      LAYER M7 ;
        RECT 165.745 396.265 165.845 400 ;
    END
  END rdata_asic[241]
  PIN rdata_asic[242]
    DIRECTION OUTPUT ;
    USE SIGNAL ;
    PORT
      LAYER M7 ;
        RECT 166.045 396.265 166.145 400 ;
    END
  END rdata_asic[242]
  PIN rdata_asic[243]
    DIRECTION OUTPUT ;
    USE SIGNAL ;
    PORT
      LAYER M7 ;
        RECT 166.345 396.265 166.445 400 ;
    END
  END rdata_asic[243]
  PIN rdata_asic[244]
    DIRECTION OUTPUT ;
    USE SIGNAL ;
    PORT
      LAYER M7 ;
        RECT 166.645 396.265 166.745 400 ;
    END
  END rdata_asic[244]
  PIN rdata_asic[245]
    DIRECTION OUTPUT ;
    USE SIGNAL ;
    PORT
      LAYER M7 ;
        RECT 166.945 396.265 167.045 400 ;
    END
  END rdata_asic[245]
  PIN rdata_asic[246]
    DIRECTION OUTPUT ;
    USE SIGNAL ;
    PORT
      LAYER M7 ;
        RECT 167.245 396.265 167.345 400 ;
    END
  END rdata_asic[246]
  PIN rdata_asic[247]
    DIRECTION OUTPUT ;
    USE SIGNAL ;
    PORT
      LAYER M7 ;
        RECT 167.545 396.265 167.645 400 ;
    END
  END rdata_asic[247]
  PIN rdata_asic[248]
    DIRECTION OUTPUT ;
    USE SIGNAL ;
    PORT
      LAYER M7 ;
        RECT 167.845 396.265 167.945 400 ;
    END
  END rdata_asic[248]
  PIN rdata_asic[249]
    DIRECTION OUTPUT ;
    USE SIGNAL ;
    PORT
      LAYER M7 ;
        RECT 168.145 396.265 168.245 400 ;
    END
  END rdata_asic[249]
  PIN rdata_asic[24]
    DIRECTION OUTPUT ;
    USE SIGNAL ;
    PORT
      LAYER M7 ;
        RECT 72.355 396.265 72.455 400 ;
    END
  END rdata_asic[24]
  PIN rdata_asic[250]
    DIRECTION OUTPUT ;
    USE SIGNAL ;
    PORT
      LAYER M7 ;
        RECT 168.445 396.265 168.545 400 ;
    END
  END rdata_asic[250]
  PIN rdata_asic[251]
    DIRECTION OUTPUT ;
    USE SIGNAL ;
    PORT
      LAYER M7 ;
        RECT 168.745 396.265 168.845 400 ;
    END
  END rdata_asic[251]
  PIN rdata_asic[252]
    DIRECTION OUTPUT ;
    USE SIGNAL ;
    PORT
      LAYER M7 ;
        RECT 169.045 396.265 169.145 400 ;
    END
  END rdata_asic[252]
  PIN rdata_asic[253]
    DIRECTION OUTPUT ;
    USE SIGNAL ;
    PORT
      LAYER M7 ;
        RECT 169.345 396.265 169.445 400 ;
    END
  END rdata_asic[253]
  PIN rdata_asic[254]
    DIRECTION OUTPUT ;
    USE SIGNAL ;
    PORT
      LAYER M7 ;
        RECT 169.645 396.265 169.745 400 ;
    END
  END rdata_asic[254]
  PIN rdata_asic[255]
    DIRECTION OUTPUT ;
    USE SIGNAL ;
    PORT
      LAYER M7 ;
        RECT 169.945 396.265 170.045 400 ;
    END
  END rdata_asic[255]
  PIN rdata_asic[256]
    DIRECTION OUTPUT ;
    USE SIGNAL ;
    PORT
      LAYER M7 ;
        RECT 170.245 396.265 170.345 400 ;
    END
  END rdata_asic[256]
  PIN rdata_asic[257]
    DIRECTION OUTPUT ;
    USE SIGNAL ;
    PORT
      LAYER M7 ;
        RECT 170.545 396.265 170.645 400 ;
    END
  END rdata_asic[257]
  PIN rdata_asic[258]
    DIRECTION OUTPUT ;
    USE SIGNAL ;
    PORT
      LAYER M7 ;
        RECT 170.845 396.265 170.945 400 ;
    END
  END rdata_asic[258]
  PIN rdata_asic[259]
    DIRECTION OUTPUT ;
    USE SIGNAL ;
    PORT
      LAYER M7 ;
        RECT 171.145 396.265 171.245 400 ;
    END
  END rdata_asic[259]
  PIN rdata_asic[25]
    DIRECTION OUTPUT ;
    USE SIGNAL ;
    PORT
      LAYER M7 ;
        RECT 72.655 396.265 72.755 400 ;
    END
  END rdata_asic[25]
  PIN rdata_asic[260]
    DIRECTION OUTPUT ;
    USE SIGNAL ;
    PORT
      LAYER M7 ;
        RECT 171.445 396.265 171.545 400 ;
    END
  END rdata_asic[260]
  PIN rdata_asic[261]
    DIRECTION OUTPUT ;
    USE SIGNAL ;
    PORT
      LAYER M7 ;
        RECT 171.745 396.265 171.845 400 ;
    END
  END rdata_asic[261]
  PIN rdata_asic[262]
    DIRECTION OUTPUT ;
    USE SIGNAL ;
    PORT
      LAYER M7 ;
        RECT 172.045 396.265 172.145 400 ;
    END
  END rdata_asic[262]
  PIN rdata_asic[263]
    DIRECTION OUTPUT ;
    USE SIGNAL ;
    PORT
      LAYER M7 ;
        RECT 172.345 396.265 172.445 400 ;
    END
  END rdata_asic[263]
  PIN rdata_asic[264]
    DIRECTION OUTPUT ;
    USE SIGNAL ;
    PORT
      LAYER M7 ;
        RECT 172.645 396.265 172.745 400 ;
    END
  END rdata_asic[264]
  PIN rdata_asic[265]
    DIRECTION OUTPUT ;
    USE SIGNAL ;
    PORT
      LAYER M7 ;
        RECT 172.945 396.265 173.045 400 ;
    END
  END rdata_asic[265]
  PIN rdata_asic[266]
    DIRECTION OUTPUT ;
    USE SIGNAL ;
    PORT
      LAYER M7 ;
        RECT 173.245 396.265 173.345 400 ;
    END
  END rdata_asic[266]
  PIN rdata_asic[267]
    DIRECTION OUTPUT ;
    USE SIGNAL ;
    PORT
      LAYER M7 ;
        RECT 173.545 396.265 173.645 400 ;
    END
  END rdata_asic[267]
  PIN rdata_asic[268]
    DIRECTION OUTPUT ;
    USE SIGNAL ;
    PORT
      LAYER M7 ;
        RECT 173.845 396.265 173.945 400 ;
    END
  END rdata_asic[268]
  PIN rdata_asic[269]
    DIRECTION OUTPUT ;
    USE SIGNAL ;
    PORT
      LAYER M7 ;
        RECT 174.145 396.265 174.245 400 ;
    END
  END rdata_asic[269]
  PIN rdata_asic[26]
    DIRECTION OUTPUT ;
    USE SIGNAL ;
    PORT
      LAYER M7 ;
        RECT 72.955 396.265 73.055 400 ;
    END
  END rdata_asic[26]
  PIN rdata_asic[270]
    DIRECTION OUTPUT ;
    USE SIGNAL ;
    PORT
      LAYER M7 ;
        RECT 174.445 396.265 174.545 400 ;
    END
  END rdata_asic[270]
  PIN rdata_asic[271]
    DIRECTION OUTPUT ;
    USE SIGNAL ;
    PORT
      LAYER M7 ;
        RECT 174.745 396.265 174.845 400 ;
    END
  END rdata_asic[271]
  PIN rdata_asic[27]
    DIRECTION OUTPUT ;
    USE SIGNAL ;
    PORT
      LAYER M7 ;
        RECT 73.255 396.265 73.355 400 ;
    END
  END rdata_asic[27]
  PIN rdata_asic[28]
    DIRECTION OUTPUT ;
    USE SIGNAL ;
    PORT
      LAYER M7 ;
        RECT 73.555 396.265 73.655 400 ;
    END
  END rdata_asic[28]
  PIN rdata_asic[29]
    DIRECTION OUTPUT ;
    USE SIGNAL ;
    PORT
      LAYER M7 ;
        RECT 73.855 396.265 73.955 400 ;
    END
  END rdata_asic[29]
  PIN rdata_asic[2]
    DIRECTION OUTPUT ;
    USE SIGNAL ;
    PORT
      LAYER M7 ;
        RECT 65.755 396.265 65.855 400 ;
    END
  END rdata_asic[2]
  PIN rdata_asic[30]
    DIRECTION OUTPUT ;
    USE SIGNAL ;
    PORT
      LAYER M7 ;
        RECT 74.155 396.265 74.255 400 ;
    END
  END rdata_asic[30]
  PIN rdata_asic[31]
    DIRECTION OUTPUT ;
    USE SIGNAL ;
    PORT
      LAYER M7 ;
        RECT 74.455 396.265 74.555 400 ;
    END
  END rdata_asic[31]
  PIN rdata_asic[32]
    DIRECTION OUTPUT ;
    USE SIGNAL ;
    PORT
      LAYER M7 ;
        RECT 74.755 396.265 74.855 400 ;
    END
  END rdata_asic[32]
  PIN rdata_asic[33]
    DIRECTION OUTPUT ;
    USE SIGNAL ;
    PORT
      LAYER M7 ;
        RECT 75.055 396.265 75.155 400 ;
    END
  END rdata_asic[33]
  PIN rdata_asic[34]
    DIRECTION OUTPUT ;
    USE SIGNAL ;
    PORT
      LAYER M7 ;
        RECT 78.605 396.265 78.705 400 ;
    END
  END rdata_asic[34]
  PIN rdata_asic[35]
    DIRECTION OUTPUT ;
    USE SIGNAL ;
    PORT
      LAYER M7 ;
        RECT 78.905 396.265 79.005 400 ;
    END
  END rdata_asic[35]
  PIN rdata_asic[36]
    DIRECTION OUTPUT ;
    USE SIGNAL ;
    PORT
      LAYER M7 ;
        RECT 79.205 396.265 79.305 400 ;
    END
  END rdata_asic[36]
  PIN rdata_asic[37]
    DIRECTION OUTPUT ;
    USE SIGNAL ;
    PORT
      LAYER M7 ;
        RECT 79.505 396.265 79.605 400 ;
    END
  END rdata_asic[37]
  PIN rdata_asic[38]
    DIRECTION OUTPUT ;
    USE SIGNAL ;
    PORT
      LAYER M7 ;
        RECT 79.805 396.265 79.905 400 ;
    END
  END rdata_asic[38]
  PIN rdata_asic[39]
    DIRECTION OUTPUT ;
    USE SIGNAL ;
    PORT
      LAYER M7 ;
        RECT 80.105 396.265 80.205 400 ;
    END
  END rdata_asic[39]
  PIN rdata_asic[3]
    DIRECTION OUTPUT ;
    USE SIGNAL ;
    PORT
      LAYER M7 ;
        RECT 66.055 396.265 66.155 400 ;
    END
  END rdata_asic[3]
  PIN rdata_asic[40]
    DIRECTION OUTPUT ;
    USE SIGNAL ;
    PORT
      LAYER M7 ;
        RECT 80.405 396.265 80.505 400 ;
    END
  END rdata_asic[40]
  PIN rdata_asic[41]
    DIRECTION OUTPUT ;
    USE SIGNAL ;
    PORT
      LAYER M7 ;
        RECT 80.705 396.265 80.805 400 ;
    END
  END rdata_asic[41]
  PIN rdata_asic[42]
    DIRECTION OUTPUT ;
    USE SIGNAL ;
    PORT
      LAYER M7 ;
        RECT 81.005 396.265 81.105 400 ;
    END
  END rdata_asic[42]
  PIN rdata_asic[43]
    DIRECTION OUTPUT ;
    USE SIGNAL ;
    PORT
      LAYER M7 ;
        RECT 81.305 396.265 81.405 400 ;
    END
  END rdata_asic[43]
  PIN rdata_asic[44]
    DIRECTION OUTPUT ;
    USE SIGNAL ;
    PORT
      LAYER M7 ;
        RECT 81.605 396.265 81.705 400 ;
    END
  END rdata_asic[44]
  PIN rdata_asic[45]
    DIRECTION OUTPUT ;
    USE SIGNAL ;
    PORT
      LAYER M7 ;
        RECT 81.905 396.265 82.005 400 ;
    END
  END rdata_asic[45]
  PIN rdata_asic[46]
    DIRECTION OUTPUT ;
    USE SIGNAL ;
    PORT
      LAYER M7 ;
        RECT 82.205 396.265 82.305 400 ;
    END
  END rdata_asic[46]
  PIN rdata_asic[47]
    DIRECTION OUTPUT ;
    USE SIGNAL ;
    PORT
      LAYER M7 ;
        RECT 82.505 396.265 82.605 400 ;
    END
  END rdata_asic[47]
  PIN rdata_asic[48]
    DIRECTION OUTPUT ;
    USE SIGNAL ;
    PORT
      LAYER M7 ;
        RECT 82.805 396.265 82.905 400 ;
    END
  END rdata_asic[48]
  PIN rdata_asic[49]
    DIRECTION OUTPUT ;
    USE SIGNAL ;
    PORT
      LAYER M7 ;
        RECT 83.105 396.265 83.205 400 ;
    END
  END rdata_asic[49]
  PIN rdata_asic[4]
    DIRECTION OUTPUT ;
    USE SIGNAL ;
    PORT
      LAYER M7 ;
        RECT 66.355 396.265 66.455 400 ;
    END
  END rdata_asic[4]
  PIN rdata_asic[50]
    DIRECTION OUTPUT ;
    USE SIGNAL ;
    PORT
      LAYER M7 ;
        RECT 83.405 396.265 83.505 400 ;
    END
  END rdata_asic[50]
  PIN rdata_asic[51]
    DIRECTION OUTPUT ;
    USE SIGNAL ;
    PORT
      LAYER M7 ;
        RECT 83.705 396.265 83.805 400 ;
    END
  END rdata_asic[51]
  PIN rdata_asic[52]
    DIRECTION OUTPUT ;
    USE SIGNAL ;
    PORT
      LAYER M7 ;
        RECT 84.005 396.265 84.105 400 ;
    END
  END rdata_asic[52]
  PIN rdata_asic[53]
    DIRECTION OUTPUT ;
    USE SIGNAL ;
    PORT
      LAYER M7 ;
        RECT 84.305 396.265 84.405 400 ;
    END
  END rdata_asic[53]
  PIN rdata_asic[54]
    DIRECTION OUTPUT ;
    USE SIGNAL ;
    PORT
      LAYER M7 ;
        RECT 84.605 396.265 84.705 400 ;
    END
  END rdata_asic[54]
  PIN rdata_asic[55]
    DIRECTION OUTPUT ;
    USE SIGNAL ;
    PORT
      LAYER M7 ;
        RECT 84.905 396.265 85.005 400 ;
    END
  END rdata_asic[55]
  PIN rdata_asic[56]
    DIRECTION OUTPUT ;
    USE SIGNAL ;
    PORT
      LAYER M7 ;
        RECT 85.205 396.265 85.305 400 ;
    END
  END rdata_asic[56]
  PIN rdata_asic[57]
    DIRECTION OUTPUT ;
    USE SIGNAL ;
    PORT
      LAYER M7 ;
        RECT 85.505 396.265 85.605 400 ;
    END
  END rdata_asic[57]
  PIN rdata_asic[58]
    DIRECTION OUTPUT ;
    USE SIGNAL ;
    PORT
      LAYER M7 ;
        RECT 85.805 396.265 85.905 400 ;
    END
  END rdata_asic[58]
  PIN rdata_asic[59]
    DIRECTION OUTPUT ;
    USE SIGNAL ;
    PORT
      LAYER M7 ;
        RECT 86.105 396.265 86.205 400 ;
    END
  END rdata_asic[59]
  PIN rdata_asic[5]
    DIRECTION OUTPUT ;
    USE SIGNAL ;
    PORT
      LAYER M7 ;
        RECT 66.655 396.265 66.755 400 ;
    END
  END rdata_asic[5]
  PIN rdata_asic[60]
    DIRECTION OUTPUT ;
    USE SIGNAL ;
    PORT
      LAYER M7 ;
        RECT 86.405 396.265 86.505 400 ;
    END
  END rdata_asic[60]
  PIN rdata_asic[61]
    DIRECTION OUTPUT ;
    USE SIGNAL ;
    PORT
      LAYER M7 ;
        RECT 86.705 396.265 86.805 400 ;
    END
  END rdata_asic[61]
  PIN rdata_asic[62]
    DIRECTION OUTPUT ;
    USE SIGNAL ;
    PORT
      LAYER M7 ;
        RECT 87.005 396.265 87.105 400 ;
    END
  END rdata_asic[62]
  PIN rdata_asic[63]
    DIRECTION OUTPUT ;
    USE SIGNAL ;
    PORT
      LAYER M7 ;
        RECT 87.305 396.265 87.405 400 ;
    END
  END rdata_asic[63]
  PIN rdata_asic[64]
    DIRECTION OUTPUT ;
    USE SIGNAL ;
    PORT
      LAYER M7 ;
        RECT 87.605 396.265 87.705 400 ;
    END
  END rdata_asic[64]
  PIN rdata_asic[65]
    DIRECTION OUTPUT ;
    USE SIGNAL ;
    PORT
      LAYER M7 ;
        RECT 87.905 396.265 88.005 400 ;
    END
  END rdata_asic[65]
  PIN rdata_asic[66]
    DIRECTION OUTPUT ;
    USE SIGNAL ;
    PORT
      LAYER M7 ;
        RECT 88.205 396.265 88.305 400 ;
    END
  END rdata_asic[66]
  PIN rdata_asic[67]
    DIRECTION OUTPUT ;
    USE SIGNAL ;
    PORT
      LAYER M7 ;
        RECT 88.505 396.265 88.605 400 ;
    END
  END rdata_asic[67]
  PIN rdata_asic[68]
    DIRECTION OUTPUT ;
    USE SIGNAL ;
    PORT
      LAYER M7 ;
        RECT 92.055 396.265 92.155 400 ;
    END
  END rdata_asic[68]
  PIN rdata_asic[69]
    DIRECTION OUTPUT ;
    USE SIGNAL ;
    PORT
      LAYER M7 ;
        RECT 92.355 396.265 92.455 400 ;
    END
  END rdata_asic[69]
  PIN rdata_asic[6]
    DIRECTION OUTPUT ;
    USE SIGNAL ;
    PORT
      LAYER M7 ;
        RECT 66.955 396.265 67.055 400 ;
    END
  END rdata_asic[6]
  PIN rdata_asic[70]
    DIRECTION OUTPUT ;
    USE SIGNAL ;
    PORT
      LAYER M7 ;
        RECT 92.655 396.265 92.755 400 ;
    END
  END rdata_asic[70]
  PIN rdata_asic[71]
    DIRECTION OUTPUT ;
    USE SIGNAL ;
    PORT
      LAYER M7 ;
        RECT 92.955 396.265 93.055 400 ;
    END
  END rdata_asic[71]
  PIN rdata_asic[72]
    DIRECTION OUTPUT ;
    USE SIGNAL ;
    PORT
      LAYER M7 ;
        RECT 93.255 396.265 93.355 400 ;
    END
  END rdata_asic[72]
  PIN rdata_asic[73]
    DIRECTION OUTPUT ;
    USE SIGNAL ;
    PORT
      LAYER M7 ;
        RECT 93.555 396.265 93.655 400 ;
    END
  END rdata_asic[73]
  PIN rdata_asic[74]
    DIRECTION OUTPUT ;
    USE SIGNAL ;
    PORT
      LAYER M7 ;
        RECT 93.855 396.265 93.955 400 ;
    END
  END rdata_asic[74]
  PIN rdata_asic[75]
    DIRECTION OUTPUT ;
    USE SIGNAL ;
    PORT
      LAYER M7 ;
        RECT 94.155 396.265 94.255 400 ;
    END
  END rdata_asic[75]
  PIN rdata_asic[76]
    DIRECTION OUTPUT ;
    USE SIGNAL ;
    PORT
      LAYER M7 ;
        RECT 94.455 396.265 94.555 400 ;
    END
  END rdata_asic[76]
  PIN rdata_asic[77]
    DIRECTION OUTPUT ;
    USE SIGNAL ;
    PORT
      LAYER M7 ;
        RECT 94.755 396.265 94.855 400 ;
    END
  END rdata_asic[77]
  PIN rdata_asic[78]
    DIRECTION OUTPUT ;
    USE SIGNAL ;
    PORT
      LAYER M7 ;
        RECT 95.055 396.265 95.155 400 ;
    END
  END rdata_asic[78]
  PIN rdata_asic[79]
    DIRECTION OUTPUT ;
    USE SIGNAL ;
    PORT
      LAYER M7 ;
        RECT 95.355 396.265 95.455 400 ;
    END
  END rdata_asic[79]
  PIN rdata_asic[7]
    DIRECTION OUTPUT ;
    USE SIGNAL ;
    PORT
      LAYER M7 ;
        RECT 67.255 396.265 67.355 400 ;
    END
  END rdata_asic[7]
  PIN rdata_asic[80]
    DIRECTION OUTPUT ;
    USE SIGNAL ;
    PORT
      LAYER M7 ;
        RECT 95.655 396.265 95.755 400 ;
    END
  END rdata_asic[80]
  PIN rdata_asic[81]
    DIRECTION OUTPUT ;
    USE SIGNAL ;
    PORT
      LAYER M7 ;
        RECT 95.955 396.265 96.055 400 ;
    END
  END rdata_asic[81]
  PIN rdata_asic[82]
    DIRECTION OUTPUT ;
    USE SIGNAL ;
    PORT
      LAYER M7 ;
        RECT 96.255 396.265 96.355 400 ;
    END
  END rdata_asic[82]
  PIN rdata_asic[83]
    DIRECTION OUTPUT ;
    USE SIGNAL ;
    PORT
      LAYER M7 ;
        RECT 96.555 396.265 96.655 400 ;
    END
  END rdata_asic[83]
  PIN rdata_asic[84]
    DIRECTION OUTPUT ;
    USE SIGNAL ;
    PORT
      LAYER M7 ;
        RECT 96.855 396.265 96.955 400 ;
    END
  END rdata_asic[84]
  PIN rdata_asic[85]
    DIRECTION OUTPUT ;
    USE SIGNAL ;
    PORT
      LAYER M7 ;
        RECT 97.155 396.265 97.255 400 ;
    END
  END rdata_asic[85]
  PIN rdata_asic[86]
    DIRECTION OUTPUT ;
    USE SIGNAL ;
    PORT
      LAYER M7 ;
        RECT 97.455 396.265 97.555 400 ;
    END
  END rdata_asic[86]
  PIN rdata_asic[87]
    DIRECTION OUTPUT ;
    USE SIGNAL ;
    PORT
      LAYER M7 ;
        RECT 97.755 396.265 97.855 400 ;
    END
  END rdata_asic[87]
  PIN rdata_asic[88]
    DIRECTION OUTPUT ;
    USE SIGNAL ;
    PORT
      LAYER M7 ;
        RECT 98.055 396.265 98.155 400 ;
    END
  END rdata_asic[88]
  PIN rdata_asic[89]
    DIRECTION OUTPUT ;
    USE SIGNAL ;
    PORT
      LAYER M7 ;
        RECT 98.355 396.265 98.455 400 ;
    END
  END rdata_asic[89]
  PIN rdata_asic[8]
    DIRECTION OUTPUT ;
    USE SIGNAL ;
    PORT
      LAYER M7 ;
        RECT 67.555 396.265 67.655 400 ;
    END
  END rdata_asic[8]
  PIN rdata_asic[90]
    DIRECTION OUTPUT ;
    USE SIGNAL ;
    PORT
      LAYER M7 ;
        RECT 98.655 396.265 98.755 400 ;
    END
  END rdata_asic[90]
  PIN rdata_asic[91]
    DIRECTION OUTPUT ;
    USE SIGNAL ;
    PORT
      LAYER M7 ;
        RECT 98.955 396.265 99.055 400 ;
    END
  END rdata_asic[91]
  PIN rdata_asic[92]
    DIRECTION OUTPUT ;
    USE SIGNAL ;
    PORT
      LAYER M7 ;
        RECT 99.255 396.265 99.355 400 ;
    END
  END rdata_asic[92]
  PIN rdata_asic[93]
    DIRECTION OUTPUT ;
    USE SIGNAL ;
    PORT
      LAYER M7 ;
        RECT 99.555 396.265 99.655 400 ;
    END
  END rdata_asic[93]
  PIN rdata_asic[94]
    DIRECTION OUTPUT ;
    USE SIGNAL ;
    PORT
      LAYER M7 ;
        RECT 99.855 396.265 99.955 400 ;
    END
  END rdata_asic[94]
  PIN rdata_asic[95]
    DIRECTION OUTPUT ;
    USE SIGNAL ;
    PORT
      LAYER M7 ;
        RECT 100.155 396.265 100.255 400 ;
    END
  END rdata_asic[95]
  PIN rdata_asic[96]
    DIRECTION OUTPUT ;
    USE SIGNAL ;
    PORT
      LAYER M7 ;
        RECT 100.455 396.265 100.555 400 ;
    END
  END rdata_asic[96]
  PIN rdata_asic[97]
    DIRECTION OUTPUT ;
    USE SIGNAL ;
    PORT
      LAYER M7 ;
        RECT 100.755 396.265 100.855 400 ;
    END
  END rdata_asic[97]
  PIN rdata_asic[98]
    DIRECTION OUTPUT ;
    USE SIGNAL ;
    PORT
      LAYER M7 ;
        RECT 101.055 396.265 101.155 400 ;
    END
  END rdata_asic[98]
  PIN rdata_asic[99]
    DIRECTION OUTPUT ;
    USE SIGNAL ;
    PORT
      LAYER M7 ;
        RECT 101.355 396.265 101.455 400 ;
    END
  END rdata_asic[99]
  PIN rdata_asic[9]
    DIRECTION OUTPUT ;
    USE SIGNAL ;
    PORT
      LAYER M7 ;
        RECT 67.855 396.265 67.955 400 ;
    END
  END rdata_asic[9]
  PIN vdd
    DIRECTION INOUT ;
    USE POWER ;
    SHAPE RING ;
    PORT
      LAYER M7 ;
        RECT 63.655 1.98 64.655 400 ;
    END
    PORT
      LAYER M7 ;
        RECT 175.345 1.98 176.345 400 ;
    END
  END vdd
  PIN vdd_array
    DIRECTION INOUT ;
    USE POWER ;
    SHAPE RING ;
    PORT
      LAYER M7 ;
        RECT 77.105 1.98 78.105 400 ;
    END
    PORT
      LAYER M7 ;
        RECT 90.555 1.98 91.555 400 ;
    END
    PORT
      LAYER M7 ;
        RECT 104.005 1.98 105.005 400 ;
    END
    PORT
      LAYER M7 ;
        RECT 117.455 1.98 118.455 400 ;
    END
    PORT
      LAYER M7 ;
        RECT 121.545 1.98 122.545 400 ;
    END
    PORT
      LAYER M7 ;
        RECT 134.995 1.98 135.995 400 ;
    END
    PORT
      LAYER M7 ;
        RECT 148.445 1.98 149.445 400 ;
    END
    PORT
      LAYER M7 ;
        RECT 161.895 1.98 162.895 400 ;
    END
  END vdd_array
  PIN gcadd_asic[7]
    DIRECTION INPUT ;
    USE SIGNAL ;
    PORT
      LAYER M7 ;
        RECT 118.805 398.59 118.905 400 ;
    END
  END gcadd_asic[7]
  PIN gcadd_asic[6]
    DIRECTION INPUT ;
    USE SIGNAL ;
    PORT
      LAYER M7 ;
        RECT 119.105 398.59 119.205 400 ;
    END
  END gcadd_asic[6]
  PIN gcadd_asic[5]
    DIRECTION INPUT ;
    USE SIGNAL ;
    PORT
      LAYER M7 ;
        RECT 119.405 398.59 119.505 400 ;
    END
  END gcadd_asic[5]
  PIN gcadd_asic[4]
    DIRECTION INPUT ;
    USE SIGNAL ;
    PORT
      LAYER M7 ;
        RECT 119.705 398.59 119.805 400 ;
    END
  END gcadd_asic[4]
  PIN gcadd_asic[3]
    DIRECTION INPUT ;
    USE SIGNAL ;
    PORT
      LAYER M7 ;
        RECT 120.005 398.59 120.105 400 ;
    END
  END gcadd_asic[3]
  PIN gcadd_asic[2]
    DIRECTION INPUT ;
    USE SIGNAL ;
    PORT
      LAYER M7 ;
        RECT 120.305 398.59 120.405 400 ;
    END
  END gcadd_asic[2]
  PIN gcadd_asic[1]
    DIRECTION INPUT ;
    USE SIGNAL ;
    PORT
      LAYER M7 ;
        RECT 120.605 398.59 120.705 400 ;
    END
  END gcadd_asic[1]
  PIN gcadd_asic[0]
    DIRECTION INPUT ;
    USE SIGNAL ;
    PORT
      LAYER M7 ;
        RECT 120.905 398.59 121.005 400 ;
    END
  END gcadd_asic[0]
  OBS
    LAYER M1 ;
      RECT 184.5 2.36 240 3.06 ;
      RECT 184.5 3.76 240 4.46 ;
      RECT 184.5 10.38 240 11.08 ;
      RECT 184.5 11.78 240 12.48 ;
      RECT 184.5 13.18 240 13.88 ;
      RECT 184.5 15.06 240 15.76 ;
      RECT 184.5 16.46 240 17.16 ;
      RECT 184.5 23.08 240 23.78 ;
      RECT 184.5 24.48 240 25.18 ;
      RECT 184.5 25.88 240 26.58 ;
      RECT 184.5 27.76 240 28.46 ;
      RECT 184.5 29.16 240 29.86 ;
      RECT 184.5 35.78 240 36.48 ;
      RECT 184.5 37.18 240 37.88 ;
      RECT 184.5 38.58 240 39.28 ;
      RECT 184.5 40.46 240 41.16 ;
      RECT 184.5 41.86 240 42.56 ;
      RECT 184.5 48.48 240 49.18 ;
      RECT 184.5 49.88 240 50.58 ;
      RECT 184.5 51.28 240 51.98 ;
      RECT 184.5 53.16 240 53.86 ;
      RECT 184.5 54.56 240 55.26 ;
      RECT 184.5 61.18 240 61.88 ;
      RECT 184.5 62.58 240 63.28 ;
      RECT 184.5 63.98 240 64.68 ;
      RECT 184.5 65.86 240 66.56 ;
      RECT 184.5 67.26 240 67.96 ;
      RECT 184.5 73.88 240 74.58 ;
      RECT 184.5 75.28 240 75.98 ;
      RECT 184.5 76.68 240 77.38 ;
      RECT 184.5 78.56 240 79.26 ;
      RECT 184.5 79.96 240 80.66 ;
      RECT 184.5 86.58 240 87.28 ;
      RECT 184.5 87.98 240 88.68 ;
      RECT 184.5 89.38 240 90.08 ;
      RECT 184.5 91.26 240 91.96 ;
      RECT 184.5 92.66 240 93.36 ;
      RECT 184.5 99.28 240 99.98 ;
      RECT 184.5 100.68 240 101.38 ;
      RECT 184.5 102.08 240 102.78 ;
      RECT 184.5 103.96 240 104.66 ;
      RECT 184.5 105.36 240 106.06 ;
      RECT 184.5 111.98 240 112.68 ;
      RECT 184.5 113.38 240 114.08 ;
      RECT 184.5 114.78 240 115.48 ;
      RECT 184.5 116.66 240 117.36 ;
      RECT 184.5 118.06 240 118.76 ;
      RECT 184.5 124.68 240 125.38 ;
      RECT 184.5 126.08 240 126.78 ;
      RECT 184.5 127.48 240 128.18 ;
      RECT 184.5 129.36 240 130.06 ;
      RECT 184.5 130.76 240 131.46 ;
      RECT 184.5 137.38 240 138.08 ;
      RECT 184.5 138.78 240 139.48 ;
      RECT 184.5 140.18 240 140.88 ;
      RECT 184.5 142.06 240 142.76 ;
      RECT 184.5 143.46 240 144.16 ;
      RECT 184.5 150.08 240 150.78 ;
      RECT 184.5 151.48 240 152.18 ;
      RECT 184.5 152.88 240 153.58 ;
      RECT 184.5 154.76 240 155.46 ;
      RECT 184.5 156.16 240 156.86 ;
      RECT 184.5 162.78 240 163.48 ;
      RECT 184.5 164.18 240 164.88 ;
      RECT 184.5 165.58 240 166.28 ;
      RECT 184.5 167.46 240 168.16 ;
      RECT 184.5 168.86 240 169.56 ;
      RECT 184.5 175.48 240 176.18 ;
      RECT 184.5 176.88 240 177.58 ;
      RECT 184.5 178.28 240 178.98 ;
      RECT 184.5 221.585 240 222.285 ;
      RECT 184.5 222.985 240 223.685 ;
      RECT 184.5 229.605 240 230.305 ;
      RECT 184.5 231.005 240 231.705 ;
      RECT 184.5 232.405 240 233.105 ;
      RECT 184.5 234.285 240 234.985 ;
      RECT 184.5 235.685 240 236.385 ;
      RECT 184.5 242.305 240 243.005 ;
      RECT 184.5 243.705 240 244.405 ;
      RECT 184.5 245.105 240 245.805 ;
      RECT 184.5 246.985 240 247.685 ;
      RECT 184.5 248.385 240 249.085 ;
      RECT 184.5 255.005 240 255.705 ;
      RECT 184.5 256.405 240 257.105 ;
      RECT 184.5 257.805 240 258.505 ;
      RECT 184.5 259.685 240 260.385 ;
      RECT 184.5 261.085 240 261.785 ;
      RECT 184.5 267.705 240 268.405 ;
      RECT 184.5 269.105 240 269.805 ;
      RECT 184.5 270.505 240 271.205 ;
      RECT 184.5 272.385 240 273.085 ;
      RECT 184.5 273.785 240 274.485 ;
      RECT 184.5 280.405 240 281.105 ;
      RECT 184.5 281.805 240 282.505 ;
      RECT 184.5 283.205 240 283.905 ;
      RECT 184.5 285.085 240 285.785 ;
      RECT 184.5 286.485 240 287.185 ;
      RECT 184.5 293.105 240 293.805 ;
      RECT 184.5 294.505 240 295.205 ;
      RECT 184.5 295.905 240 296.605 ;
      RECT 184.5 297.785 240 298.485 ;
      RECT 184.5 299.185 240 299.885 ;
      RECT 184.5 305.805 240 306.505 ;
      RECT 184.5 307.205 240 307.905 ;
      RECT 184.5 308.605 240 309.305 ;
      RECT 184.5 310.485 240 311.185 ;
      RECT 184.5 311.885 240 312.585 ;
      RECT 184.5 318.505 240 319.205 ;
      RECT 184.5 319.905 240 320.605 ;
      RECT 184.5 321.305 240 322.005 ;
      RECT 184.5 323.185 240 323.885 ;
      RECT 184.5 324.585 240 325.285 ;
      RECT 184.5 331.205 240 331.905 ;
      RECT 184.5 332.605 240 333.305 ;
      RECT 184.5 334.005 240 334.705 ;
      RECT 184.5 335.885 240 336.585 ;
      RECT 184.5 337.285 240 337.985 ;
      RECT 184.5 343.905 240 344.605 ;
      RECT 184.5 345.305 240 346.005 ;
      RECT 184.5 346.705 240 347.405 ;
      RECT 184.5 348.585 240 349.285 ;
      RECT 184.5 349.985 240 350.685 ;
      RECT 184.5 356.605 240 357.305 ;
      RECT 184.5 358.005 240 358.705 ;
      RECT 184.5 359.405 240 360.105 ;
      RECT 184.5 361.285 240 361.985 ;
      RECT 184.5 362.685 240 363.385 ;
      RECT 184.5 369.305 240 370.005 ;
      RECT 184.5 370.705 240 371.405 ;
      RECT 184.5 372.105 240 372.805 ;
      RECT 184.5 373.985 240 374.685 ;
      RECT 184.5 375.385 240 376.085 ;
      RECT 184.5 382.005 240 382.705 ;
      RECT 184.5 383.405 240 384.105 ;
      RECT 184.5 384.805 240 385.505 ;
      RECT 184.5 386.685 240 387.385 ;
      RECT 184.5 388.085 240 388.785 ;
      RECT 184.5 394.705 240 395.405 ;
      RECT 184.5 396.105 240 396.805 ;
      RECT 184.5 397.505 240 398.205 ;
      RECT 0 2.36 55.5 3.06 ;
      RECT 0 3.76 55.5 4.46 ;
      RECT 0 10.38 55.5 11.08 ;
      RECT 0 11.78 55.5 12.48 ;
      RECT 0 13.18 55.5 13.88 ;
      RECT 0 15.06 55.5 15.76 ;
      RECT 0 16.46 55.5 17.16 ;
      RECT 0 23.08 55.5 23.78 ;
      RECT 0 24.48 55.5 25.18 ;
      RECT 0 25.88 55.5 26.58 ;
      RECT 0 27.76 55.5 28.46 ;
      RECT 0 29.16 55.5 29.86 ;
      RECT 0 35.78 55.5 36.48 ;
      RECT 0 37.18 55.5 37.88 ;
      RECT 0 38.58 55.5 39.28 ;
      RECT 0 40.46 55.5 41.16 ;
      RECT 0 41.86 55.5 42.56 ;
      RECT 0 48.48 55.5 49.18 ;
      RECT 0 49.88 55.5 50.58 ;
      RECT 0 51.28 55.5 51.98 ;
      RECT 0 53.16 55.5 53.86 ;
      RECT 0 54.56 55.5 55.26 ;
      RECT 0 61.18 55.5 61.88 ;
      RECT 0 62.58 55.5 63.28 ;
      RECT 0 63.98 55.5 64.68 ;
      RECT 0 65.86 55.5 66.56 ;
      RECT 0 67.26 55.5 67.96 ;
      RECT 0 73.88 55.5 74.58 ;
      RECT 0 75.28 55.5 75.98 ;
      RECT 0 76.68 55.5 77.38 ;
      RECT 0 78.56 55.5 79.26 ;
      RECT 0 79.96 55.5 80.66 ;
      RECT 0 86.58 55.5 87.28 ;
      RECT 0 87.98 55.5 88.68 ;
      RECT 0 89.38 55.5 90.08 ;
      RECT 0 91.26 55.5 91.96 ;
      RECT 0 92.66 55.5 93.36 ;
      RECT 0 99.28 55.5 99.98 ;
      RECT 0 100.68 55.5 101.38 ;
      RECT 0 102.08 55.5 102.78 ;
      RECT 0 103.96 55.5 104.66 ;
      RECT 0 105.36 55.5 106.06 ;
      RECT 0 111.98 55.5 112.68 ;
      RECT 0 113.38 55.5 114.08 ;
      RECT 0 114.78 55.5 115.48 ;
      RECT 0 116.66 55.5 117.36 ;
      RECT 0 118.06 55.5 118.76 ;
      RECT 0 124.68 55.5 125.38 ;
      RECT 0 126.08 55.5 126.78 ;
      RECT 0 127.48 55.5 128.18 ;
      RECT 0 129.36 55.5 130.06 ;
      RECT 0 130.76 55.5 131.46 ;
      RECT 0 137.38 55.5 138.08 ;
      RECT 0 138.78 55.5 139.48 ;
      RECT 0 140.18 55.5 140.88 ;
      RECT 0 142.06 55.5 142.76 ;
      RECT 0 143.46 55.5 144.16 ;
      RECT 0 150.08 55.5 150.78 ;
      RECT 0 151.48 55.5 152.18 ;
      RECT 0 152.88 55.5 153.58 ;
      RECT 0 154.76 55.5 155.46 ;
      RECT 0 156.16 55.5 156.86 ;
      RECT 0 162.78 55.5 163.48 ;
      RECT 0 164.18 55.5 164.88 ;
      RECT 0 165.58 55.5 166.28 ;
      RECT 0 167.46 55.5 168.16 ;
      RECT 0 168.86 55.5 169.56 ;
      RECT 0 175.48 55.5 176.18 ;
      RECT 0 176.88 55.5 177.58 ;
      RECT 0 178.28 55.5 178.98 ;
      RECT 0 221.585 55.5 222.285 ;
      RECT 0 222.985 55.5 223.685 ;
      RECT 0 229.605 55.5 230.305 ;
      RECT 0 231.005 55.5 231.705 ;
      RECT 0 232.405 55.5 233.105 ;
      RECT 0 234.285 55.5 234.985 ;
      RECT 0 235.685 55.5 236.385 ;
      RECT 0 242.305 55.5 243.005 ;
      RECT 0 243.705 55.5 244.405 ;
      RECT 0 245.105 55.5 245.805 ;
      RECT 0 246.985 55.5 247.685 ;
      RECT 0 248.385 55.5 249.085 ;
      RECT 0 255.005 55.5 255.705 ;
      RECT 0 256.405 55.5 257.105 ;
      RECT 0 257.805 55.5 258.505 ;
      RECT 0 259.685 55.5 260.385 ;
      RECT 0 261.085 55.5 261.785 ;
      RECT 0 267.705 55.5 268.405 ;
      RECT 0 269.105 55.5 269.805 ;
      RECT 0 270.505 55.5 271.205 ;
      RECT 0 272.385 55.5 273.085 ;
      RECT 0 273.785 55.5 274.485 ;
      RECT 0 280.405 55.5 281.105 ;
      RECT 0 281.805 55.5 282.505 ;
      RECT 0 283.205 55.5 283.905 ;
      RECT 0 285.085 55.5 285.785 ;
      RECT 0 286.485 55.5 287.185 ;
      RECT 0 293.105 55.5 293.805 ;
      RECT 0 294.505 55.5 295.205 ;
      RECT 0 295.905 55.5 296.605 ;
      RECT 0 297.785 55.5 298.485 ;
      RECT 0 299.185 55.5 299.885 ;
      RECT 0 305.805 55.5 306.505 ;
      RECT 0 307.205 55.5 307.905 ;
      RECT 0 308.605 55.5 309.305 ;
      RECT 0 310.485 55.5 311.185 ;
      RECT 0 311.885 55.5 312.585 ;
      RECT 0 318.505 55.5 319.205 ;
      RECT 0 319.905 55.5 320.605 ;
      RECT 0 321.305 55.5 322.005 ;
      RECT 0 323.185 55.5 323.885 ;
      RECT 0 324.585 55.5 325.285 ;
      RECT 0 331.205 55.5 331.905 ;
      RECT 0 332.605 55.5 333.305 ;
      RECT 0 334.005 55.5 334.705 ;
      RECT 0 335.885 55.5 336.585 ;
      RECT 0 337.285 55.5 337.985 ;
      RECT 0 343.905 55.5 344.605 ;
      RECT 0 345.305 55.5 346.005 ;
      RECT 0 346.705 55.5 347.405 ;
      RECT 0 348.585 55.5 349.285 ;
      RECT 0 349.985 55.5 350.685 ;
      RECT 0 356.605 55.5 357.305 ;
      RECT 0 358.005 55.5 358.705 ;
      RECT 0 359.405 55.5 360.105 ;
      RECT 0 361.285 55.5 361.985 ;
      RECT 0 362.685 55.5 363.385 ;
      RECT 0 369.305 55.5 370.005 ;
      RECT 0 370.705 55.5 371.405 ;
      RECT 0 372.105 55.5 372.805 ;
      RECT 0 373.985 55.5 374.685 ;
      RECT 0 375.385 55.5 376.085 ;
      RECT 0 382.005 55.5 382.705 ;
      RECT 0 383.405 55.5 384.105 ;
      RECT 0 384.805 55.5 385.505 ;
      RECT 0 386.685 55.5 387.385 ;
      RECT 0 388.085 55.5 388.785 ;
      RECT 0 394.705 55.5 395.405 ;
      RECT 0 396.105 55.5 396.805 ;
      RECT 0 397.505 55.5 398.205 ;
    LAYER M1 SPACING 0.05 ;
      RECT 0 393.91 240 400 ;
      RECT 239.435 0 240 400 ;
      RECT 228.315 0 229.545 400 ;
      RECT 217.195 0 218.425 400 ;
      RECT 206.075 0 207.305 400 ;
      RECT 194.955 0 196.185 400 ;
      RECT 54.935 0 185.065 400 ;
      RECT 43.815 0 45.045 400 ;
      RECT 32.695 0 33.925 400 ;
      RECT 21.575 0 22.805 400 ;
      RECT 10.455 0 11.685 400 ;
      RECT 0 0 0.565 400 ;
      RECT 0 381.21 240 389.58 ;
      RECT 0 368.51 240 376.88 ;
      RECT 0 355.81 240 364.18 ;
      RECT 0 343.11 240 351.48 ;
      RECT 0 330.41 240 338.78 ;
      RECT 0 317.71 240 326.08 ;
      RECT 0 305.01 240 313.38 ;
      RECT 0 292.31 240 300.68 ;
      RECT 0 279.61 240 287.98 ;
      RECT 0 266.91 240 275.28 ;
      RECT 0 254.21 240 262.58 ;
      RECT 0 241.51 240 249.88 ;
      RECT 0 228.81 240 237.18 ;
      RECT 217.195 214.445 240 237.18 ;
      RECT 0 214.445 22.805 237.18 ;
      RECT 0 214.445 240 224.48 ;
      RECT 0 202.165 240 210.115 ;
      RECT 0 189.885 240 197.835 ;
      RECT 0 174.685 240 185.555 ;
      RECT 217.195 161.985 240 185.555 ;
      RECT 0 161.985 22.805 185.555 ;
      RECT 0 161.985 240 170.355 ;
      RECT 0 149.285 240 157.655 ;
      RECT 0 136.585 240 144.955 ;
      RECT 0 123.885 240 132.255 ;
      RECT 0 111.185 240 119.555 ;
      RECT 0 98.485 240 106.855 ;
      RECT 0 85.785 240 94.155 ;
      RECT 0 73.085 240 81.455 ;
      RECT 0 60.385 240 68.755 ;
      RECT 0 47.685 240 56.055 ;
      RECT 0 34.985 240 43.355 ;
      RECT 0 22.285 240 30.655 ;
      RECT 0 9.585 240 17.955 ;
      RECT 0 0 240 5.255 ;
    LAYER M3 SPACING 0.05 ;
      RECT 115.61 0 240 400 ;
      RECT 0 0 106 400 ;
      RECT 0 0 240 398.485 ;
    LAYER M5 ;
      RECT 176.645 1.98 177.645 400 ;
      RECT 175.345 1.98 176.345 400 ;
      RECT 174.595 396.265 174.695 398.56 ;
      RECT 174.295 396.265 174.395 398.56 ;
      RECT 173.995 396.265 174.095 398.56 ;
      RECT 173.695 396.265 173.795 398.56 ;
      RECT 173.395 396.265 173.495 398.56 ;
      RECT 173.095 396.265 173.195 398.56 ;
      RECT 172.795 396.265 172.895 398.56 ;
      RECT 172.495 396.265 172.595 398.56 ;
      RECT 172.195 396.265 172.295 398.56 ;
      RECT 171.895 396.265 171.995 398.56 ;
      RECT 171.595 396.265 171.695 398.56 ;
      RECT 171.295 396.265 171.395 398.56 ;
      RECT 170.995 396.265 171.095 398.56 ;
      RECT 170.695 396.265 170.795 398.56 ;
      RECT 170.395 396.265 170.495 398.56 ;
      RECT 170.095 396.265 170.195 398.56 ;
      RECT 169.795 396.265 169.895 398.56 ;
      RECT 169.495 396.265 169.595 398.56 ;
      RECT 169.195 396.265 169.295 398.56 ;
      RECT 168.895 396.265 168.995 398.56 ;
      RECT 168.595 396.265 168.695 398.56 ;
      RECT 168.295 396.265 168.395 398.56 ;
      RECT 167.995 396.265 168.095 398.56 ;
      RECT 167.695 396.265 167.795 398.56 ;
      RECT 167.395 396.265 167.495 398.56 ;
      RECT 167.095 396.265 167.195 398.56 ;
      RECT 166.795 396.265 166.895 398.56 ;
      RECT 166.495 396.265 166.595 398.56 ;
      RECT 166.195 396.265 166.295 398.56 ;
      RECT 165.895 396.265 165.995 398.56 ;
      RECT 165.595 396.265 165.695 398.56 ;
      RECT 165.295 396.265 165.395 398.56 ;
      RECT 164.995 396.265 165.095 398.56 ;
      RECT 164.695 396.265 164.795 398.56 ;
      RECT 163.195 1.98 164.195 400 ;
      RECT 161.895 1.98 162.895 400 ;
      RECT 161.145 396.265 161.245 398.56 ;
      RECT 160.845 396.265 160.945 398.56 ;
      RECT 160.545 396.265 160.645 398.56 ;
      RECT 160.245 396.265 160.345 398.56 ;
      RECT 159.945 396.265 160.045 398.56 ;
      RECT 159.645 396.265 159.745 398.56 ;
      RECT 159.345 396.265 159.445 398.56 ;
      RECT 159.045 396.265 159.145 398.56 ;
      RECT 158.745 396.265 158.845 398.56 ;
      RECT 158.445 396.265 158.545 398.56 ;
      RECT 158.145 396.265 158.245 398.56 ;
      RECT 157.845 396.265 157.945 398.56 ;
      RECT 157.545 396.265 157.645 398.56 ;
      RECT 157.245 396.265 157.345 398.56 ;
      RECT 156.945 396.265 157.045 398.56 ;
      RECT 156.645 396.265 156.745 398.56 ;
      RECT 156.345 396.265 156.445 398.56 ;
      RECT 156.045 396.265 156.145 398.56 ;
      RECT 155.745 396.265 155.845 398.56 ;
      RECT 155.445 396.265 155.545 398.56 ;
      RECT 155.145 396.265 155.245 398.56 ;
      RECT 154.845 396.265 154.945 398.56 ;
      RECT 154.545 396.265 154.645 398.56 ;
      RECT 154.245 396.265 154.345 398.56 ;
      RECT 153.945 396.265 154.045 398.56 ;
      RECT 153.645 396.265 153.745 398.56 ;
      RECT 153.345 396.265 153.445 398.56 ;
      RECT 153.045 396.265 153.145 398.56 ;
      RECT 152.745 396.265 152.845 398.56 ;
      RECT 152.445 396.265 152.545 398.56 ;
      RECT 152.145 396.265 152.245 398.56 ;
      RECT 151.845 396.265 151.945 398.56 ;
      RECT 151.545 396.265 151.645 398.56 ;
      RECT 151.245 396.265 151.345 398.56 ;
      RECT 149.745 1.98 150.745 400 ;
      RECT 148.445 1.98 149.445 400 ;
      RECT 147.395 2.015 147.495 6.555 ;
      RECT 147.395 6.97 147.495 11.51 ;
      RECT 147.395 11.94 147.495 14.235 ;
      RECT 147.395 14.715 147.495 19.255 ;
      RECT 147.395 19.67 147.495 24.21 ;
      RECT 147.395 24.64 147.495 26.935 ;
      RECT 147.395 27.415 147.495 31.955 ;
      RECT 147.395 32.37 147.495 36.91 ;
      RECT 147.395 37.34 147.495 39.635 ;
      RECT 147.395 40.115 147.495 44.655 ;
      RECT 147.395 45.07 147.495 49.61 ;
      RECT 147.395 50.04 147.495 52.335 ;
      RECT 147.395 52.815 147.495 57.355 ;
      RECT 147.395 57.77 147.495 62.31 ;
      RECT 147.395 62.74 147.495 65.035 ;
      RECT 147.395 65.515 147.495 70.055 ;
      RECT 147.395 70.47 147.495 75.01 ;
      RECT 147.395 75.44 147.495 77.735 ;
      RECT 147.395 78.215 147.495 82.755 ;
      RECT 147.395 83.17 147.495 87.71 ;
      RECT 147.395 88.14 147.495 90.435 ;
      RECT 147.395 90.915 147.495 95.455 ;
      RECT 147.395 95.87 147.495 100.41 ;
      RECT 147.395 100.84 147.495 103.135 ;
      RECT 147.395 103.615 147.495 108.155 ;
      RECT 147.395 108.57 147.495 113.11 ;
      RECT 147.395 113.54 147.495 115.835 ;
      RECT 147.395 116.315 147.495 120.855 ;
      RECT 147.395 121.27 147.495 125.81 ;
      RECT 147.395 126.24 147.495 128.535 ;
      RECT 147.395 129.015 147.495 133.555 ;
      RECT 147.395 133.97 147.495 138.51 ;
      RECT 147.395 138.94 147.495 141.235 ;
      RECT 147.395 141.715 147.495 146.255 ;
      RECT 147.395 146.67 147.495 151.21 ;
      RECT 147.395 151.64 147.495 153.935 ;
      RECT 147.395 154.415 147.495 158.955 ;
      RECT 147.395 159.37 147.495 163.91 ;
      RECT 147.395 164.34 147.495 166.635 ;
      RECT 147.395 167.115 147.495 171.655 ;
      RECT 147.395 172.07 147.495 176.61 ;
      RECT 147.395 177.04 147.495 179.335 ;
      RECT 147.395 221.24 147.495 225.78 ;
      RECT 147.395 226.195 147.495 230.735 ;
      RECT 147.395 231.165 147.495 233.46 ;
      RECT 147.395 233.94 147.495 238.48 ;
      RECT 147.395 238.895 147.495 243.435 ;
      RECT 147.395 243.865 147.495 246.16 ;
      RECT 147.395 246.64 147.495 251.18 ;
      RECT 147.395 251.595 147.495 256.135 ;
      RECT 147.395 256.565 147.495 258.86 ;
      RECT 147.395 259.34 147.495 263.88 ;
      RECT 147.395 264.295 147.495 268.835 ;
      RECT 147.395 269.265 147.495 271.56 ;
      RECT 147.395 272.04 147.495 276.58 ;
      RECT 147.395 276.995 147.495 281.535 ;
      RECT 147.395 281.965 147.495 284.26 ;
      RECT 147.395 284.74 147.495 289.28 ;
      RECT 147.395 289.695 147.495 294.235 ;
      RECT 147.395 294.665 147.495 296.96 ;
      RECT 147.395 297.44 147.495 301.98 ;
      RECT 147.395 302.395 147.495 306.935 ;
      RECT 147.395 307.365 147.495 309.66 ;
      RECT 147.395 310.14 147.495 314.68 ;
      RECT 147.395 315.095 147.495 319.635 ;
      RECT 147.395 320.065 147.495 322.36 ;
      RECT 147.395 322.84 147.495 327.38 ;
      RECT 147.395 327.795 147.495 332.335 ;
      RECT 147.395 332.765 147.495 335.06 ;
      RECT 147.395 335.54 147.495 340.08 ;
      RECT 147.395 340.495 147.495 345.035 ;
      RECT 147.395 345.465 147.495 347.76 ;
      RECT 147.395 348.24 147.495 352.78 ;
      RECT 147.395 353.195 147.495 357.735 ;
      RECT 147.395 358.165 147.495 360.46 ;
      RECT 147.395 360.94 147.495 365.48 ;
      RECT 147.395 365.895 147.495 370.435 ;
      RECT 147.395 370.865 147.495 373.16 ;
      RECT 147.395 373.64 147.495 378.18 ;
      RECT 147.395 378.595 147.495 383.135 ;
      RECT 147.395 383.565 147.495 385.86 ;
      RECT 147.395 386.34 147.495 390.88 ;
      RECT 147.395 391.295 147.495 395.835 ;
      RECT 147.395 396.265 147.495 398.56 ;
      RECT 147.095 2.015 147.195 6.555 ;
      RECT 147.095 6.97 147.195 11.51 ;
      RECT 147.095 11.94 147.195 14.235 ;
      RECT 147.095 14.715 147.195 19.255 ;
      RECT 147.095 19.67 147.195 24.21 ;
      RECT 147.095 24.64 147.195 26.935 ;
      RECT 147.095 27.415 147.195 31.955 ;
      RECT 147.095 32.37 147.195 36.91 ;
      RECT 147.095 37.34 147.195 39.635 ;
      RECT 147.095 40.115 147.195 44.655 ;
      RECT 147.095 45.07 147.195 49.61 ;
      RECT 147.095 50.04 147.195 52.335 ;
      RECT 147.095 52.815 147.195 57.355 ;
      RECT 147.095 57.77 147.195 62.31 ;
      RECT 147.095 62.74 147.195 65.035 ;
      RECT 147.095 65.515 147.195 70.055 ;
      RECT 147.095 70.47 147.195 75.01 ;
      RECT 147.095 75.44 147.195 77.735 ;
      RECT 147.095 78.215 147.195 82.755 ;
      RECT 147.095 83.17 147.195 87.71 ;
      RECT 147.095 88.14 147.195 90.435 ;
      RECT 147.095 90.915 147.195 95.455 ;
      RECT 147.095 95.87 147.195 100.41 ;
      RECT 147.095 100.84 147.195 103.135 ;
      RECT 147.095 103.615 147.195 108.155 ;
      RECT 147.095 108.57 147.195 113.11 ;
      RECT 147.095 113.54 147.195 115.835 ;
      RECT 147.095 116.315 147.195 120.855 ;
      RECT 147.095 121.27 147.195 125.81 ;
      RECT 147.095 126.24 147.195 128.535 ;
      RECT 147.095 129.015 147.195 133.555 ;
      RECT 147.095 133.97 147.195 138.51 ;
      RECT 147.095 138.94 147.195 141.235 ;
      RECT 147.095 141.715 147.195 146.255 ;
      RECT 147.095 146.67 147.195 151.21 ;
      RECT 147.095 151.64 147.195 153.935 ;
      RECT 147.095 154.415 147.195 158.955 ;
      RECT 147.095 159.37 147.195 163.91 ;
      RECT 147.095 164.34 147.195 166.635 ;
      RECT 147.095 167.115 147.195 171.655 ;
      RECT 147.095 172.07 147.195 176.61 ;
      RECT 147.095 177.04 147.195 179.335 ;
      RECT 147.095 221.24 147.195 225.78 ;
      RECT 147.095 226.195 147.195 230.735 ;
      RECT 147.095 231.165 147.195 233.46 ;
      RECT 147.095 233.94 147.195 238.48 ;
      RECT 147.095 238.895 147.195 243.435 ;
      RECT 147.095 243.865 147.195 246.16 ;
      RECT 147.095 246.64 147.195 251.18 ;
      RECT 147.095 251.595 147.195 256.135 ;
      RECT 147.095 256.565 147.195 258.86 ;
      RECT 147.095 259.34 147.195 263.88 ;
      RECT 147.095 264.295 147.195 268.835 ;
      RECT 147.095 269.265 147.195 271.56 ;
      RECT 147.095 272.04 147.195 276.58 ;
      RECT 147.095 276.995 147.195 281.535 ;
      RECT 147.095 281.965 147.195 284.26 ;
      RECT 147.095 284.74 147.195 289.28 ;
      RECT 147.095 289.695 147.195 294.235 ;
      RECT 147.095 294.665 147.195 296.96 ;
      RECT 147.095 297.44 147.195 301.98 ;
      RECT 147.095 302.395 147.195 306.935 ;
      RECT 147.095 307.365 147.195 309.66 ;
      RECT 147.095 310.14 147.195 314.68 ;
      RECT 147.095 315.095 147.195 319.635 ;
      RECT 147.095 320.065 147.195 322.36 ;
      RECT 147.095 322.84 147.195 327.38 ;
      RECT 147.095 327.795 147.195 332.335 ;
      RECT 147.095 332.765 147.195 335.06 ;
      RECT 147.095 335.54 147.195 340.08 ;
      RECT 147.095 340.495 147.195 345.035 ;
      RECT 147.095 345.465 147.195 347.76 ;
      RECT 147.095 348.24 147.195 352.78 ;
      RECT 147.095 353.195 147.195 357.735 ;
      RECT 147.095 358.165 147.195 360.46 ;
      RECT 147.095 360.94 147.195 365.48 ;
      RECT 147.095 365.895 147.195 370.435 ;
      RECT 147.095 370.865 147.195 373.16 ;
      RECT 147.095 373.64 147.195 378.18 ;
      RECT 147.095 378.595 147.195 383.135 ;
      RECT 147.095 383.565 147.195 385.86 ;
      RECT 147.095 386.34 147.195 390.88 ;
      RECT 147.095 391.295 147.195 395.835 ;
      RECT 147.095 396.265 147.195 398.56 ;
      RECT 146.795 396.265 146.895 398.56 ;
      RECT 146.495 396.265 146.595 398.56 ;
      RECT 146.195 396.265 146.295 398.56 ;
      RECT 145.895 396.265 145.995 398.56 ;
      RECT 145.595 396.265 145.695 398.56 ;
      RECT 145.295 396.265 145.395 398.56 ;
      RECT 144.995 396.265 145.095 398.56 ;
      RECT 144.695 396.265 144.795 398.56 ;
      RECT 144.395 396.265 144.495 398.56 ;
      RECT 144.095 396.265 144.195 398.56 ;
      RECT 143.795 396.265 143.895 398.56 ;
      RECT 143.495 396.265 143.595 398.56 ;
      RECT 143.195 396.265 143.295 398.56 ;
      RECT 142.895 396.265 142.995 398.56 ;
      RECT 142.595 396.265 142.695 398.56 ;
      RECT 142.295 396.265 142.395 398.56 ;
      RECT 141.995 396.265 142.095 398.56 ;
      RECT 141.695 396.265 141.795 398.56 ;
      RECT 141.395 396.265 141.495 398.56 ;
      RECT 141.095 396.265 141.195 398.56 ;
      RECT 140.795 396.265 140.895 398.56 ;
      RECT 140.495 396.265 140.595 398.56 ;
      RECT 140.195 396.265 140.295 398.56 ;
      RECT 139.895 396.265 139.995 398.56 ;
      RECT 139.595 396.265 139.695 398.56 ;
      RECT 139.295 396.265 139.395 398.56 ;
      RECT 138.995 396.265 139.095 398.56 ;
      RECT 138.695 396.265 138.795 398.56 ;
      RECT 138.395 396.265 138.495 398.56 ;
      RECT 138.095 396.265 138.195 398.56 ;
      RECT 137.795 396.265 137.895 398.56 ;
      RECT 136.295 1.98 137.295 400 ;
      RECT 134.995 1.98 135.995 400 ;
      RECT 134.245 396.265 134.345 398.56 ;
      RECT 133.945 396.265 134.045 398.56 ;
      RECT 133.645 396.265 133.745 398.56 ;
      RECT 133.345 396.265 133.445 398.56 ;
      RECT 133.045 396.265 133.145 398.56 ;
      RECT 132.745 396.265 132.845 398.56 ;
      RECT 132.445 396.265 132.545 398.56 ;
      RECT 132.145 396.265 132.245 398.56 ;
      RECT 131.845 396.265 131.945 398.56 ;
      RECT 131.545 396.265 131.645 398.56 ;
      RECT 131.245 396.265 131.345 398.56 ;
      RECT 130.945 396.265 131.045 398.56 ;
      RECT 130.645 396.265 130.745 398.56 ;
      RECT 130.345 396.265 130.445 398.56 ;
      RECT 130.045 396.265 130.145 398.56 ;
      RECT 129.745 396.265 129.845 398.56 ;
      RECT 129.445 396.265 129.545 398.56 ;
      RECT 129.145 396.265 129.245 398.56 ;
      RECT 128.845 396.265 128.945 398.56 ;
      RECT 128.545 396.265 128.645 398.56 ;
      RECT 128.245 396.265 128.345 398.56 ;
      RECT 127.945 396.265 128.045 398.56 ;
      RECT 127.645 396.265 127.745 398.56 ;
      RECT 127.345 396.265 127.445 398.56 ;
      RECT 127.045 396.265 127.145 398.56 ;
      RECT 126.745 396.265 126.845 398.56 ;
      RECT 126.445 396.265 126.545 398.56 ;
      RECT 126.145 396.265 126.245 398.56 ;
      RECT 125.845 396.265 125.945 398.56 ;
      RECT 125.545 396.265 125.645 398.56 ;
      RECT 125.245 396.265 125.345 398.56 ;
      RECT 124.945 396.265 125.045 398.56 ;
      RECT 124.645 396.265 124.745 398.56 ;
      RECT 124.345 396.265 124.445 398.56 ;
      RECT 122.845 1.98 123.845 400 ;
      RECT 121.545 1.98 122.545 400 ;
      RECT 117.455 1.98 118.455 400 ;
      RECT 116.155 1.98 117.155 400 ;
      RECT 115.555 396.265 115.655 398.56 ;
      RECT 115.255 396.265 115.355 398.56 ;
      RECT 114.955 396.265 115.055 398.56 ;
      RECT 114.655 396.265 114.755 398.56 ;
      RECT 114.355 396.265 114.455 398.56 ;
      RECT 114.055 396.265 114.155 398.56 ;
      RECT 113.755 396.265 113.855 398.56 ;
      RECT 113.455 396.265 113.555 398.56 ;
      RECT 113.155 396.265 113.255 398.56 ;
      RECT 112.855 396.265 112.955 398.56 ;
      RECT 112.555 396.265 112.655 398.56 ;
      RECT 112.255 396.265 112.355 398.56 ;
      RECT 111.955 396.265 112.055 398.56 ;
      RECT 111.655 396.265 111.755 398.56 ;
      RECT 111.355 396.265 111.455 398.56 ;
      RECT 111.055 396.265 111.155 398.56 ;
      RECT 110.755 396.265 110.855 398.56 ;
      RECT 110.455 396.265 110.555 398.56 ;
      RECT 110.155 396.265 110.255 398.56 ;
      RECT 109.855 396.265 109.955 398.56 ;
      RECT 109.555 396.265 109.655 398.56 ;
      RECT 109.255 396.265 109.355 398.56 ;
      RECT 108.955 396.265 109.055 398.56 ;
      RECT 108.655 396.265 108.755 398.56 ;
      RECT 108.355 396.265 108.455 398.56 ;
      RECT 108.055 396.265 108.155 398.56 ;
      RECT 107.755 396.265 107.855 398.56 ;
      RECT 107.455 396.265 107.555 398.56 ;
      RECT 107.155 396.265 107.255 398.56 ;
      RECT 106.855 396.265 106.955 398.56 ;
      RECT 106.555 396.265 106.655 398.56 ;
      RECT 106.255 396.265 106.355 398.56 ;
      RECT 105.955 396.265 106.055 398.56 ;
      RECT 105.655 396.265 105.755 398.56 ;
      RECT 104.005 1.98 105.005 400 ;
      RECT 102.705 1.98 103.705 400 ;
      RECT 102.105 396.265 102.205 398.56 ;
      RECT 101.805 396.265 101.905 398.56 ;
      RECT 101.505 396.265 101.605 398.56 ;
      RECT 101.205 396.265 101.305 398.56 ;
      RECT 100.905 396.265 101.005 398.56 ;
      RECT 100.605 396.265 100.705 398.56 ;
      RECT 100.305 396.265 100.405 398.56 ;
      RECT 100.005 396.265 100.105 398.56 ;
      RECT 99.705 396.265 99.805 398.56 ;
      RECT 99.405 396.265 99.505 398.56 ;
      RECT 99.105 396.265 99.205 398.56 ;
      RECT 98.805 396.265 98.905 398.56 ;
      RECT 98.505 396.265 98.605 398.56 ;
      RECT 98.205 396.265 98.305 398.56 ;
      RECT 97.905 396.265 98.005 398.56 ;
      RECT 97.605 396.265 97.705 398.56 ;
      RECT 97.305 396.265 97.405 398.56 ;
      RECT 97.005 396.265 97.105 398.56 ;
      RECT 96.705 396.265 96.805 398.56 ;
      RECT 96.405 396.265 96.505 398.56 ;
      RECT 96.105 396.265 96.205 398.56 ;
      RECT 95.805 396.265 95.905 398.56 ;
      RECT 95.505 396.265 95.605 398.56 ;
      RECT 95.205 396.265 95.305 398.56 ;
      RECT 94.905 396.265 95.005 398.56 ;
      RECT 94.605 396.265 94.705 398.56 ;
      RECT 94.305 396.265 94.405 398.56 ;
      RECT 94.005 396.265 94.105 398.56 ;
      RECT 93.705 396.265 93.805 398.56 ;
      RECT 93.405 396.265 93.505 398.56 ;
      RECT 93.105 396.265 93.205 398.56 ;
      RECT 92.805 2.015 92.905 6.555 ;
      RECT 92.805 6.97 92.905 11.51 ;
      RECT 92.805 11.94 92.905 14.235 ;
      RECT 92.805 14.715 92.905 19.255 ;
      RECT 92.805 19.67 92.905 24.21 ;
      RECT 92.805 24.64 92.905 26.935 ;
      RECT 92.805 27.415 92.905 31.955 ;
      RECT 92.805 32.37 92.905 36.91 ;
      RECT 92.805 37.34 92.905 39.635 ;
      RECT 92.805 40.115 92.905 44.655 ;
      RECT 92.805 45.07 92.905 49.61 ;
      RECT 92.805 50.04 92.905 52.335 ;
      RECT 92.805 52.815 92.905 57.355 ;
      RECT 92.805 57.77 92.905 62.31 ;
      RECT 92.805 62.74 92.905 65.035 ;
      RECT 92.805 65.515 92.905 70.055 ;
      RECT 92.805 70.47 92.905 75.01 ;
      RECT 92.805 75.44 92.905 77.735 ;
      RECT 92.805 78.215 92.905 82.755 ;
      RECT 92.805 83.17 92.905 87.71 ;
      RECT 92.805 88.14 92.905 90.435 ;
      RECT 92.805 90.915 92.905 95.455 ;
      RECT 92.805 95.87 92.905 100.41 ;
      RECT 92.805 100.84 92.905 103.135 ;
      RECT 92.805 103.615 92.905 108.155 ;
      RECT 92.805 108.57 92.905 113.11 ;
      RECT 92.805 113.54 92.905 115.835 ;
      RECT 92.805 116.315 92.905 120.855 ;
      RECT 92.805 121.27 92.905 125.81 ;
      RECT 92.805 126.24 92.905 128.535 ;
      RECT 92.805 129.015 92.905 133.555 ;
      RECT 92.805 133.97 92.905 138.51 ;
      RECT 92.805 138.94 92.905 141.235 ;
      RECT 92.805 141.715 92.905 146.255 ;
      RECT 92.805 146.67 92.905 151.21 ;
      RECT 92.805 151.64 92.905 153.935 ;
      RECT 92.805 154.415 92.905 158.955 ;
      RECT 92.805 159.37 92.905 163.91 ;
      RECT 92.805 164.34 92.905 166.635 ;
      RECT 92.805 167.115 92.905 171.655 ;
      RECT 92.805 172.07 92.905 176.61 ;
      RECT 92.805 177.04 92.905 179.335 ;
      RECT 92.805 221.24 92.905 225.78 ;
      RECT 92.805 226.195 92.905 230.735 ;
      RECT 92.805 231.165 92.905 233.46 ;
      RECT 92.805 233.94 92.905 238.48 ;
      RECT 92.805 238.895 92.905 243.435 ;
      RECT 92.805 243.865 92.905 246.16 ;
      RECT 92.805 246.64 92.905 251.18 ;
      RECT 92.805 251.595 92.905 256.135 ;
      RECT 92.805 256.565 92.905 258.86 ;
      RECT 92.805 259.34 92.905 263.88 ;
      RECT 92.805 264.295 92.905 268.835 ;
      RECT 92.805 269.265 92.905 271.56 ;
      RECT 92.805 272.04 92.905 276.58 ;
      RECT 92.805 276.995 92.905 281.535 ;
      RECT 92.805 281.965 92.905 284.26 ;
      RECT 92.805 284.74 92.905 289.28 ;
      RECT 92.805 289.695 92.905 294.235 ;
      RECT 92.805 294.665 92.905 296.96 ;
      RECT 92.805 297.44 92.905 301.98 ;
      RECT 92.805 302.395 92.905 306.935 ;
      RECT 92.805 307.365 92.905 309.66 ;
      RECT 92.805 310.14 92.905 314.68 ;
      RECT 92.805 315.095 92.905 319.635 ;
      RECT 92.805 320.065 92.905 322.36 ;
      RECT 92.805 322.84 92.905 327.38 ;
      RECT 92.805 327.795 92.905 332.335 ;
      RECT 92.805 332.765 92.905 335.06 ;
      RECT 92.805 335.54 92.905 340.08 ;
      RECT 92.805 340.495 92.905 345.035 ;
      RECT 92.805 345.465 92.905 347.76 ;
      RECT 92.805 348.24 92.905 352.78 ;
      RECT 92.805 353.195 92.905 357.735 ;
      RECT 92.805 358.165 92.905 360.46 ;
      RECT 92.805 360.94 92.905 365.48 ;
      RECT 92.805 365.895 92.905 370.435 ;
      RECT 92.805 370.865 92.905 373.16 ;
      RECT 92.805 373.64 92.905 378.18 ;
      RECT 92.805 378.595 92.905 383.135 ;
      RECT 92.805 383.565 92.905 385.86 ;
      RECT 92.805 386.34 92.905 390.88 ;
      RECT 92.805 391.295 92.905 395.835 ;
      RECT 92.805 396.265 92.905 398.56 ;
      RECT 92.505 2.015 92.605 6.555 ;
      RECT 92.505 6.97 92.605 11.51 ;
      RECT 92.505 11.94 92.605 14.235 ;
      RECT 92.505 14.715 92.605 19.255 ;
      RECT 92.505 19.67 92.605 24.21 ;
      RECT 92.505 24.64 92.605 26.935 ;
      RECT 92.505 27.415 92.605 31.955 ;
      RECT 92.505 32.37 92.605 36.91 ;
      RECT 92.505 37.34 92.605 39.635 ;
      RECT 92.505 40.115 92.605 44.655 ;
      RECT 92.505 45.07 92.605 49.61 ;
      RECT 92.505 50.04 92.605 52.335 ;
      RECT 92.505 52.815 92.605 57.355 ;
      RECT 92.505 57.77 92.605 62.31 ;
      RECT 92.505 62.74 92.605 65.035 ;
      RECT 92.505 65.515 92.605 70.055 ;
      RECT 92.505 70.47 92.605 75.01 ;
      RECT 92.505 75.44 92.605 77.735 ;
      RECT 92.505 78.215 92.605 82.755 ;
      RECT 92.505 83.17 92.605 87.71 ;
      RECT 92.505 88.14 92.605 90.435 ;
      RECT 92.505 90.915 92.605 95.455 ;
      RECT 92.505 95.87 92.605 100.41 ;
      RECT 92.505 100.84 92.605 103.135 ;
      RECT 92.505 103.615 92.605 108.155 ;
      RECT 92.505 108.57 92.605 113.11 ;
      RECT 92.505 113.54 92.605 115.835 ;
      RECT 92.505 116.315 92.605 120.855 ;
      RECT 92.505 121.27 92.605 125.81 ;
      RECT 92.505 126.24 92.605 128.535 ;
      RECT 92.505 129.015 92.605 133.555 ;
      RECT 92.505 133.97 92.605 138.51 ;
      RECT 92.505 138.94 92.605 141.235 ;
      RECT 92.505 141.715 92.605 146.255 ;
      RECT 92.505 146.67 92.605 151.21 ;
      RECT 92.505 151.64 92.605 153.935 ;
      RECT 92.505 154.415 92.605 158.955 ;
      RECT 92.505 159.37 92.605 163.91 ;
      RECT 92.505 164.34 92.605 166.635 ;
      RECT 92.505 167.115 92.605 171.655 ;
      RECT 92.505 172.07 92.605 176.61 ;
      RECT 92.505 177.04 92.605 179.335 ;
      RECT 92.505 221.24 92.605 225.78 ;
      RECT 92.505 226.195 92.605 230.735 ;
      RECT 92.505 231.165 92.605 233.46 ;
      RECT 92.505 233.94 92.605 238.48 ;
      RECT 92.505 238.895 92.605 243.435 ;
      RECT 92.505 243.865 92.605 246.16 ;
      RECT 92.505 246.64 92.605 251.18 ;
      RECT 92.505 251.595 92.605 256.135 ;
      RECT 92.505 256.565 92.605 258.86 ;
      RECT 92.505 259.34 92.605 263.88 ;
      RECT 92.505 264.295 92.605 268.835 ;
      RECT 92.505 269.265 92.605 271.56 ;
      RECT 92.505 272.04 92.605 276.58 ;
      RECT 92.505 276.995 92.605 281.535 ;
      RECT 92.505 281.965 92.605 284.26 ;
      RECT 92.505 284.74 92.605 289.28 ;
      RECT 92.505 289.695 92.605 294.235 ;
      RECT 92.505 294.665 92.605 296.96 ;
      RECT 92.505 297.44 92.605 301.98 ;
      RECT 92.505 302.395 92.605 306.935 ;
      RECT 92.505 307.365 92.605 309.66 ;
      RECT 92.505 310.14 92.605 314.68 ;
      RECT 92.505 315.095 92.605 319.635 ;
      RECT 92.505 320.065 92.605 322.36 ;
      RECT 92.505 322.84 92.605 327.38 ;
      RECT 92.505 327.795 92.605 332.335 ;
      RECT 92.505 332.765 92.605 335.06 ;
      RECT 92.505 335.54 92.605 340.08 ;
      RECT 92.505 340.495 92.605 345.035 ;
      RECT 92.505 345.465 92.605 347.76 ;
      RECT 92.505 348.24 92.605 352.78 ;
      RECT 92.505 353.195 92.605 357.735 ;
      RECT 92.505 358.165 92.605 360.46 ;
      RECT 92.505 360.94 92.605 365.48 ;
      RECT 92.505 365.895 92.605 370.435 ;
      RECT 92.505 370.865 92.605 373.16 ;
      RECT 92.505 373.64 92.605 378.18 ;
      RECT 92.505 378.595 92.605 383.135 ;
      RECT 92.505 383.565 92.605 385.86 ;
      RECT 92.505 386.34 92.605 390.88 ;
      RECT 92.505 391.295 92.605 395.835 ;
      RECT 92.505 396.265 92.605 398.56 ;
      RECT 90.555 1.98 91.555 400 ;
      RECT 89.255 1.98 90.255 400 ;
      RECT 88.655 396.265 88.755 398.56 ;
      RECT 88.355 396.265 88.455 398.56 ;
      RECT 88.055 396.265 88.155 398.56 ;
      RECT 87.755 396.265 87.855 398.56 ;
      RECT 87.455 396.265 87.555 398.56 ;
      RECT 87.155 396.265 87.255 398.56 ;
      RECT 86.855 396.265 86.955 398.56 ;
      RECT 86.555 396.265 86.655 398.56 ;
      RECT 86.255 396.265 86.355 398.56 ;
      RECT 85.955 396.265 86.055 398.56 ;
      RECT 85.655 396.265 85.755 398.56 ;
      RECT 85.355 396.265 85.455 398.56 ;
      RECT 85.055 396.265 85.155 398.56 ;
      RECT 84.755 396.265 84.855 398.56 ;
      RECT 84.455 396.265 84.555 398.56 ;
      RECT 84.155 396.265 84.255 398.56 ;
      RECT 83.855 396.265 83.955 398.56 ;
      RECT 83.555 396.265 83.655 398.56 ;
      RECT 83.255 396.265 83.355 398.56 ;
      RECT 82.955 396.265 83.055 398.56 ;
      RECT 82.655 396.265 82.755 398.56 ;
      RECT 82.355 396.265 82.455 398.56 ;
      RECT 82.055 396.265 82.155 398.56 ;
      RECT 81.755 396.265 81.855 398.56 ;
      RECT 81.455 396.265 81.555 398.56 ;
      RECT 81.155 396.265 81.255 398.56 ;
      RECT 80.855 396.265 80.955 398.56 ;
      RECT 80.555 396.265 80.655 398.56 ;
      RECT 80.255 396.265 80.355 398.56 ;
      RECT 79.955 396.265 80.055 398.56 ;
      RECT 79.655 396.265 79.755 398.56 ;
      RECT 79.355 396.265 79.455 398.56 ;
      RECT 79.055 396.265 79.155 398.56 ;
      RECT 78.755 396.265 78.855 398.56 ;
      RECT 77.105 1.98 78.105 400 ;
      RECT 75.805 1.98 76.805 400 ;
      RECT 75.205 396.265 75.305 398.56 ;
      RECT 74.905 396.265 75.005 398.56 ;
      RECT 74.605 396.265 74.705 398.56 ;
      RECT 74.305 396.265 74.405 398.56 ;
      RECT 74.005 396.265 74.105 398.56 ;
      RECT 73.705 396.265 73.805 398.56 ;
      RECT 73.405 396.265 73.505 398.56 ;
      RECT 73.105 396.265 73.205 398.56 ;
      RECT 72.805 396.265 72.905 398.56 ;
      RECT 72.505 396.265 72.605 398.56 ;
      RECT 72.205 396.265 72.305 398.56 ;
      RECT 71.905 396.265 72.005 398.56 ;
      RECT 71.605 396.265 71.705 398.56 ;
      RECT 71.305 396.265 71.405 398.56 ;
      RECT 71.005 396.265 71.105 398.56 ;
      RECT 70.705 396.265 70.805 398.56 ;
      RECT 70.405 396.265 70.505 398.56 ;
      RECT 70.105 396.265 70.205 398.56 ;
      RECT 69.805 396.265 69.905 398.56 ;
      RECT 69.505 396.265 69.605 398.56 ;
      RECT 69.205 396.265 69.305 398.56 ;
      RECT 68.905 396.265 69.005 398.56 ;
      RECT 68.605 396.265 68.705 398.56 ;
      RECT 68.305 396.265 68.405 398.56 ;
      RECT 68.005 396.265 68.105 398.56 ;
      RECT 67.705 396.265 67.805 398.56 ;
      RECT 67.405 396.265 67.505 398.56 ;
      RECT 67.105 396.265 67.205 398.56 ;
      RECT 66.805 396.265 66.905 398.56 ;
      RECT 66.505 396.265 66.605 398.56 ;
      RECT 66.205 396.265 66.305 398.56 ;
      RECT 65.905 396.265 66.005 398.56 ;
      RECT 65.605 396.265 65.705 398.56 ;
      RECT 65.305 396.265 65.405 398.56 ;
      RECT 63.655 1.98 64.655 400 ;
      RECT 62.355 1.98 63.355 400 ;
    LAYER M5 SPACING 0.05 ;
      RECT 174.8 0 240 400 ;
      RECT 161.35 0 164.59 400 ;
      RECT 147.9 0 151.14 400 ;
      RECT 134.45 0 137.69 400 ;
      RECT 121.26 0 124.24 400 ;
      RECT 115.76 0 118.85 400 ;
      RECT 102.31 0 105.55 400 ;
      RECT 88.86 0 92.1 400 ;
      RECT 75.41 0 78.65 400 ;
      RECT 0 0 65.2 400 ;
      RECT 174.595 0 174.695 398.56 ;
      RECT 174.295 0 174.395 398.56 ;
      RECT 173.995 0 174.095 398.56 ;
      RECT 173.695 0 173.795 398.56 ;
      RECT 173.395 0 173.495 398.56 ;
      RECT 173.095 0 173.195 398.56 ;
      RECT 172.795 0 172.895 398.56 ;
      RECT 172.495 0 172.595 398.56 ;
      RECT 172.195 0 172.295 398.56 ;
      RECT 171.895 0 171.995 398.56 ;
      RECT 171.595 0 171.695 398.56 ;
      RECT 171.295 0 171.395 398.56 ;
      RECT 170.995 0 171.095 398.56 ;
      RECT 170.695 0 170.795 398.56 ;
      RECT 170.395 0 170.495 398.56 ;
      RECT 170.095 0 170.195 398.56 ;
      RECT 169.795 0 169.895 398.56 ;
      RECT 169.495 0 169.595 398.56 ;
      RECT 169.195 0 169.295 398.56 ;
      RECT 168.895 0 168.995 398.56 ;
      RECT 168.595 0 168.695 398.56 ;
      RECT 168.295 0 168.395 398.56 ;
      RECT 167.995 0 168.095 398.56 ;
      RECT 167.695 0 167.795 398.56 ;
      RECT 167.395 0 167.495 398.56 ;
      RECT 167.095 0 167.195 398.56 ;
      RECT 166.795 0 166.895 398.56 ;
      RECT 166.495 0 166.595 398.56 ;
      RECT 166.195 0 166.295 398.56 ;
      RECT 165.895 0 165.995 398.56 ;
      RECT 165.595 0 165.695 398.56 ;
      RECT 165.295 0 165.395 398.56 ;
      RECT 164.995 0 165.095 398.56 ;
      RECT 164.695 0 164.795 398.56 ;
      RECT 161.145 0 161.245 398.56 ;
      RECT 160.845 0 160.945 398.56 ;
      RECT 160.545 0 160.645 398.56 ;
      RECT 160.245 0 160.345 398.56 ;
      RECT 159.945 0 160.045 398.56 ;
      RECT 159.645 0 159.745 398.56 ;
      RECT 159.345 0 159.445 398.56 ;
      RECT 159.045 0 159.145 398.56 ;
      RECT 158.745 0 158.845 398.56 ;
      RECT 158.445 0 158.545 398.56 ;
      RECT 158.145 0 158.245 398.56 ;
      RECT 157.845 0 157.945 398.56 ;
      RECT 157.545 0 157.645 398.56 ;
      RECT 157.245 0 157.345 398.56 ;
      RECT 156.945 0 157.045 398.56 ;
      RECT 156.645 0 156.745 398.56 ;
      RECT 156.345 0 156.445 398.56 ;
      RECT 156.045 0 156.145 398.56 ;
      RECT 155.745 0 155.845 398.56 ;
      RECT 155.445 0 155.545 398.56 ;
      RECT 155.145 0 155.245 398.56 ;
      RECT 154.845 0 154.945 398.56 ;
      RECT 154.545 0 154.645 398.56 ;
      RECT 154.245 0 154.345 398.56 ;
      RECT 153.945 0 154.045 398.56 ;
      RECT 153.645 0 153.745 398.56 ;
      RECT 153.345 0 153.445 398.56 ;
      RECT 153.045 0 153.145 398.56 ;
      RECT 152.745 0 152.845 398.56 ;
      RECT 152.445 0 152.545 398.56 ;
      RECT 152.145 0 152.245 398.56 ;
      RECT 151.845 0 151.945 398.56 ;
      RECT 151.545 0 151.645 398.56 ;
      RECT 151.245 0 151.345 398.56 ;
      RECT 147.395 0 147.495 398.56 ;
      RECT 147.095 0 147.195 398.56 ;
      RECT 146.795 0 146.895 398.56 ;
      RECT 146.495 0 146.595 398.56 ;
      RECT 146.195 0 146.295 398.56 ;
      RECT 145.895 0 145.995 398.56 ;
      RECT 145.595 0 145.695 398.56 ;
      RECT 145.295 0 145.395 398.56 ;
      RECT 144.995 0 145.095 398.56 ;
      RECT 144.695 0 144.795 398.56 ;
      RECT 144.395 0 144.495 398.56 ;
      RECT 144.095 0 144.195 398.56 ;
      RECT 143.795 0 143.895 398.56 ;
      RECT 143.495 0 143.595 398.56 ;
      RECT 143.195 0 143.295 398.56 ;
      RECT 142.895 0 142.995 398.56 ;
      RECT 142.595 0 142.695 398.56 ;
      RECT 142.295 0 142.395 398.56 ;
      RECT 141.995 0 142.095 398.56 ;
      RECT 141.695 0 141.795 398.56 ;
      RECT 141.395 0 141.495 398.56 ;
      RECT 141.095 0 141.195 398.56 ;
      RECT 140.795 0 140.895 398.56 ;
      RECT 140.495 0 140.595 398.56 ;
      RECT 140.195 0 140.295 398.56 ;
      RECT 139.895 0 139.995 398.56 ;
      RECT 139.595 0 139.695 398.56 ;
      RECT 139.295 0 139.395 398.56 ;
      RECT 138.995 0 139.095 398.56 ;
      RECT 138.695 0 138.795 398.56 ;
      RECT 138.395 0 138.495 398.56 ;
      RECT 138.095 0 138.195 398.56 ;
      RECT 137.795 0 137.895 398.56 ;
      RECT 134.245 0 134.345 398.56 ;
      RECT 133.945 0 134.045 398.56 ;
      RECT 133.645 0 133.745 398.56 ;
      RECT 133.345 0 133.445 398.56 ;
      RECT 133.045 0 133.145 398.56 ;
      RECT 132.745 0 132.845 398.56 ;
      RECT 132.445 0 132.545 398.56 ;
      RECT 132.145 0 132.245 398.56 ;
      RECT 131.845 0 131.945 398.56 ;
      RECT 131.545 0 131.645 398.56 ;
      RECT 131.245 0 131.345 398.56 ;
      RECT 130.945 0 131.045 398.56 ;
      RECT 130.645 0 130.745 398.56 ;
      RECT 130.345 0 130.445 398.56 ;
      RECT 130.045 0 130.145 398.56 ;
      RECT 129.745 0 129.845 398.56 ;
      RECT 129.445 0 129.545 398.56 ;
      RECT 129.145 0 129.245 398.56 ;
      RECT 128.845 0 128.945 398.56 ;
      RECT 128.545 0 128.645 398.56 ;
      RECT 128.245 0 128.345 398.56 ;
      RECT 127.945 0 128.045 398.56 ;
      RECT 127.645 0 127.745 398.56 ;
      RECT 127.345 0 127.445 398.56 ;
      RECT 127.045 0 127.145 398.56 ;
      RECT 126.745 0 126.845 398.56 ;
      RECT 126.445 0 126.545 398.56 ;
      RECT 126.145 0 126.245 398.56 ;
      RECT 125.845 0 125.945 398.56 ;
      RECT 125.545 0 125.645 398.56 ;
      RECT 125.245 0 125.345 398.56 ;
      RECT 124.945 0 125.045 398.56 ;
      RECT 124.645 0 124.745 398.56 ;
      RECT 124.345 0 124.445 398.56 ;
      RECT 115.555 0 115.655 398.56 ;
      RECT 115.255 0 115.355 398.56 ;
      RECT 114.955 0 115.055 398.56 ;
      RECT 114.655 0 114.755 398.56 ;
      RECT 114.355 0 114.455 398.56 ;
      RECT 114.055 0 114.155 398.56 ;
      RECT 113.755 0 113.855 398.56 ;
      RECT 113.455 0 113.555 398.56 ;
      RECT 113.155 0 113.255 398.56 ;
      RECT 112.855 0 112.955 398.56 ;
      RECT 112.555 0 112.655 398.56 ;
      RECT 112.255 0 112.355 398.56 ;
      RECT 111.955 0 112.055 398.56 ;
      RECT 111.655 0 111.755 398.56 ;
      RECT 111.355 0 111.455 398.56 ;
      RECT 111.055 0 111.155 398.56 ;
      RECT 110.755 0 110.855 398.56 ;
      RECT 110.455 0 110.555 398.56 ;
      RECT 110.155 0 110.255 398.56 ;
      RECT 109.855 0 109.955 398.56 ;
      RECT 109.555 0 109.655 398.56 ;
      RECT 109.255 0 109.355 398.56 ;
      RECT 108.955 0 109.055 398.56 ;
      RECT 108.655 0 108.755 398.56 ;
      RECT 108.355 0 108.455 398.56 ;
      RECT 108.055 0 108.155 398.56 ;
      RECT 107.755 0 107.855 398.56 ;
      RECT 107.455 0 107.555 398.56 ;
      RECT 107.155 0 107.255 398.56 ;
      RECT 106.855 0 106.955 398.56 ;
      RECT 106.555 0 106.655 398.56 ;
      RECT 106.255 0 106.355 398.56 ;
      RECT 105.955 0 106.055 398.56 ;
      RECT 105.655 0 105.755 398.56 ;
      RECT 102.105 0 102.205 398.56 ;
      RECT 101.805 0 101.905 398.56 ;
      RECT 101.505 0 101.605 398.56 ;
      RECT 101.205 0 101.305 398.56 ;
      RECT 100.905 0 101.005 398.56 ;
      RECT 100.605 0 100.705 398.56 ;
      RECT 100.305 0 100.405 398.56 ;
      RECT 100.005 0 100.105 398.56 ;
      RECT 99.705 0 99.805 398.56 ;
      RECT 99.405 0 99.505 398.56 ;
      RECT 99.105 0 99.205 398.56 ;
      RECT 98.805 0 98.905 398.56 ;
      RECT 98.505 0 98.605 398.56 ;
      RECT 98.205 0 98.305 398.56 ;
      RECT 97.905 0 98.005 398.56 ;
      RECT 97.605 0 97.705 398.56 ;
      RECT 97.305 0 97.405 398.56 ;
      RECT 97.005 0 97.105 398.56 ;
      RECT 96.705 0 96.805 398.56 ;
      RECT 96.405 0 96.505 398.56 ;
      RECT 96.105 0 96.205 398.56 ;
      RECT 95.805 0 95.905 398.56 ;
      RECT 95.505 0 95.605 398.56 ;
      RECT 95.205 0 95.305 398.56 ;
      RECT 94.905 0 95.005 398.56 ;
      RECT 94.605 0 94.705 398.56 ;
      RECT 94.305 0 94.405 398.56 ;
      RECT 94.005 0 94.105 398.56 ;
      RECT 93.705 0 93.805 398.56 ;
      RECT 93.405 0 93.505 398.56 ;
      RECT 93.105 0 93.205 398.56 ;
      RECT 92.805 0 92.905 398.56 ;
      RECT 92.505 0 92.605 398.56 ;
      RECT 88.655 0 88.755 398.56 ;
      RECT 88.355 0 88.455 398.56 ;
      RECT 88.055 0 88.155 398.56 ;
      RECT 87.755 0 87.855 398.56 ;
      RECT 87.455 0 87.555 398.56 ;
      RECT 87.155 0 87.255 398.56 ;
      RECT 86.855 0 86.955 398.56 ;
      RECT 86.555 0 86.655 398.56 ;
      RECT 86.255 0 86.355 398.56 ;
      RECT 85.955 0 86.055 398.56 ;
      RECT 85.655 0 85.755 398.56 ;
      RECT 85.355 0 85.455 398.56 ;
      RECT 85.055 0 85.155 398.56 ;
      RECT 84.755 0 84.855 398.56 ;
      RECT 84.455 0 84.555 398.56 ;
      RECT 84.155 0 84.255 398.56 ;
      RECT 83.855 0 83.955 398.56 ;
      RECT 83.555 0 83.655 398.56 ;
      RECT 83.255 0 83.355 398.56 ;
      RECT 82.955 0 83.055 398.56 ;
      RECT 82.655 0 82.755 398.56 ;
      RECT 82.355 0 82.455 398.56 ;
      RECT 82.055 0 82.155 398.56 ;
      RECT 81.755 0 81.855 398.56 ;
      RECT 81.455 0 81.555 398.56 ;
      RECT 81.155 0 81.255 398.56 ;
      RECT 80.855 0 80.955 398.56 ;
      RECT 80.555 0 80.655 398.56 ;
      RECT 80.255 0 80.355 398.56 ;
      RECT 79.955 0 80.055 398.56 ;
      RECT 79.655 0 79.755 398.56 ;
      RECT 79.355 0 79.455 398.56 ;
      RECT 79.055 0 79.155 398.56 ;
      RECT 78.755 0 78.855 398.56 ;
      RECT 75.205 0 75.305 398.56 ;
      RECT 74.905 0 75.005 398.56 ;
      RECT 74.605 0 74.705 398.56 ;
      RECT 74.305 0 74.405 398.56 ;
      RECT 74.005 0 74.105 398.56 ;
      RECT 73.705 0 73.805 398.56 ;
      RECT 73.405 0 73.505 398.56 ;
      RECT 73.105 0 73.205 398.56 ;
      RECT 72.805 0 72.905 398.56 ;
      RECT 72.505 0 72.605 398.56 ;
      RECT 72.205 0 72.305 398.56 ;
      RECT 71.905 0 72.005 398.56 ;
      RECT 71.605 0 71.705 398.56 ;
      RECT 71.305 0 71.405 398.56 ;
      RECT 71.005 0 71.105 398.56 ;
      RECT 70.705 0 70.805 398.56 ;
      RECT 70.405 0 70.505 398.56 ;
      RECT 70.105 0 70.205 398.56 ;
      RECT 69.805 0 69.905 398.56 ;
      RECT 69.505 0 69.605 398.56 ;
      RECT 69.205 0 69.305 398.56 ;
      RECT 68.905 0 69.005 398.56 ;
      RECT 68.605 0 68.705 398.56 ;
      RECT 68.305 0 68.405 398.56 ;
      RECT 68.005 0 68.105 398.56 ;
      RECT 67.705 0 67.805 398.56 ;
      RECT 67.405 0 67.505 398.56 ;
      RECT 67.105 0 67.205 398.56 ;
      RECT 66.805 0 66.905 398.56 ;
      RECT 66.505 0 66.605 398.56 ;
      RECT 66.205 0 66.305 398.56 ;
      RECT 65.905 0 66.005 398.56 ;
      RECT 65.605 0 65.705 398.56 ;
      RECT 65.305 0 65.405 398.56 ;
      RECT 147.9 0 240 398.485 ;
      RECT 92.41 0 147.59 398.485 ;
      RECT 0 0 92.1 398.485 ;
      RECT 0 0 240 1.91 ;
    LAYER M7 ;
      RECT 174.745 2.015 174.845 6.555 ;
      RECT 174.745 6.97 174.845 11.51 ;
      RECT 174.745 11.94 174.845 14.235 ;
      RECT 174.745 14.715 174.845 19.255 ;
      RECT 174.745 19.67 174.845 24.21 ;
      RECT 174.745 24.64 174.845 26.935 ;
      RECT 174.745 27.415 174.845 31.955 ;
      RECT 174.745 32.37 174.845 36.91 ;
      RECT 174.745 37.34 174.845 39.635 ;
      RECT 174.745 40.115 174.845 44.655 ;
      RECT 174.745 45.07 174.845 49.61 ;
      RECT 174.745 50.04 174.845 52.335 ;
      RECT 174.745 52.815 174.845 57.355 ;
      RECT 174.745 57.77 174.845 62.31 ;
      RECT 174.745 62.74 174.845 65.035 ;
      RECT 174.745 65.515 174.845 70.055 ;
      RECT 174.745 70.47 174.845 75.01 ;
      RECT 174.745 75.44 174.845 77.735 ;
      RECT 174.745 78.215 174.845 82.755 ;
      RECT 174.745 83.17 174.845 87.71 ;
      RECT 174.745 88.14 174.845 90.435 ;
      RECT 174.745 90.915 174.845 95.455 ;
      RECT 174.745 95.87 174.845 100.41 ;
      RECT 174.745 100.84 174.845 103.135 ;
      RECT 174.745 103.615 174.845 108.155 ;
      RECT 174.745 108.57 174.845 113.11 ;
      RECT 174.745 113.54 174.845 115.835 ;
      RECT 174.745 116.315 174.845 120.855 ;
      RECT 174.745 121.27 174.845 125.81 ;
      RECT 174.745 126.24 174.845 128.535 ;
      RECT 174.745 129.015 174.845 133.555 ;
      RECT 174.745 133.97 174.845 138.51 ;
      RECT 174.745 138.94 174.845 141.235 ;
      RECT 174.745 141.715 174.845 146.255 ;
      RECT 174.745 146.67 174.845 151.21 ;
      RECT 174.745 151.64 174.845 153.935 ;
      RECT 174.745 154.415 174.845 158.955 ;
      RECT 174.745 159.37 174.845 163.91 ;
      RECT 174.745 164.34 174.845 166.635 ;
      RECT 174.745 167.115 174.845 171.655 ;
      RECT 174.745 172.07 174.845 176.61 ;
      RECT 174.745 177.04 174.845 179.335 ;
      RECT 174.745 221.24 174.845 225.78 ;
      RECT 174.745 226.195 174.845 230.735 ;
      RECT 174.745 231.165 174.845 233.46 ;
      RECT 174.745 233.94 174.845 238.48 ;
      RECT 174.745 238.895 174.845 243.435 ;
      RECT 174.745 243.865 174.845 246.16 ;
      RECT 174.745 246.64 174.845 251.18 ;
      RECT 174.745 251.595 174.845 256.135 ;
      RECT 174.745 256.565 174.845 258.86 ;
      RECT 174.745 259.34 174.845 263.88 ;
      RECT 174.745 264.295 174.845 268.835 ;
      RECT 174.745 269.265 174.845 271.56 ;
      RECT 174.745 272.04 174.845 276.58 ;
      RECT 174.745 276.995 174.845 281.535 ;
      RECT 174.745 281.965 174.845 284.26 ;
      RECT 174.745 284.74 174.845 289.28 ;
      RECT 174.745 289.695 174.845 294.235 ;
      RECT 174.745 294.665 174.845 296.96 ;
      RECT 174.745 297.44 174.845 301.98 ;
      RECT 174.745 302.395 174.845 306.935 ;
      RECT 174.745 307.365 174.845 309.66 ;
      RECT 174.745 310.14 174.845 314.68 ;
      RECT 174.745 315.095 174.845 319.635 ;
      RECT 174.745 320.065 174.845 322.36 ;
      RECT 174.745 322.84 174.845 327.38 ;
      RECT 174.745 327.795 174.845 332.335 ;
      RECT 174.745 332.765 174.845 335.06 ;
      RECT 174.745 335.54 174.845 340.08 ;
      RECT 174.745 340.495 174.845 345.035 ;
      RECT 174.745 345.465 174.845 347.76 ;
      RECT 174.745 348.24 174.845 352.78 ;
      RECT 174.745 353.195 174.845 357.735 ;
      RECT 174.745 358.165 174.845 360.46 ;
      RECT 174.745 360.94 174.845 365.48 ;
      RECT 174.745 365.895 174.845 370.435 ;
      RECT 174.745 370.865 174.845 373.16 ;
      RECT 174.745 373.64 174.845 378.18 ;
      RECT 174.745 378.595 174.845 383.135 ;
      RECT 174.745 383.565 174.845 385.86 ;
      RECT 174.745 386.34 174.845 390.88 ;
      RECT 174.745 391.295 174.845 395.835 ;
      RECT 174.445 393.54 174.545 395.835 ;
      RECT 174.145 393.54 174.245 395.835 ;
      RECT 173.845 393.54 173.945 395.835 ;
      RECT 173.545 393.54 173.645 395.835 ;
      RECT 173.245 393.54 173.345 395.835 ;
      RECT 172.945 393.54 173.045 395.835 ;
      RECT 172.645 393.54 172.745 395.835 ;
      RECT 172.345 393.54 172.445 395.835 ;
      RECT 172.045 393.54 172.145 395.835 ;
      RECT 171.745 393.54 171.845 395.835 ;
      RECT 171.445 393.54 171.545 395.835 ;
      RECT 171.145 393.54 171.245 395.835 ;
      RECT 170.845 393.54 170.945 395.835 ;
      RECT 170.545 393.54 170.645 395.835 ;
      RECT 170.245 393.54 170.345 395.835 ;
      RECT 169.945 393.54 170.045 395.835 ;
      RECT 169.645 393.54 169.745 395.835 ;
      RECT 169.345 393.54 169.445 395.835 ;
      RECT 169.045 393.54 169.145 395.835 ;
      RECT 168.745 393.54 168.845 395.835 ;
      RECT 168.445 393.54 168.545 395.835 ;
      RECT 168.145 393.54 168.245 395.835 ;
      RECT 167.845 393.54 167.945 395.835 ;
      RECT 167.545 393.54 167.645 395.835 ;
      RECT 167.245 393.54 167.345 395.835 ;
      RECT 166.945 393.54 167.045 395.835 ;
      RECT 166.645 393.54 166.745 395.835 ;
      RECT 166.345 393.54 166.445 395.835 ;
      RECT 166.045 393.54 166.145 395.835 ;
      RECT 165.745 393.54 165.845 395.835 ;
      RECT 165.445 393.54 165.545 395.835 ;
      RECT 165.145 393.54 165.245 395.835 ;
      RECT 164.845 2.015 164.945 6.555 ;
      RECT 164.845 6.97 164.945 11.51 ;
      RECT 164.845 11.94 164.945 14.235 ;
      RECT 164.845 14.715 164.945 19.255 ;
      RECT 164.845 19.67 164.945 24.21 ;
      RECT 164.845 24.64 164.945 26.935 ;
      RECT 164.845 27.415 164.945 31.955 ;
      RECT 164.845 32.37 164.945 36.91 ;
      RECT 164.845 37.34 164.945 39.635 ;
      RECT 164.845 40.115 164.945 44.655 ;
      RECT 164.845 45.07 164.945 49.61 ;
      RECT 164.845 50.04 164.945 52.335 ;
      RECT 164.845 52.815 164.945 57.355 ;
      RECT 164.845 57.77 164.945 62.31 ;
      RECT 164.845 62.74 164.945 65.035 ;
      RECT 164.845 65.515 164.945 70.055 ;
      RECT 164.845 70.47 164.945 75.01 ;
      RECT 164.845 75.44 164.945 77.735 ;
      RECT 164.845 78.215 164.945 82.755 ;
      RECT 164.845 83.17 164.945 87.71 ;
      RECT 164.845 88.14 164.945 90.435 ;
      RECT 164.845 90.915 164.945 95.455 ;
      RECT 164.845 95.87 164.945 100.41 ;
      RECT 164.845 100.84 164.945 103.135 ;
      RECT 164.845 103.615 164.945 108.155 ;
      RECT 164.845 108.57 164.945 113.11 ;
      RECT 164.845 113.54 164.945 115.835 ;
      RECT 164.845 116.315 164.945 120.855 ;
      RECT 164.845 121.27 164.945 125.81 ;
      RECT 164.845 126.24 164.945 128.535 ;
      RECT 164.845 129.015 164.945 133.555 ;
      RECT 164.845 133.97 164.945 138.51 ;
      RECT 164.845 138.94 164.945 141.235 ;
      RECT 164.845 141.715 164.945 146.255 ;
      RECT 164.845 146.67 164.945 151.21 ;
      RECT 164.845 151.64 164.945 153.935 ;
      RECT 164.845 154.415 164.945 158.955 ;
      RECT 164.845 159.37 164.945 163.91 ;
      RECT 164.845 164.34 164.945 166.635 ;
      RECT 164.845 167.115 164.945 171.655 ;
      RECT 164.845 172.07 164.945 176.61 ;
      RECT 164.845 177.04 164.945 179.335 ;
      RECT 164.845 221.24 164.945 225.78 ;
      RECT 164.845 226.195 164.945 230.735 ;
      RECT 164.845 231.165 164.945 233.46 ;
      RECT 164.845 233.94 164.945 238.48 ;
      RECT 164.845 238.895 164.945 243.435 ;
      RECT 164.845 243.865 164.945 246.16 ;
      RECT 164.845 246.64 164.945 251.18 ;
      RECT 164.845 251.595 164.945 256.135 ;
      RECT 164.845 256.565 164.945 258.86 ;
      RECT 164.845 259.34 164.945 263.88 ;
      RECT 164.845 264.295 164.945 268.835 ;
      RECT 164.845 269.265 164.945 271.56 ;
      RECT 164.845 272.04 164.945 276.58 ;
      RECT 164.845 276.995 164.945 281.535 ;
      RECT 164.845 281.965 164.945 284.26 ;
      RECT 164.845 284.74 164.945 289.28 ;
      RECT 164.845 289.695 164.945 294.235 ;
      RECT 164.845 294.665 164.945 296.96 ;
      RECT 164.845 297.44 164.945 301.98 ;
      RECT 164.845 302.395 164.945 306.935 ;
      RECT 164.845 307.365 164.945 309.66 ;
      RECT 164.845 310.14 164.945 314.68 ;
      RECT 164.845 315.095 164.945 319.635 ;
      RECT 164.845 320.065 164.945 322.36 ;
      RECT 164.845 322.84 164.945 327.38 ;
      RECT 164.845 327.795 164.945 332.335 ;
      RECT 164.845 332.765 164.945 335.06 ;
      RECT 164.845 335.54 164.945 340.08 ;
      RECT 164.845 340.495 164.945 345.035 ;
      RECT 164.845 345.465 164.945 347.76 ;
      RECT 164.845 348.24 164.945 352.78 ;
      RECT 164.845 353.195 164.945 357.735 ;
      RECT 164.845 358.165 164.945 360.46 ;
      RECT 164.845 360.94 164.945 365.48 ;
      RECT 164.845 365.895 164.945 370.435 ;
      RECT 164.845 370.865 164.945 373.16 ;
      RECT 164.845 373.64 164.945 378.18 ;
      RECT 164.845 378.595 164.945 383.135 ;
      RECT 164.845 383.565 164.945 385.86 ;
      RECT 164.845 386.34 164.945 390.88 ;
      RECT 164.845 391.295 164.945 395.835 ;
      RECT 161.295 2.015 161.395 6.555 ;
      RECT 161.295 6.97 161.395 11.51 ;
      RECT 161.295 11.94 161.395 14.235 ;
      RECT 161.295 14.715 161.395 19.255 ;
      RECT 161.295 19.67 161.395 24.21 ;
      RECT 161.295 24.64 161.395 26.935 ;
      RECT 161.295 27.415 161.395 31.955 ;
      RECT 161.295 32.37 161.395 36.91 ;
      RECT 161.295 37.34 161.395 39.635 ;
      RECT 161.295 40.115 161.395 44.655 ;
      RECT 161.295 45.07 161.395 49.61 ;
      RECT 161.295 50.04 161.395 52.335 ;
      RECT 161.295 52.815 161.395 57.355 ;
      RECT 161.295 57.77 161.395 62.31 ;
      RECT 161.295 62.74 161.395 65.035 ;
      RECT 161.295 65.515 161.395 70.055 ;
      RECT 161.295 70.47 161.395 75.01 ;
      RECT 161.295 75.44 161.395 77.735 ;
      RECT 161.295 78.215 161.395 82.755 ;
      RECT 161.295 83.17 161.395 87.71 ;
      RECT 161.295 88.14 161.395 90.435 ;
      RECT 161.295 90.915 161.395 95.455 ;
      RECT 161.295 95.87 161.395 100.41 ;
      RECT 161.295 100.84 161.395 103.135 ;
      RECT 161.295 103.615 161.395 108.155 ;
      RECT 161.295 108.57 161.395 113.11 ;
      RECT 161.295 113.54 161.395 115.835 ;
      RECT 161.295 116.315 161.395 120.855 ;
      RECT 161.295 121.27 161.395 125.81 ;
      RECT 161.295 126.24 161.395 128.535 ;
      RECT 161.295 129.015 161.395 133.555 ;
      RECT 161.295 133.97 161.395 138.51 ;
      RECT 161.295 138.94 161.395 141.235 ;
      RECT 161.295 141.715 161.395 146.255 ;
      RECT 161.295 146.67 161.395 151.21 ;
      RECT 161.295 151.64 161.395 153.935 ;
      RECT 161.295 154.415 161.395 158.955 ;
      RECT 161.295 159.37 161.395 163.91 ;
      RECT 161.295 164.34 161.395 166.635 ;
      RECT 161.295 167.115 161.395 171.655 ;
      RECT 161.295 172.07 161.395 176.61 ;
      RECT 161.295 177.04 161.395 179.335 ;
      RECT 161.295 221.24 161.395 225.78 ;
      RECT 161.295 226.195 161.395 230.735 ;
      RECT 161.295 231.165 161.395 233.46 ;
      RECT 161.295 233.94 161.395 238.48 ;
      RECT 161.295 238.895 161.395 243.435 ;
      RECT 161.295 243.865 161.395 246.16 ;
      RECT 161.295 246.64 161.395 251.18 ;
      RECT 161.295 251.595 161.395 256.135 ;
      RECT 161.295 256.565 161.395 258.86 ;
      RECT 161.295 259.34 161.395 263.88 ;
      RECT 161.295 264.295 161.395 268.835 ;
      RECT 161.295 269.265 161.395 271.56 ;
      RECT 161.295 272.04 161.395 276.58 ;
      RECT 161.295 276.995 161.395 281.535 ;
      RECT 161.295 281.965 161.395 284.26 ;
      RECT 161.295 284.74 161.395 289.28 ;
      RECT 161.295 289.695 161.395 294.235 ;
      RECT 161.295 294.665 161.395 296.96 ;
      RECT 161.295 297.44 161.395 301.98 ;
      RECT 161.295 302.395 161.395 306.935 ;
      RECT 161.295 307.365 161.395 309.66 ;
      RECT 161.295 310.14 161.395 314.68 ;
      RECT 161.295 315.095 161.395 319.635 ;
      RECT 161.295 320.065 161.395 322.36 ;
      RECT 161.295 322.84 161.395 327.38 ;
      RECT 161.295 327.795 161.395 332.335 ;
      RECT 161.295 332.765 161.395 335.06 ;
      RECT 161.295 335.54 161.395 340.08 ;
      RECT 161.295 340.495 161.395 345.035 ;
      RECT 161.295 345.465 161.395 347.76 ;
      RECT 161.295 348.24 161.395 352.78 ;
      RECT 161.295 353.195 161.395 357.735 ;
      RECT 161.295 358.165 161.395 360.46 ;
      RECT 161.295 360.94 161.395 365.48 ;
      RECT 161.295 365.895 161.395 370.435 ;
      RECT 161.295 370.865 161.395 373.16 ;
      RECT 161.295 373.64 161.395 378.18 ;
      RECT 161.295 378.595 161.395 383.135 ;
      RECT 161.295 383.565 161.395 385.86 ;
      RECT 161.295 386.34 161.395 390.88 ;
      RECT 161.295 391.295 161.395 395.835 ;
      RECT 160.995 393.54 161.095 395.835 ;
      RECT 160.695 393.54 160.795 395.835 ;
      RECT 160.395 393.54 160.495 395.835 ;
      RECT 160.095 393.54 160.195 395.835 ;
      RECT 159.795 393.54 159.895 395.835 ;
      RECT 159.495 393.54 159.595 395.835 ;
      RECT 159.195 393.54 159.295 395.835 ;
      RECT 158.895 393.54 158.995 395.835 ;
      RECT 158.595 393.54 158.695 395.835 ;
      RECT 158.295 393.54 158.395 395.835 ;
      RECT 157.995 393.54 158.095 395.835 ;
      RECT 157.695 393.54 157.795 395.835 ;
      RECT 157.395 393.54 157.495 395.835 ;
      RECT 157.095 393.54 157.195 395.835 ;
      RECT 156.795 393.54 156.895 395.835 ;
      RECT 156.495 393.54 156.595 395.835 ;
      RECT 156.195 393.54 156.295 395.835 ;
      RECT 155.895 393.54 155.995 395.835 ;
      RECT 155.595 393.54 155.695 395.835 ;
      RECT 155.295 393.54 155.395 395.835 ;
      RECT 154.995 393.54 155.095 395.835 ;
      RECT 154.695 393.54 154.795 395.835 ;
      RECT 154.395 393.54 154.495 395.835 ;
      RECT 154.095 393.54 154.195 395.835 ;
      RECT 153.795 393.54 153.895 395.835 ;
      RECT 153.495 393.54 153.595 395.835 ;
      RECT 153.195 393.54 153.295 395.835 ;
      RECT 152.895 393.54 152.995 395.835 ;
      RECT 152.595 393.54 152.695 395.835 ;
      RECT 152.295 393.54 152.395 395.835 ;
      RECT 151.995 393.54 152.095 395.835 ;
      RECT 151.695 393.54 151.795 395.835 ;
      RECT 151.395 2.015 151.495 6.555 ;
      RECT 151.395 6.97 151.495 11.51 ;
      RECT 151.395 11.94 151.495 14.235 ;
      RECT 151.395 14.715 151.495 19.255 ;
      RECT 151.395 19.67 151.495 24.21 ;
      RECT 151.395 24.64 151.495 26.935 ;
      RECT 151.395 27.415 151.495 31.955 ;
      RECT 151.395 32.37 151.495 36.91 ;
      RECT 151.395 37.34 151.495 39.635 ;
      RECT 151.395 40.115 151.495 44.655 ;
      RECT 151.395 45.07 151.495 49.61 ;
      RECT 151.395 50.04 151.495 52.335 ;
      RECT 151.395 52.815 151.495 57.355 ;
      RECT 151.395 57.77 151.495 62.31 ;
      RECT 151.395 62.74 151.495 65.035 ;
      RECT 151.395 65.515 151.495 70.055 ;
      RECT 151.395 70.47 151.495 75.01 ;
      RECT 151.395 75.44 151.495 77.735 ;
      RECT 151.395 78.215 151.495 82.755 ;
      RECT 151.395 83.17 151.495 87.71 ;
      RECT 151.395 88.14 151.495 90.435 ;
      RECT 151.395 90.915 151.495 95.455 ;
      RECT 151.395 95.87 151.495 100.41 ;
      RECT 151.395 100.84 151.495 103.135 ;
      RECT 151.395 103.615 151.495 108.155 ;
      RECT 151.395 108.57 151.495 113.11 ;
      RECT 151.395 113.54 151.495 115.835 ;
      RECT 151.395 116.315 151.495 120.855 ;
      RECT 151.395 121.27 151.495 125.81 ;
      RECT 151.395 126.24 151.495 128.535 ;
      RECT 151.395 129.015 151.495 133.555 ;
      RECT 151.395 133.97 151.495 138.51 ;
      RECT 151.395 138.94 151.495 141.235 ;
      RECT 151.395 141.715 151.495 146.255 ;
      RECT 151.395 146.67 151.495 151.21 ;
      RECT 151.395 151.64 151.495 153.935 ;
      RECT 151.395 154.415 151.495 158.955 ;
      RECT 151.395 159.37 151.495 163.91 ;
      RECT 151.395 164.34 151.495 166.635 ;
      RECT 151.395 167.115 151.495 171.655 ;
      RECT 151.395 172.07 151.495 176.61 ;
      RECT 151.395 177.04 151.495 179.335 ;
      RECT 151.395 221.24 151.495 225.78 ;
      RECT 151.395 226.195 151.495 230.735 ;
      RECT 151.395 231.165 151.495 233.46 ;
      RECT 151.395 233.94 151.495 238.48 ;
      RECT 151.395 238.895 151.495 243.435 ;
      RECT 151.395 243.865 151.495 246.16 ;
      RECT 151.395 246.64 151.495 251.18 ;
      RECT 151.395 251.595 151.495 256.135 ;
      RECT 151.395 256.565 151.495 258.86 ;
      RECT 151.395 259.34 151.495 263.88 ;
      RECT 151.395 264.295 151.495 268.835 ;
      RECT 151.395 269.265 151.495 271.56 ;
      RECT 151.395 272.04 151.495 276.58 ;
      RECT 151.395 276.995 151.495 281.535 ;
      RECT 151.395 281.965 151.495 284.26 ;
      RECT 151.395 284.74 151.495 289.28 ;
      RECT 151.395 289.695 151.495 294.235 ;
      RECT 151.395 294.665 151.495 296.96 ;
      RECT 151.395 297.44 151.495 301.98 ;
      RECT 151.395 302.395 151.495 306.935 ;
      RECT 151.395 307.365 151.495 309.66 ;
      RECT 151.395 310.14 151.495 314.68 ;
      RECT 151.395 315.095 151.495 319.635 ;
      RECT 151.395 320.065 151.495 322.36 ;
      RECT 151.395 322.84 151.495 327.38 ;
      RECT 151.395 327.795 151.495 332.335 ;
      RECT 151.395 332.765 151.495 335.06 ;
      RECT 151.395 335.54 151.495 340.08 ;
      RECT 151.395 340.495 151.495 345.035 ;
      RECT 151.395 345.465 151.495 347.76 ;
      RECT 151.395 348.24 151.495 352.78 ;
      RECT 151.395 353.195 151.495 357.735 ;
      RECT 151.395 358.165 151.495 360.46 ;
      RECT 151.395 360.94 151.495 365.48 ;
      RECT 151.395 365.895 151.495 370.435 ;
      RECT 151.395 370.865 151.495 373.16 ;
      RECT 151.395 373.64 151.495 378.18 ;
      RECT 151.395 378.595 151.495 383.135 ;
      RECT 151.395 383.565 151.495 385.86 ;
      RECT 151.395 386.34 151.495 390.88 ;
      RECT 151.395 391.295 151.495 395.835 ;
      RECT 147.845 2.015 147.945 6.555 ;
      RECT 147.845 6.97 147.945 11.51 ;
      RECT 147.845 11.94 147.945 14.235 ;
      RECT 147.845 14.715 147.945 19.255 ;
      RECT 147.845 19.67 147.945 24.21 ;
      RECT 147.845 24.64 147.945 26.935 ;
      RECT 147.845 27.415 147.945 31.955 ;
      RECT 147.845 32.37 147.945 36.91 ;
      RECT 147.845 37.34 147.945 39.635 ;
      RECT 147.845 40.115 147.945 44.655 ;
      RECT 147.845 45.07 147.945 49.61 ;
      RECT 147.845 50.04 147.945 52.335 ;
      RECT 147.845 52.815 147.945 57.355 ;
      RECT 147.845 57.77 147.945 62.31 ;
      RECT 147.845 62.74 147.945 65.035 ;
      RECT 147.845 65.515 147.945 70.055 ;
      RECT 147.845 70.47 147.945 75.01 ;
      RECT 147.845 75.44 147.945 77.735 ;
      RECT 147.845 78.215 147.945 82.755 ;
      RECT 147.845 83.17 147.945 87.71 ;
      RECT 147.845 88.14 147.945 90.435 ;
      RECT 147.845 90.915 147.945 95.455 ;
      RECT 147.845 95.87 147.945 100.41 ;
      RECT 147.845 100.84 147.945 103.135 ;
      RECT 147.845 103.615 147.945 108.155 ;
      RECT 147.845 108.57 147.945 113.11 ;
      RECT 147.845 113.54 147.945 115.835 ;
      RECT 147.845 116.315 147.945 120.855 ;
      RECT 147.845 121.27 147.945 125.81 ;
      RECT 147.845 126.24 147.945 128.535 ;
      RECT 147.845 129.015 147.945 133.555 ;
      RECT 147.845 133.97 147.945 138.51 ;
      RECT 147.845 138.94 147.945 141.235 ;
      RECT 147.845 141.715 147.945 146.255 ;
      RECT 147.845 146.67 147.945 151.21 ;
      RECT 147.845 151.64 147.945 153.935 ;
      RECT 147.845 154.415 147.945 158.955 ;
      RECT 147.845 159.37 147.945 163.91 ;
      RECT 147.845 164.34 147.945 166.635 ;
      RECT 147.845 167.115 147.945 171.655 ;
      RECT 147.845 172.07 147.945 176.61 ;
      RECT 147.845 177.04 147.945 179.335 ;
      RECT 147.845 221.24 147.945 225.78 ;
      RECT 147.845 226.195 147.945 230.735 ;
      RECT 147.845 231.165 147.945 233.46 ;
      RECT 147.845 233.94 147.945 238.48 ;
      RECT 147.845 238.895 147.945 243.435 ;
      RECT 147.845 243.865 147.945 246.16 ;
      RECT 147.845 246.64 147.945 251.18 ;
      RECT 147.845 251.595 147.945 256.135 ;
      RECT 147.845 256.565 147.945 258.86 ;
      RECT 147.845 259.34 147.945 263.88 ;
      RECT 147.845 264.295 147.945 268.835 ;
      RECT 147.845 269.265 147.945 271.56 ;
      RECT 147.845 272.04 147.945 276.58 ;
      RECT 147.845 276.995 147.945 281.535 ;
      RECT 147.845 281.965 147.945 284.26 ;
      RECT 147.845 284.74 147.945 289.28 ;
      RECT 147.845 289.695 147.945 294.235 ;
      RECT 147.845 294.665 147.945 296.96 ;
      RECT 147.845 297.44 147.945 301.98 ;
      RECT 147.845 302.395 147.945 306.935 ;
      RECT 147.845 307.365 147.945 309.66 ;
      RECT 147.845 310.14 147.945 314.68 ;
      RECT 147.845 315.095 147.945 319.635 ;
      RECT 147.845 320.065 147.945 322.36 ;
      RECT 147.845 322.84 147.945 327.38 ;
      RECT 147.845 327.795 147.945 332.335 ;
      RECT 147.845 332.765 147.945 335.06 ;
      RECT 147.845 335.54 147.945 340.08 ;
      RECT 147.845 340.495 147.945 345.035 ;
      RECT 147.845 345.465 147.945 347.76 ;
      RECT 147.845 348.24 147.945 352.78 ;
      RECT 147.845 353.195 147.945 357.735 ;
      RECT 147.845 358.165 147.945 360.46 ;
      RECT 147.845 360.94 147.945 365.48 ;
      RECT 147.845 365.895 147.945 370.435 ;
      RECT 147.845 370.865 147.945 373.16 ;
      RECT 147.845 373.64 147.945 378.18 ;
      RECT 147.845 378.595 147.945 383.135 ;
      RECT 147.845 383.565 147.945 385.86 ;
      RECT 147.845 386.34 147.945 390.88 ;
      RECT 147.845 391.295 147.945 395.835 ;
      RECT 147.545 393.54 147.645 395.835 ;
      RECT 147.245 393.54 147.345 395.835 ;
      RECT 146.945 393.54 147.045 395.835 ;
      RECT 146.645 393.54 146.745 395.835 ;
      RECT 146.345 393.54 146.445 395.835 ;
      RECT 146.045 393.54 146.145 395.835 ;
      RECT 145.745 393.54 145.845 395.835 ;
      RECT 145.445 393.54 145.545 395.835 ;
      RECT 145.145 393.54 145.245 395.835 ;
      RECT 144.845 393.54 144.945 395.835 ;
      RECT 144.545 393.54 144.645 395.835 ;
      RECT 144.245 393.54 144.345 395.835 ;
      RECT 143.945 393.54 144.045 395.835 ;
      RECT 143.645 393.54 143.745 395.835 ;
      RECT 143.345 393.54 143.445 395.835 ;
      RECT 143.045 393.54 143.145 395.835 ;
      RECT 142.745 393.54 142.845 395.835 ;
      RECT 142.445 393.54 142.545 395.835 ;
      RECT 142.145 393.54 142.245 395.835 ;
      RECT 141.845 393.54 141.945 395.835 ;
      RECT 141.545 393.54 141.645 395.835 ;
      RECT 141.245 393.54 141.345 395.835 ;
      RECT 140.945 393.54 141.045 395.835 ;
      RECT 140.645 393.54 140.745 395.835 ;
      RECT 140.345 393.54 140.445 395.835 ;
      RECT 140.045 393.54 140.145 395.835 ;
      RECT 139.745 393.54 139.845 395.835 ;
      RECT 139.445 393.54 139.545 395.835 ;
      RECT 139.145 393.54 139.245 395.835 ;
      RECT 138.845 393.54 138.945 395.835 ;
      RECT 138.545 393.54 138.645 395.835 ;
      RECT 138.245 393.54 138.345 395.835 ;
      RECT 137.945 2.015 138.045 6.555 ;
      RECT 137.945 6.97 138.045 11.51 ;
      RECT 137.945 11.94 138.045 14.235 ;
      RECT 137.945 14.715 138.045 19.255 ;
      RECT 137.945 19.67 138.045 24.21 ;
      RECT 137.945 24.64 138.045 26.935 ;
      RECT 137.945 27.415 138.045 31.955 ;
      RECT 137.945 32.37 138.045 36.91 ;
      RECT 137.945 37.34 138.045 39.635 ;
      RECT 137.945 40.115 138.045 44.655 ;
      RECT 137.945 45.07 138.045 49.61 ;
      RECT 137.945 50.04 138.045 52.335 ;
      RECT 137.945 52.815 138.045 57.355 ;
      RECT 137.945 57.77 138.045 62.31 ;
      RECT 137.945 62.74 138.045 65.035 ;
      RECT 137.945 65.515 138.045 70.055 ;
      RECT 137.945 70.47 138.045 75.01 ;
      RECT 137.945 75.44 138.045 77.735 ;
      RECT 137.945 78.215 138.045 82.755 ;
      RECT 137.945 83.17 138.045 87.71 ;
      RECT 137.945 88.14 138.045 90.435 ;
      RECT 137.945 90.915 138.045 95.455 ;
      RECT 137.945 95.87 138.045 100.41 ;
      RECT 137.945 100.84 138.045 103.135 ;
      RECT 137.945 103.615 138.045 108.155 ;
      RECT 137.945 108.57 138.045 113.11 ;
      RECT 137.945 113.54 138.045 115.835 ;
      RECT 137.945 116.315 138.045 120.855 ;
      RECT 137.945 121.27 138.045 125.81 ;
      RECT 137.945 126.24 138.045 128.535 ;
      RECT 137.945 129.015 138.045 133.555 ;
      RECT 137.945 133.97 138.045 138.51 ;
      RECT 137.945 138.94 138.045 141.235 ;
      RECT 137.945 141.715 138.045 146.255 ;
      RECT 137.945 146.67 138.045 151.21 ;
      RECT 137.945 151.64 138.045 153.935 ;
      RECT 137.945 154.415 138.045 158.955 ;
      RECT 137.945 159.37 138.045 163.91 ;
      RECT 137.945 164.34 138.045 166.635 ;
      RECT 137.945 167.115 138.045 171.655 ;
      RECT 137.945 172.07 138.045 176.61 ;
      RECT 137.945 177.04 138.045 179.335 ;
      RECT 137.945 221.24 138.045 225.78 ;
      RECT 137.945 226.195 138.045 230.735 ;
      RECT 137.945 231.165 138.045 233.46 ;
      RECT 137.945 233.94 138.045 238.48 ;
      RECT 137.945 238.895 138.045 243.435 ;
      RECT 137.945 243.865 138.045 246.16 ;
      RECT 137.945 246.64 138.045 251.18 ;
      RECT 137.945 251.595 138.045 256.135 ;
      RECT 137.945 256.565 138.045 258.86 ;
      RECT 137.945 259.34 138.045 263.88 ;
      RECT 137.945 264.295 138.045 268.835 ;
      RECT 137.945 269.265 138.045 271.56 ;
      RECT 137.945 272.04 138.045 276.58 ;
      RECT 137.945 276.995 138.045 281.535 ;
      RECT 137.945 281.965 138.045 284.26 ;
      RECT 137.945 284.74 138.045 289.28 ;
      RECT 137.945 289.695 138.045 294.235 ;
      RECT 137.945 294.665 138.045 296.96 ;
      RECT 137.945 297.44 138.045 301.98 ;
      RECT 137.945 302.395 138.045 306.935 ;
      RECT 137.945 307.365 138.045 309.66 ;
      RECT 137.945 310.14 138.045 314.68 ;
      RECT 137.945 315.095 138.045 319.635 ;
      RECT 137.945 320.065 138.045 322.36 ;
      RECT 137.945 322.84 138.045 327.38 ;
      RECT 137.945 327.795 138.045 332.335 ;
      RECT 137.945 332.765 138.045 335.06 ;
      RECT 137.945 335.54 138.045 340.08 ;
      RECT 137.945 340.495 138.045 345.035 ;
      RECT 137.945 345.465 138.045 347.76 ;
      RECT 137.945 348.24 138.045 352.78 ;
      RECT 137.945 353.195 138.045 357.735 ;
      RECT 137.945 358.165 138.045 360.46 ;
      RECT 137.945 360.94 138.045 365.48 ;
      RECT 137.945 365.895 138.045 370.435 ;
      RECT 137.945 370.865 138.045 373.16 ;
      RECT 137.945 373.64 138.045 378.18 ;
      RECT 137.945 378.595 138.045 383.135 ;
      RECT 137.945 383.565 138.045 385.86 ;
      RECT 137.945 386.34 138.045 390.88 ;
      RECT 137.945 391.295 138.045 395.835 ;
      RECT 134.395 2.015 134.495 6.555 ;
      RECT 134.395 6.97 134.495 11.51 ;
      RECT 134.395 11.94 134.495 14.235 ;
      RECT 134.395 14.715 134.495 19.255 ;
      RECT 134.395 19.67 134.495 24.21 ;
      RECT 134.395 24.64 134.495 26.935 ;
      RECT 134.395 27.415 134.495 31.955 ;
      RECT 134.395 32.37 134.495 36.91 ;
      RECT 134.395 37.34 134.495 39.635 ;
      RECT 134.395 40.115 134.495 44.655 ;
      RECT 134.395 45.07 134.495 49.61 ;
      RECT 134.395 50.04 134.495 52.335 ;
      RECT 134.395 52.815 134.495 57.355 ;
      RECT 134.395 57.77 134.495 62.31 ;
      RECT 134.395 62.74 134.495 65.035 ;
      RECT 134.395 65.515 134.495 70.055 ;
      RECT 134.395 70.47 134.495 75.01 ;
      RECT 134.395 75.44 134.495 77.735 ;
      RECT 134.395 78.215 134.495 82.755 ;
      RECT 134.395 83.17 134.495 87.71 ;
      RECT 134.395 88.14 134.495 90.435 ;
      RECT 134.395 90.915 134.495 95.455 ;
      RECT 134.395 95.87 134.495 100.41 ;
      RECT 134.395 100.84 134.495 103.135 ;
      RECT 134.395 103.615 134.495 108.155 ;
      RECT 134.395 108.57 134.495 113.11 ;
      RECT 134.395 113.54 134.495 115.835 ;
      RECT 134.395 116.315 134.495 120.855 ;
      RECT 134.395 121.27 134.495 125.81 ;
      RECT 134.395 126.24 134.495 128.535 ;
      RECT 134.395 129.015 134.495 133.555 ;
      RECT 134.395 133.97 134.495 138.51 ;
      RECT 134.395 138.94 134.495 141.235 ;
      RECT 134.395 141.715 134.495 146.255 ;
      RECT 134.395 146.67 134.495 151.21 ;
      RECT 134.395 151.64 134.495 153.935 ;
      RECT 134.395 154.415 134.495 158.955 ;
      RECT 134.395 159.37 134.495 163.91 ;
      RECT 134.395 164.34 134.495 166.635 ;
      RECT 134.395 167.115 134.495 171.655 ;
      RECT 134.395 172.07 134.495 176.61 ;
      RECT 134.395 177.04 134.495 179.335 ;
      RECT 134.395 221.24 134.495 225.78 ;
      RECT 134.395 226.195 134.495 230.735 ;
      RECT 134.395 231.165 134.495 233.46 ;
      RECT 134.395 233.94 134.495 238.48 ;
      RECT 134.395 238.895 134.495 243.435 ;
      RECT 134.395 243.865 134.495 246.16 ;
      RECT 134.395 246.64 134.495 251.18 ;
      RECT 134.395 251.595 134.495 256.135 ;
      RECT 134.395 256.565 134.495 258.86 ;
      RECT 134.395 259.34 134.495 263.88 ;
      RECT 134.395 264.295 134.495 268.835 ;
      RECT 134.395 269.265 134.495 271.56 ;
      RECT 134.395 272.04 134.495 276.58 ;
      RECT 134.395 276.995 134.495 281.535 ;
      RECT 134.395 281.965 134.495 284.26 ;
      RECT 134.395 284.74 134.495 289.28 ;
      RECT 134.395 289.695 134.495 294.235 ;
      RECT 134.395 294.665 134.495 296.96 ;
      RECT 134.395 297.44 134.495 301.98 ;
      RECT 134.395 302.395 134.495 306.935 ;
      RECT 134.395 307.365 134.495 309.66 ;
      RECT 134.395 310.14 134.495 314.68 ;
      RECT 134.395 315.095 134.495 319.635 ;
      RECT 134.395 320.065 134.495 322.36 ;
      RECT 134.395 322.84 134.495 327.38 ;
      RECT 134.395 327.795 134.495 332.335 ;
      RECT 134.395 332.765 134.495 335.06 ;
      RECT 134.395 335.54 134.495 340.08 ;
      RECT 134.395 340.495 134.495 345.035 ;
      RECT 134.395 345.465 134.495 347.76 ;
      RECT 134.395 348.24 134.495 352.78 ;
      RECT 134.395 353.195 134.495 357.735 ;
      RECT 134.395 358.165 134.495 360.46 ;
      RECT 134.395 360.94 134.495 365.48 ;
      RECT 134.395 365.895 134.495 370.435 ;
      RECT 134.395 370.865 134.495 373.16 ;
      RECT 134.395 373.64 134.495 378.18 ;
      RECT 134.395 378.595 134.495 383.135 ;
      RECT 134.395 383.565 134.495 385.86 ;
      RECT 134.395 386.34 134.495 390.88 ;
      RECT 134.395 391.295 134.495 395.835 ;
      RECT 134.095 393.54 134.195 395.835 ;
      RECT 133.795 393.54 133.895 395.835 ;
      RECT 133.495 393.54 133.595 395.835 ;
      RECT 133.195 393.54 133.295 395.835 ;
      RECT 132.895 393.54 132.995 395.835 ;
      RECT 132.595 393.54 132.695 395.835 ;
      RECT 132.295 393.54 132.395 395.835 ;
      RECT 131.995 393.54 132.095 395.835 ;
      RECT 131.695 393.54 131.795 395.835 ;
      RECT 131.395 393.54 131.495 395.835 ;
      RECT 131.095 393.54 131.195 395.835 ;
      RECT 130.795 393.54 130.895 395.835 ;
      RECT 130.495 393.54 130.595 395.835 ;
      RECT 130.195 393.54 130.295 395.835 ;
      RECT 129.895 393.54 129.995 395.835 ;
      RECT 129.595 393.54 129.695 395.835 ;
      RECT 129.295 393.54 129.395 395.835 ;
      RECT 128.995 393.54 129.095 395.835 ;
      RECT 128.695 393.54 128.795 395.835 ;
      RECT 128.395 393.54 128.495 395.835 ;
      RECT 128.095 393.54 128.195 395.835 ;
      RECT 127.795 393.54 127.895 395.835 ;
      RECT 127.495 393.54 127.595 395.835 ;
      RECT 127.195 393.54 127.295 395.835 ;
      RECT 126.895 393.54 126.995 395.835 ;
      RECT 126.595 393.54 126.695 395.835 ;
      RECT 126.295 393.54 126.395 395.835 ;
      RECT 125.995 393.54 126.095 395.835 ;
      RECT 125.695 393.54 125.795 395.835 ;
      RECT 125.395 393.54 125.495 395.835 ;
      RECT 125.095 393.54 125.195 395.835 ;
      RECT 124.795 393.54 124.895 395.835 ;
      RECT 124.495 2.015 124.595 6.555 ;
      RECT 124.495 6.97 124.595 11.51 ;
      RECT 124.495 11.94 124.595 14.235 ;
      RECT 124.495 14.715 124.595 19.255 ;
      RECT 124.495 19.67 124.595 24.21 ;
      RECT 124.495 24.64 124.595 26.935 ;
      RECT 124.495 27.415 124.595 31.955 ;
      RECT 124.495 32.37 124.595 36.91 ;
      RECT 124.495 37.34 124.595 39.635 ;
      RECT 124.495 40.115 124.595 44.655 ;
      RECT 124.495 45.07 124.595 49.61 ;
      RECT 124.495 50.04 124.595 52.335 ;
      RECT 124.495 52.815 124.595 57.355 ;
      RECT 124.495 57.77 124.595 62.31 ;
      RECT 124.495 62.74 124.595 65.035 ;
      RECT 124.495 65.515 124.595 70.055 ;
      RECT 124.495 70.47 124.595 75.01 ;
      RECT 124.495 75.44 124.595 77.735 ;
      RECT 124.495 78.215 124.595 82.755 ;
      RECT 124.495 83.17 124.595 87.71 ;
      RECT 124.495 88.14 124.595 90.435 ;
      RECT 124.495 90.915 124.595 95.455 ;
      RECT 124.495 95.87 124.595 100.41 ;
      RECT 124.495 100.84 124.595 103.135 ;
      RECT 124.495 103.615 124.595 108.155 ;
      RECT 124.495 108.57 124.595 113.11 ;
      RECT 124.495 113.54 124.595 115.835 ;
      RECT 124.495 116.315 124.595 120.855 ;
      RECT 124.495 121.27 124.595 125.81 ;
      RECT 124.495 126.24 124.595 128.535 ;
      RECT 124.495 129.015 124.595 133.555 ;
      RECT 124.495 133.97 124.595 138.51 ;
      RECT 124.495 138.94 124.595 141.235 ;
      RECT 124.495 141.715 124.595 146.255 ;
      RECT 124.495 146.67 124.595 151.21 ;
      RECT 124.495 151.64 124.595 153.935 ;
      RECT 124.495 154.415 124.595 158.955 ;
      RECT 124.495 159.37 124.595 163.91 ;
      RECT 124.495 164.34 124.595 166.635 ;
      RECT 124.495 167.115 124.595 171.655 ;
      RECT 124.495 172.07 124.595 176.61 ;
      RECT 124.495 177.04 124.595 179.335 ;
      RECT 124.495 221.24 124.595 225.78 ;
      RECT 124.495 226.195 124.595 230.735 ;
      RECT 124.495 231.165 124.595 233.46 ;
      RECT 124.495 233.94 124.595 238.48 ;
      RECT 124.495 238.895 124.595 243.435 ;
      RECT 124.495 243.865 124.595 246.16 ;
      RECT 124.495 246.64 124.595 251.18 ;
      RECT 124.495 251.595 124.595 256.135 ;
      RECT 124.495 256.565 124.595 258.86 ;
      RECT 124.495 259.34 124.595 263.88 ;
      RECT 124.495 264.295 124.595 268.835 ;
      RECT 124.495 269.265 124.595 271.56 ;
      RECT 124.495 272.04 124.595 276.58 ;
      RECT 124.495 276.995 124.595 281.535 ;
      RECT 124.495 281.965 124.595 284.26 ;
      RECT 124.495 284.74 124.595 289.28 ;
      RECT 124.495 289.695 124.595 294.235 ;
      RECT 124.495 294.665 124.595 296.96 ;
      RECT 124.495 297.44 124.595 301.98 ;
      RECT 124.495 302.395 124.595 306.935 ;
      RECT 124.495 307.365 124.595 309.66 ;
      RECT 124.495 310.14 124.595 314.68 ;
      RECT 124.495 315.095 124.595 319.635 ;
      RECT 124.495 320.065 124.595 322.36 ;
      RECT 124.495 322.84 124.595 327.38 ;
      RECT 124.495 327.795 124.595 332.335 ;
      RECT 124.495 332.765 124.595 335.06 ;
      RECT 124.495 335.54 124.595 340.08 ;
      RECT 124.495 340.495 124.595 345.035 ;
      RECT 124.495 345.465 124.595 347.76 ;
      RECT 124.495 348.24 124.595 352.78 ;
      RECT 124.495 353.195 124.595 357.735 ;
      RECT 124.495 358.165 124.595 360.46 ;
      RECT 124.495 360.94 124.595 365.48 ;
      RECT 124.495 365.895 124.595 370.435 ;
      RECT 124.495 370.865 124.595 373.16 ;
      RECT 124.495 373.64 124.595 378.18 ;
      RECT 124.495 378.595 124.595 383.135 ;
      RECT 124.495 383.565 124.595 385.86 ;
      RECT 124.495 386.34 124.595 390.88 ;
      RECT 124.495 391.295 124.595 395.835 ;
      RECT 115.405 2.015 115.505 6.555 ;
      RECT 115.405 6.97 115.505 11.51 ;
      RECT 115.405 11.94 115.505 14.235 ;
      RECT 115.405 14.715 115.505 19.255 ;
      RECT 115.405 19.67 115.505 24.21 ;
      RECT 115.405 24.64 115.505 26.935 ;
      RECT 115.405 27.415 115.505 31.955 ;
      RECT 115.405 32.37 115.505 36.91 ;
      RECT 115.405 37.34 115.505 39.635 ;
      RECT 115.405 40.115 115.505 44.655 ;
      RECT 115.405 45.07 115.505 49.61 ;
      RECT 115.405 50.04 115.505 52.335 ;
      RECT 115.405 52.815 115.505 57.355 ;
      RECT 115.405 57.77 115.505 62.31 ;
      RECT 115.405 62.74 115.505 65.035 ;
      RECT 115.405 65.515 115.505 70.055 ;
      RECT 115.405 70.47 115.505 75.01 ;
      RECT 115.405 75.44 115.505 77.735 ;
      RECT 115.405 78.215 115.505 82.755 ;
      RECT 115.405 83.17 115.505 87.71 ;
      RECT 115.405 88.14 115.505 90.435 ;
      RECT 115.405 90.915 115.505 95.455 ;
      RECT 115.405 95.87 115.505 100.41 ;
      RECT 115.405 100.84 115.505 103.135 ;
      RECT 115.405 103.615 115.505 108.155 ;
      RECT 115.405 108.57 115.505 113.11 ;
      RECT 115.405 113.54 115.505 115.835 ;
      RECT 115.405 116.315 115.505 120.855 ;
      RECT 115.405 121.27 115.505 125.81 ;
      RECT 115.405 126.24 115.505 128.535 ;
      RECT 115.405 129.015 115.505 133.555 ;
      RECT 115.405 133.97 115.505 138.51 ;
      RECT 115.405 138.94 115.505 141.235 ;
      RECT 115.405 141.715 115.505 146.255 ;
      RECT 115.405 146.67 115.505 151.21 ;
      RECT 115.405 151.64 115.505 153.935 ;
      RECT 115.405 154.415 115.505 158.955 ;
      RECT 115.405 159.37 115.505 163.91 ;
      RECT 115.405 164.34 115.505 166.635 ;
      RECT 115.405 167.115 115.505 171.655 ;
      RECT 115.405 172.07 115.505 176.61 ;
      RECT 115.405 177.04 115.505 179.335 ;
      RECT 115.405 221.24 115.505 225.78 ;
      RECT 115.405 226.195 115.505 230.735 ;
      RECT 115.405 231.165 115.505 233.46 ;
      RECT 115.405 233.94 115.505 238.48 ;
      RECT 115.405 238.895 115.505 243.435 ;
      RECT 115.405 243.865 115.505 246.16 ;
      RECT 115.405 246.64 115.505 251.18 ;
      RECT 115.405 251.595 115.505 256.135 ;
      RECT 115.405 256.565 115.505 258.86 ;
      RECT 115.405 259.34 115.505 263.88 ;
      RECT 115.405 264.295 115.505 268.835 ;
      RECT 115.405 269.265 115.505 271.56 ;
      RECT 115.405 272.04 115.505 276.58 ;
      RECT 115.405 276.995 115.505 281.535 ;
      RECT 115.405 281.965 115.505 284.26 ;
      RECT 115.405 284.74 115.505 289.28 ;
      RECT 115.405 289.695 115.505 294.235 ;
      RECT 115.405 294.665 115.505 296.96 ;
      RECT 115.405 297.44 115.505 301.98 ;
      RECT 115.405 302.395 115.505 306.935 ;
      RECT 115.405 307.365 115.505 309.66 ;
      RECT 115.405 310.14 115.505 314.68 ;
      RECT 115.405 315.095 115.505 319.635 ;
      RECT 115.405 320.065 115.505 322.36 ;
      RECT 115.405 322.84 115.505 327.38 ;
      RECT 115.405 327.795 115.505 332.335 ;
      RECT 115.405 332.765 115.505 335.06 ;
      RECT 115.405 335.54 115.505 340.08 ;
      RECT 115.405 340.495 115.505 345.035 ;
      RECT 115.405 345.465 115.505 347.76 ;
      RECT 115.405 348.24 115.505 352.78 ;
      RECT 115.405 353.195 115.505 357.735 ;
      RECT 115.405 358.165 115.505 360.46 ;
      RECT 115.405 360.94 115.505 365.48 ;
      RECT 115.405 365.895 115.505 370.435 ;
      RECT 115.405 370.865 115.505 373.16 ;
      RECT 115.405 373.64 115.505 378.18 ;
      RECT 115.405 378.595 115.505 383.135 ;
      RECT 115.405 383.565 115.505 385.86 ;
      RECT 115.405 386.34 115.505 390.88 ;
      RECT 115.405 391.295 115.505 395.835 ;
      RECT 115.105 393.54 115.205 395.835 ;
      RECT 114.805 393.54 114.905 395.835 ;
      RECT 114.505 393.54 114.605 395.835 ;
      RECT 114.205 393.54 114.305 395.835 ;
      RECT 113.905 393.54 114.005 395.835 ;
      RECT 113.605 393.54 113.705 395.835 ;
      RECT 113.305 393.54 113.405 395.835 ;
      RECT 113.005 393.54 113.105 395.835 ;
      RECT 112.705 393.54 112.805 395.835 ;
      RECT 112.405 393.54 112.505 395.835 ;
      RECT 112.105 393.54 112.205 395.835 ;
      RECT 111.805 393.54 111.905 395.835 ;
      RECT 111.505 393.54 111.605 395.835 ;
      RECT 111.205 393.54 111.305 395.835 ;
      RECT 110.905 393.54 111.005 395.835 ;
      RECT 110.605 393.54 110.705 395.835 ;
      RECT 110.305 393.54 110.405 395.835 ;
      RECT 110.005 393.54 110.105 395.835 ;
      RECT 109.705 393.54 109.805 395.835 ;
      RECT 109.405 393.54 109.505 395.835 ;
      RECT 109.105 393.54 109.205 395.835 ;
      RECT 108.805 393.54 108.905 395.835 ;
      RECT 108.505 393.54 108.605 395.835 ;
      RECT 108.205 393.54 108.305 395.835 ;
      RECT 107.905 393.54 108.005 395.835 ;
      RECT 107.605 393.54 107.705 395.835 ;
      RECT 107.305 393.54 107.405 395.835 ;
      RECT 107.005 393.54 107.105 395.835 ;
      RECT 106.705 393.54 106.805 395.835 ;
      RECT 106.405 393.54 106.505 395.835 ;
      RECT 106.105 393.54 106.205 395.835 ;
      RECT 105.805 393.54 105.905 395.835 ;
      RECT 105.505 2.015 105.605 6.555 ;
      RECT 105.505 6.97 105.605 11.51 ;
      RECT 105.505 11.94 105.605 14.235 ;
      RECT 105.505 14.715 105.605 19.255 ;
      RECT 105.505 19.67 105.605 24.21 ;
      RECT 105.505 24.64 105.605 26.935 ;
      RECT 105.505 27.415 105.605 31.955 ;
      RECT 105.505 32.37 105.605 36.91 ;
      RECT 105.505 37.34 105.605 39.635 ;
      RECT 105.505 40.115 105.605 44.655 ;
      RECT 105.505 45.07 105.605 49.61 ;
      RECT 105.505 50.04 105.605 52.335 ;
      RECT 105.505 52.815 105.605 57.355 ;
      RECT 105.505 57.77 105.605 62.31 ;
      RECT 105.505 62.74 105.605 65.035 ;
      RECT 105.505 65.515 105.605 70.055 ;
      RECT 105.505 70.47 105.605 75.01 ;
      RECT 105.505 75.44 105.605 77.735 ;
      RECT 105.505 78.215 105.605 82.755 ;
      RECT 105.505 83.17 105.605 87.71 ;
      RECT 105.505 88.14 105.605 90.435 ;
      RECT 105.505 90.915 105.605 95.455 ;
      RECT 105.505 95.87 105.605 100.41 ;
      RECT 105.505 100.84 105.605 103.135 ;
      RECT 105.505 103.615 105.605 108.155 ;
      RECT 105.505 108.57 105.605 113.11 ;
      RECT 105.505 113.54 105.605 115.835 ;
      RECT 105.505 116.315 105.605 120.855 ;
      RECT 105.505 121.27 105.605 125.81 ;
      RECT 105.505 126.24 105.605 128.535 ;
      RECT 105.505 129.015 105.605 133.555 ;
      RECT 105.505 133.97 105.605 138.51 ;
      RECT 105.505 138.94 105.605 141.235 ;
      RECT 105.505 141.715 105.605 146.255 ;
      RECT 105.505 146.67 105.605 151.21 ;
      RECT 105.505 151.64 105.605 153.935 ;
      RECT 105.505 154.415 105.605 158.955 ;
      RECT 105.505 159.37 105.605 163.91 ;
      RECT 105.505 164.34 105.605 166.635 ;
      RECT 105.505 167.115 105.605 171.655 ;
      RECT 105.505 172.07 105.605 176.61 ;
      RECT 105.505 177.04 105.605 179.335 ;
      RECT 105.505 221.24 105.605 225.78 ;
      RECT 105.505 226.195 105.605 230.735 ;
      RECT 105.505 231.165 105.605 233.46 ;
      RECT 105.505 233.94 105.605 238.48 ;
      RECT 105.505 238.895 105.605 243.435 ;
      RECT 105.505 243.865 105.605 246.16 ;
      RECT 105.505 246.64 105.605 251.18 ;
      RECT 105.505 251.595 105.605 256.135 ;
      RECT 105.505 256.565 105.605 258.86 ;
      RECT 105.505 259.34 105.605 263.88 ;
      RECT 105.505 264.295 105.605 268.835 ;
      RECT 105.505 269.265 105.605 271.56 ;
      RECT 105.505 272.04 105.605 276.58 ;
      RECT 105.505 276.995 105.605 281.535 ;
      RECT 105.505 281.965 105.605 284.26 ;
      RECT 105.505 284.74 105.605 289.28 ;
      RECT 105.505 289.695 105.605 294.235 ;
      RECT 105.505 294.665 105.605 296.96 ;
      RECT 105.505 297.44 105.605 301.98 ;
      RECT 105.505 302.395 105.605 306.935 ;
      RECT 105.505 307.365 105.605 309.66 ;
      RECT 105.505 310.14 105.605 314.68 ;
      RECT 105.505 315.095 105.605 319.635 ;
      RECT 105.505 320.065 105.605 322.36 ;
      RECT 105.505 322.84 105.605 327.38 ;
      RECT 105.505 327.795 105.605 332.335 ;
      RECT 105.505 332.765 105.605 335.06 ;
      RECT 105.505 335.54 105.605 340.08 ;
      RECT 105.505 340.495 105.605 345.035 ;
      RECT 105.505 345.465 105.605 347.76 ;
      RECT 105.505 348.24 105.605 352.78 ;
      RECT 105.505 353.195 105.605 357.735 ;
      RECT 105.505 358.165 105.605 360.46 ;
      RECT 105.505 360.94 105.605 365.48 ;
      RECT 105.505 365.895 105.605 370.435 ;
      RECT 105.505 370.865 105.605 373.16 ;
      RECT 105.505 373.64 105.605 378.18 ;
      RECT 105.505 378.595 105.605 383.135 ;
      RECT 105.505 383.565 105.605 385.86 ;
      RECT 105.505 386.34 105.605 390.88 ;
      RECT 105.505 391.295 105.605 395.835 ;
      RECT 101.955 2.015 102.055 6.555 ;
      RECT 101.955 6.97 102.055 11.51 ;
      RECT 101.955 11.94 102.055 14.235 ;
      RECT 101.955 14.715 102.055 19.255 ;
      RECT 101.955 19.67 102.055 24.21 ;
      RECT 101.955 24.64 102.055 26.935 ;
      RECT 101.955 27.415 102.055 31.955 ;
      RECT 101.955 32.37 102.055 36.91 ;
      RECT 101.955 37.34 102.055 39.635 ;
      RECT 101.955 40.115 102.055 44.655 ;
      RECT 101.955 45.07 102.055 49.61 ;
      RECT 101.955 50.04 102.055 52.335 ;
      RECT 101.955 52.815 102.055 57.355 ;
      RECT 101.955 57.77 102.055 62.31 ;
      RECT 101.955 62.74 102.055 65.035 ;
      RECT 101.955 65.515 102.055 70.055 ;
      RECT 101.955 70.47 102.055 75.01 ;
      RECT 101.955 75.44 102.055 77.735 ;
      RECT 101.955 78.215 102.055 82.755 ;
      RECT 101.955 83.17 102.055 87.71 ;
      RECT 101.955 88.14 102.055 90.435 ;
      RECT 101.955 90.915 102.055 95.455 ;
      RECT 101.955 95.87 102.055 100.41 ;
      RECT 101.955 100.84 102.055 103.135 ;
      RECT 101.955 103.615 102.055 108.155 ;
      RECT 101.955 108.57 102.055 113.11 ;
      RECT 101.955 113.54 102.055 115.835 ;
      RECT 101.955 116.315 102.055 120.855 ;
      RECT 101.955 121.27 102.055 125.81 ;
      RECT 101.955 126.24 102.055 128.535 ;
      RECT 101.955 129.015 102.055 133.555 ;
      RECT 101.955 133.97 102.055 138.51 ;
      RECT 101.955 138.94 102.055 141.235 ;
      RECT 101.955 141.715 102.055 146.255 ;
      RECT 101.955 146.67 102.055 151.21 ;
      RECT 101.955 151.64 102.055 153.935 ;
      RECT 101.955 154.415 102.055 158.955 ;
      RECT 101.955 159.37 102.055 163.91 ;
      RECT 101.955 164.34 102.055 166.635 ;
      RECT 101.955 167.115 102.055 171.655 ;
      RECT 101.955 172.07 102.055 176.61 ;
      RECT 101.955 177.04 102.055 179.335 ;
      RECT 101.955 221.24 102.055 225.78 ;
      RECT 101.955 226.195 102.055 230.735 ;
      RECT 101.955 231.165 102.055 233.46 ;
      RECT 101.955 233.94 102.055 238.48 ;
      RECT 101.955 238.895 102.055 243.435 ;
      RECT 101.955 243.865 102.055 246.16 ;
      RECT 101.955 246.64 102.055 251.18 ;
      RECT 101.955 251.595 102.055 256.135 ;
      RECT 101.955 256.565 102.055 258.86 ;
      RECT 101.955 259.34 102.055 263.88 ;
      RECT 101.955 264.295 102.055 268.835 ;
      RECT 101.955 269.265 102.055 271.56 ;
      RECT 101.955 272.04 102.055 276.58 ;
      RECT 101.955 276.995 102.055 281.535 ;
      RECT 101.955 281.965 102.055 284.26 ;
      RECT 101.955 284.74 102.055 289.28 ;
      RECT 101.955 289.695 102.055 294.235 ;
      RECT 101.955 294.665 102.055 296.96 ;
      RECT 101.955 297.44 102.055 301.98 ;
      RECT 101.955 302.395 102.055 306.935 ;
      RECT 101.955 307.365 102.055 309.66 ;
      RECT 101.955 310.14 102.055 314.68 ;
      RECT 101.955 315.095 102.055 319.635 ;
      RECT 101.955 320.065 102.055 322.36 ;
      RECT 101.955 322.84 102.055 327.38 ;
      RECT 101.955 327.795 102.055 332.335 ;
      RECT 101.955 332.765 102.055 335.06 ;
      RECT 101.955 335.54 102.055 340.08 ;
      RECT 101.955 340.495 102.055 345.035 ;
      RECT 101.955 345.465 102.055 347.76 ;
      RECT 101.955 348.24 102.055 352.78 ;
      RECT 101.955 353.195 102.055 357.735 ;
      RECT 101.955 358.165 102.055 360.46 ;
      RECT 101.955 360.94 102.055 365.48 ;
      RECT 101.955 365.895 102.055 370.435 ;
      RECT 101.955 370.865 102.055 373.16 ;
      RECT 101.955 373.64 102.055 378.18 ;
      RECT 101.955 378.595 102.055 383.135 ;
      RECT 101.955 383.565 102.055 385.86 ;
      RECT 101.955 386.34 102.055 390.88 ;
      RECT 101.955 391.295 102.055 395.835 ;
      RECT 101.655 393.54 101.755 395.835 ;
      RECT 101.355 393.54 101.455 395.835 ;
      RECT 101.055 393.54 101.155 395.835 ;
      RECT 100.755 393.54 100.855 395.835 ;
      RECT 100.455 393.54 100.555 395.835 ;
      RECT 100.155 393.54 100.255 395.835 ;
      RECT 99.855 393.54 99.955 395.835 ;
      RECT 99.555 393.54 99.655 395.835 ;
      RECT 99.255 393.54 99.355 395.835 ;
      RECT 98.955 393.54 99.055 395.835 ;
      RECT 98.655 393.54 98.755 395.835 ;
      RECT 98.355 393.54 98.455 395.835 ;
      RECT 98.055 393.54 98.155 395.835 ;
      RECT 97.755 393.54 97.855 395.835 ;
      RECT 97.455 393.54 97.555 395.835 ;
      RECT 97.155 393.54 97.255 395.835 ;
      RECT 96.855 393.54 96.955 395.835 ;
      RECT 96.555 393.54 96.655 395.835 ;
      RECT 96.255 393.54 96.355 395.835 ;
      RECT 95.955 393.54 96.055 395.835 ;
      RECT 95.655 393.54 95.755 395.835 ;
      RECT 95.355 393.54 95.455 395.835 ;
      RECT 95.055 393.54 95.155 395.835 ;
      RECT 94.755 393.54 94.855 395.835 ;
      RECT 94.455 393.54 94.555 395.835 ;
      RECT 94.155 393.54 94.255 395.835 ;
      RECT 93.855 393.54 93.955 395.835 ;
      RECT 93.555 393.54 93.655 395.835 ;
      RECT 93.255 393.54 93.355 395.835 ;
      RECT 92.955 393.54 93.055 395.835 ;
      RECT 92.655 393.54 92.755 395.835 ;
      RECT 92.355 393.54 92.455 395.835 ;
      RECT 92.055 2.015 92.155 6.555 ;
      RECT 92.055 6.97 92.155 11.51 ;
      RECT 92.055 11.94 92.155 14.235 ;
      RECT 92.055 14.715 92.155 19.255 ;
      RECT 92.055 19.67 92.155 24.21 ;
      RECT 92.055 24.64 92.155 26.935 ;
      RECT 92.055 27.415 92.155 31.955 ;
      RECT 92.055 32.37 92.155 36.91 ;
      RECT 92.055 37.34 92.155 39.635 ;
      RECT 92.055 40.115 92.155 44.655 ;
      RECT 92.055 45.07 92.155 49.61 ;
      RECT 92.055 50.04 92.155 52.335 ;
      RECT 92.055 52.815 92.155 57.355 ;
      RECT 92.055 57.77 92.155 62.31 ;
      RECT 92.055 62.74 92.155 65.035 ;
      RECT 92.055 65.515 92.155 70.055 ;
      RECT 92.055 70.47 92.155 75.01 ;
      RECT 92.055 75.44 92.155 77.735 ;
      RECT 92.055 78.215 92.155 82.755 ;
      RECT 92.055 83.17 92.155 87.71 ;
      RECT 92.055 88.14 92.155 90.435 ;
      RECT 92.055 90.915 92.155 95.455 ;
      RECT 92.055 95.87 92.155 100.41 ;
      RECT 92.055 100.84 92.155 103.135 ;
      RECT 92.055 103.615 92.155 108.155 ;
      RECT 92.055 108.57 92.155 113.11 ;
      RECT 92.055 113.54 92.155 115.835 ;
      RECT 92.055 116.315 92.155 120.855 ;
      RECT 92.055 121.27 92.155 125.81 ;
      RECT 92.055 126.24 92.155 128.535 ;
      RECT 92.055 129.015 92.155 133.555 ;
      RECT 92.055 133.97 92.155 138.51 ;
      RECT 92.055 138.94 92.155 141.235 ;
      RECT 92.055 141.715 92.155 146.255 ;
      RECT 92.055 146.67 92.155 151.21 ;
      RECT 92.055 151.64 92.155 153.935 ;
      RECT 92.055 154.415 92.155 158.955 ;
      RECT 92.055 159.37 92.155 163.91 ;
      RECT 92.055 164.34 92.155 166.635 ;
      RECT 92.055 167.115 92.155 171.655 ;
      RECT 92.055 172.07 92.155 176.61 ;
      RECT 92.055 177.04 92.155 179.335 ;
      RECT 92.055 221.24 92.155 225.78 ;
      RECT 92.055 226.195 92.155 230.735 ;
      RECT 92.055 231.165 92.155 233.46 ;
      RECT 92.055 233.94 92.155 238.48 ;
      RECT 92.055 238.895 92.155 243.435 ;
      RECT 92.055 243.865 92.155 246.16 ;
      RECT 92.055 246.64 92.155 251.18 ;
      RECT 92.055 251.595 92.155 256.135 ;
      RECT 92.055 256.565 92.155 258.86 ;
      RECT 92.055 259.34 92.155 263.88 ;
      RECT 92.055 264.295 92.155 268.835 ;
      RECT 92.055 269.265 92.155 271.56 ;
      RECT 92.055 272.04 92.155 276.58 ;
      RECT 92.055 276.995 92.155 281.535 ;
      RECT 92.055 281.965 92.155 284.26 ;
      RECT 92.055 284.74 92.155 289.28 ;
      RECT 92.055 289.695 92.155 294.235 ;
      RECT 92.055 294.665 92.155 296.96 ;
      RECT 92.055 297.44 92.155 301.98 ;
      RECT 92.055 302.395 92.155 306.935 ;
      RECT 92.055 307.365 92.155 309.66 ;
      RECT 92.055 310.14 92.155 314.68 ;
      RECT 92.055 315.095 92.155 319.635 ;
      RECT 92.055 320.065 92.155 322.36 ;
      RECT 92.055 322.84 92.155 327.38 ;
      RECT 92.055 327.795 92.155 332.335 ;
      RECT 92.055 332.765 92.155 335.06 ;
      RECT 92.055 335.54 92.155 340.08 ;
      RECT 92.055 340.495 92.155 345.035 ;
      RECT 92.055 345.465 92.155 347.76 ;
      RECT 92.055 348.24 92.155 352.78 ;
      RECT 92.055 353.195 92.155 357.735 ;
      RECT 92.055 358.165 92.155 360.46 ;
      RECT 92.055 360.94 92.155 365.48 ;
      RECT 92.055 365.895 92.155 370.435 ;
      RECT 92.055 370.865 92.155 373.16 ;
      RECT 92.055 373.64 92.155 378.18 ;
      RECT 92.055 378.595 92.155 383.135 ;
      RECT 92.055 383.565 92.155 385.86 ;
      RECT 92.055 386.34 92.155 390.88 ;
      RECT 92.055 391.295 92.155 395.835 ;
      RECT 88.505 2.015 88.605 6.555 ;
      RECT 88.505 6.97 88.605 11.51 ;
      RECT 88.505 11.94 88.605 14.235 ;
      RECT 88.505 14.715 88.605 19.255 ;
      RECT 88.505 19.67 88.605 24.21 ;
      RECT 88.505 24.64 88.605 26.935 ;
      RECT 88.505 27.415 88.605 31.955 ;
      RECT 88.505 32.37 88.605 36.91 ;
      RECT 88.505 37.34 88.605 39.635 ;
      RECT 88.505 40.115 88.605 44.655 ;
      RECT 88.505 45.07 88.605 49.61 ;
      RECT 88.505 50.04 88.605 52.335 ;
      RECT 88.505 52.815 88.605 57.355 ;
      RECT 88.505 57.77 88.605 62.31 ;
      RECT 88.505 62.74 88.605 65.035 ;
      RECT 88.505 65.515 88.605 70.055 ;
      RECT 88.505 70.47 88.605 75.01 ;
      RECT 88.505 75.44 88.605 77.735 ;
      RECT 88.505 78.215 88.605 82.755 ;
      RECT 88.505 83.17 88.605 87.71 ;
      RECT 88.505 88.14 88.605 90.435 ;
      RECT 88.505 90.915 88.605 95.455 ;
      RECT 88.505 95.87 88.605 100.41 ;
      RECT 88.505 100.84 88.605 103.135 ;
      RECT 88.505 103.615 88.605 108.155 ;
      RECT 88.505 108.57 88.605 113.11 ;
      RECT 88.505 113.54 88.605 115.835 ;
      RECT 88.505 116.315 88.605 120.855 ;
      RECT 88.505 121.27 88.605 125.81 ;
      RECT 88.505 126.24 88.605 128.535 ;
      RECT 88.505 129.015 88.605 133.555 ;
      RECT 88.505 133.97 88.605 138.51 ;
      RECT 88.505 138.94 88.605 141.235 ;
      RECT 88.505 141.715 88.605 146.255 ;
      RECT 88.505 146.67 88.605 151.21 ;
      RECT 88.505 151.64 88.605 153.935 ;
      RECT 88.505 154.415 88.605 158.955 ;
      RECT 88.505 159.37 88.605 163.91 ;
      RECT 88.505 164.34 88.605 166.635 ;
      RECT 88.505 167.115 88.605 171.655 ;
      RECT 88.505 172.07 88.605 176.61 ;
      RECT 88.505 177.04 88.605 179.335 ;
      RECT 88.505 221.24 88.605 225.78 ;
      RECT 88.505 226.195 88.605 230.735 ;
      RECT 88.505 231.165 88.605 233.46 ;
      RECT 88.505 233.94 88.605 238.48 ;
      RECT 88.505 238.895 88.605 243.435 ;
      RECT 88.505 243.865 88.605 246.16 ;
      RECT 88.505 246.64 88.605 251.18 ;
      RECT 88.505 251.595 88.605 256.135 ;
      RECT 88.505 256.565 88.605 258.86 ;
      RECT 88.505 259.34 88.605 263.88 ;
      RECT 88.505 264.295 88.605 268.835 ;
      RECT 88.505 269.265 88.605 271.56 ;
      RECT 88.505 272.04 88.605 276.58 ;
      RECT 88.505 276.995 88.605 281.535 ;
      RECT 88.505 281.965 88.605 284.26 ;
      RECT 88.505 284.74 88.605 289.28 ;
      RECT 88.505 289.695 88.605 294.235 ;
      RECT 88.505 294.665 88.605 296.96 ;
      RECT 88.505 297.44 88.605 301.98 ;
      RECT 88.505 302.395 88.605 306.935 ;
      RECT 88.505 307.365 88.605 309.66 ;
      RECT 88.505 310.14 88.605 314.68 ;
      RECT 88.505 315.095 88.605 319.635 ;
      RECT 88.505 320.065 88.605 322.36 ;
      RECT 88.505 322.84 88.605 327.38 ;
      RECT 88.505 327.795 88.605 332.335 ;
      RECT 88.505 332.765 88.605 335.06 ;
      RECT 88.505 335.54 88.605 340.08 ;
      RECT 88.505 340.495 88.605 345.035 ;
      RECT 88.505 345.465 88.605 347.76 ;
      RECT 88.505 348.24 88.605 352.78 ;
      RECT 88.505 353.195 88.605 357.735 ;
      RECT 88.505 358.165 88.605 360.46 ;
      RECT 88.505 360.94 88.605 365.48 ;
      RECT 88.505 365.895 88.605 370.435 ;
      RECT 88.505 370.865 88.605 373.16 ;
      RECT 88.505 373.64 88.605 378.18 ;
      RECT 88.505 378.595 88.605 383.135 ;
      RECT 88.505 383.565 88.605 385.86 ;
      RECT 88.505 386.34 88.605 390.88 ;
      RECT 88.505 391.295 88.605 395.835 ;
      RECT 88.205 393.54 88.305 395.835 ;
      RECT 87.905 393.54 88.005 395.835 ;
      RECT 87.605 393.54 87.705 395.835 ;
      RECT 87.305 393.54 87.405 395.835 ;
      RECT 87.005 393.54 87.105 395.835 ;
      RECT 86.705 393.54 86.805 395.835 ;
      RECT 86.405 393.54 86.505 395.835 ;
      RECT 86.105 393.54 86.205 395.835 ;
      RECT 85.805 393.54 85.905 395.835 ;
      RECT 85.505 393.54 85.605 395.835 ;
      RECT 85.205 393.54 85.305 395.835 ;
      RECT 84.905 393.54 85.005 395.835 ;
      RECT 84.605 393.54 84.705 395.835 ;
      RECT 84.305 393.54 84.405 395.835 ;
      RECT 84.005 393.54 84.105 395.835 ;
      RECT 83.705 393.54 83.805 395.835 ;
      RECT 83.405 393.54 83.505 395.835 ;
      RECT 83.105 393.54 83.205 395.835 ;
      RECT 82.805 393.54 82.905 395.835 ;
      RECT 82.505 393.54 82.605 395.835 ;
      RECT 82.205 393.54 82.305 395.835 ;
      RECT 81.905 393.54 82.005 395.835 ;
      RECT 81.605 393.54 81.705 395.835 ;
      RECT 81.305 393.54 81.405 395.835 ;
      RECT 81.005 393.54 81.105 395.835 ;
      RECT 80.705 393.54 80.805 395.835 ;
      RECT 80.405 393.54 80.505 395.835 ;
      RECT 80.105 393.54 80.205 395.835 ;
      RECT 79.805 393.54 79.905 395.835 ;
      RECT 79.505 393.54 79.605 395.835 ;
      RECT 79.205 393.54 79.305 395.835 ;
      RECT 78.905 393.54 79.005 395.835 ;
      RECT 78.605 2.015 78.705 6.555 ;
      RECT 78.605 6.97 78.705 11.51 ;
      RECT 78.605 11.94 78.705 14.235 ;
      RECT 78.605 14.715 78.705 19.255 ;
      RECT 78.605 19.67 78.705 24.21 ;
      RECT 78.605 24.64 78.705 26.935 ;
      RECT 78.605 27.415 78.705 31.955 ;
      RECT 78.605 32.37 78.705 36.91 ;
      RECT 78.605 37.34 78.705 39.635 ;
      RECT 78.605 40.115 78.705 44.655 ;
      RECT 78.605 45.07 78.705 49.61 ;
      RECT 78.605 50.04 78.705 52.335 ;
      RECT 78.605 52.815 78.705 57.355 ;
      RECT 78.605 57.77 78.705 62.31 ;
      RECT 78.605 62.74 78.705 65.035 ;
      RECT 78.605 65.515 78.705 70.055 ;
      RECT 78.605 70.47 78.705 75.01 ;
      RECT 78.605 75.44 78.705 77.735 ;
      RECT 78.605 78.215 78.705 82.755 ;
      RECT 78.605 83.17 78.705 87.71 ;
      RECT 78.605 88.14 78.705 90.435 ;
      RECT 78.605 90.915 78.705 95.455 ;
      RECT 78.605 95.87 78.705 100.41 ;
      RECT 78.605 100.84 78.705 103.135 ;
      RECT 78.605 103.615 78.705 108.155 ;
      RECT 78.605 108.57 78.705 113.11 ;
      RECT 78.605 113.54 78.705 115.835 ;
      RECT 78.605 116.315 78.705 120.855 ;
      RECT 78.605 121.27 78.705 125.81 ;
      RECT 78.605 126.24 78.705 128.535 ;
      RECT 78.605 129.015 78.705 133.555 ;
      RECT 78.605 133.97 78.705 138.51 ;
      RECT 78.605 138.94 78.705 141.235 ;
      RECT 78.605 141.715 78.705 146.255 ;
      RECT 78.605 146.67 78.705 151.21 ;
      RECT 78.605 151.64 78.705 153.935 ;
      RECT 78.605 154.415 78.705 158.955 ;
      RECT 78.605 159.37 78.705 163.91 ;
      RECT 78.605 164.34 78.705 166.635 ;
      RECT 78.605 167.115 78.705 171.655 ;
      RECT 78.605 172.07 78.705 176.61 ;
      RECT 78.605 177.04 78.705 179.335 ;
      RECT 78.605 221.24 78.705 225.78 ;
      RECT 78.605 226.195 78.705 230.735 ;
      RECT 78.605 231.165 78.705 233.46 ;
      RECT 78.605 233.94 78.705 238.48 ;
      RECT 78.605 238.895 78.705 243.435 ;
      RECT 78.605 243.865 78.705 246.16 ;
      RECT 78.605 246.64 78.705 251.18 ;
      RECT 78.605 251.595 78.705 256.135 ;
      RECT 78.605 256.565 78.705 258.86 ;
      RECT 78.605 259.34 78.705 263.88 ;
      RECT 78.605 264.295 78.705 268.835 ;
      RECT 78.605 269.265 78.705 271.56 ;
      RECT 78.605 272.04 78.705 276.58 ;
      RECT 78.605 276.995 78.705 281.535 ;
      RECT 78.605 281.965 78.705 284.26 ;
      RECT 78.605 284.74 78.705 289.28 ;
      RECT 78.605 289.695 78.705 294.235 ;
      RECT 78.605 294.665 78.705 296.96 ;
      RECT 78.605 297.44 78.705 301.98 ;
      RECT 78.605 302.395 78.705 306.935 ;
      RECT 78.605 307.365 78.705 309.66 ;
      RECT 78.605 310.14 78.705 314.68 ;
      RECT 78.605 315.095 78.705 319.635 ;
      RECT 78.605 320.065 78.705 322.36 ;
      RECT 78.605 322.84 78.705 327.38 ;
      RECT 78.605 327.795 78.705 332.335 ;
      RECT 78.605 332.765 78.705 335.06 ;
      RECT 78.605 335.54 78.705 340.08 ;
      RECT 78.605 340.495 78.705 345.035 ;
      RECT 78.605 345.465 78.705 347.76 ;
      RECT 78.605 348.24 78.705 352.78 ;
      RECT 78.605 353.195 78.705 357.735 ;
      RECT 78.605 358.165 78.705 360.46 ;
      RECT 78.605 360.94 78.705 365.48 ;
      RECT 78.605 365.895 78.705 370.435 ;
      RECT 78.605 370.865 78.705 373.16 ;
      RECT 78.605 373.64 78.705 378.18 ;
      RECT 78.605 378.595 78.705 383.135 ;
      RECT 78.605 383.565 78.705 385.86 ;
      RECT 78.605 386.34 78.705 390.88 ;
      RECT 78.605 391.295 78.705 395.835 ;
      RECT 75.055 2.015 75.155 6.555 ;
      RECT 75.055 6.97 75.155 11.51 ;
      RECT 75.055 11.94 75.155 14.235 ;
      RECT 75.055 14.715 75.155 19.255 ;
      RECT 75.055 19.67 75.155 24.21 ;
      RECT 75.055 24.64 75.155 26.935 ;
      RECT 75.055 27.415 75.155 31.955 ;
      RECT 75.055 32.37 75.155 36.91 ;
      RECT 75.055 37.34 75.155 39.635 ;
      RECT 75.055 40.115 75.155 44.655 ;
      RECT 75.055 45.07 75.155 49.61 ;
      RECT 75.055 50.04 75.155 52.335 ;
      RECT 75.055 52.815 75.155 57.355 ;
      RECT 75.055 57.77 75.155 62.31 ;
      RECT 75.055 62.74 75.155 65.035 ;
      RECT 75.055 65.515 75.155 70.055 ;
      RECT 75.055 70.47 75.155 75.01 ;
      RECT 75.055 75.44 75.155 77.735 ;
      RECT 75.055 78.215 75.155 82.755 ;
      RECT 75.055 83.17 75.155 87.71 ;
      RECT 75.055 88.14 75.155 90.435 ;
      RECT 75.055 90.915 75.155 95.455 ;
      RECT 75.055 95.87 75.155 100.41 ;
      RECT 75.055 100.84 75.155 103.135 ;
      RECT 75.055 103.615 75.155 108.155 ;
      RECT 75.055 108.57 75.155 113.11 ;
      RECT 75.055 113.54 75.155 115.835 ;
      RECT 75.055 116.315 75.155 120.855 ;
      RECT 75.055 121.27 75.155 125.81 ;
      RECT 75.055 126.24 75.155 128.535 ;
      RECT 75.055 129.015 75.155 133.555 ;
      RECT 75.055 133.97 75.155 138.51 ;
      RECT 75.055 138.94 75.155 141.235 ;
      RECT 75.055 141.715 75.155 146.255 ;
      RECT 75.055 146.67 75.155 151.21 ;
      RECT 75.055 151.64 75.155 153.935 ;
      RECT 75.055 154.415 75.155 158.955 ;
      RECT 75.055 159.37 75.155 163.91 ;
      RECT 75.055 164.34 75.155 166.635 ;
      RECT 75.055 167.115 75.155 171.655 ;
      RECT 75.055 172.07 75.155 176.61 ;
      RECT 75.055 177.04 75.155 179.335 ;
      RECT 75.055 221.24 75.155 225.78 ;
      RECT 75.055 226.195 75.155 230.735 ;
      RECT 75.055 231.165 75.155 233.46 ;
      RECT 75.055 233.94 75.155 238.48 ;
      RECT 75.055 238.895 75.155 243.435 ;
      RECT 75.055 243.865 75.155 246.16 ;
      RECT 75.055 246.64 75.155 251.18 ;
      RECT 75.055 251.595 75.155 256.135 ;
      RECT 75.055 256.565 75.155 258.86 ;
      RECT 75.055 259.34 75.155 263.88 ;
      RECT 75.055 264.295 75.155 268.835 ;
      RECT 75.055 269.265 75.155 271.56 ;
      RECT 75.055 272.04 75.155 276.58 ;
      RECT 75.055 276.995 75.155 281.535 ;
      RECT 75.055 281.965 75.155 284.26 ;
      RECT 75.055 284.74 75.155 289.28 ;
      RECT 75.055 289.695 75.155 294.235 ;
      RECT 75.055 294.665 75.155 296.96 ;
      RECT 75.055 297.44 75.155 301.98 ;
      RECT 75.055 302.395 75.155 306.935 ;
      RECT 75.055 307.365 75.155 309.66 ;
      RECT 75.055 310.14 75.155 314.68 ;
      RECT 75.055 315.095 75.155 319.635 ;
      RECT 75.055 320.065 75.155 322.36 ;
      RECT 75.055 322.84 75.155 327.38 ;
      RECT 75.055 327.795 75.155 332.335 ;
      RECT 75.055 332.765 75.155 335.06 ;
      RECT 75.055 335.54 75.155 340.08 ;
      RECT 75.055 340.495 75.155 345.035 ;
      RECT 75.055 345.465 75.155 347.76 ;
      RECT 75.055 348.24 75.155 352.78 ;
      RECT 75.055 353.195 75.155 357.735 ;
      RECT 75.055 358.165 75.155 360.46 ;
      RECT 75.055 360.94 75.155 365.48 ;
      RECT 75.055 365.895 75.155 370.435 ;
      RECT 75.055 370.865 75.155 373.16 ;
      RECT 75.055 373.64 75.155 378.18 ;
      RECT 75.055 378.595 75.155 383.135 ;
      RECT 75.055 383.565 75.155 385.86 ;
      RECT 75.055 386.34 75.155 390.88 ;
      RECT 75.055 391.295 75.155 395.835 ;
      RECT 74.755 393.54 74.855 395.835 ;
      RECT 74.455 393.54 74.555 395.835 ;
      RECT 74.155 393.54 74.255 395.835 ;
      RECT 73.855 393.54 73.955 395.835 ;
      RECT 73.555 393.54 73.655 395.835 ;
      RECT 73.255 393.54 73.355 395.835 ;
      RECT 72.955 393.54 73.055 395.835 ;
      RECT 72.655 393.54 72.755 395.835 ;
      RECT 72.355 393.54 72.455 395.835 ;
      RECT 72.055 393.54 72.155 395.835 ;
      RECT 71.755 393.54 71.855 395.835 ;
      RECT 71.455 393.54 71.555 395.835 ;
      RECT 71.155 393.54 71.255 395.835 ;
      RECT 70.855 393.54 70.955 395.835 ;
      RECT 70.555 393.54 70.655 395.835 ;
      RECT 70.255 393.54 70.355 395.835 ;
      RECT 69.955 393.54 70.055 395.835 ;
      RECT 69.655 393.54 69.755 395.835 ;
      RECT 69.355 393.54 69.455 395.835 ;
      RECT 69.055 393.54 69.155 395.835 ;
      RECT 68.755 393.54 68.855 395.835 ;
      RECT 68.455 393.54 68.555 395.835 ;
      RECT 68.155 393.54 68.255 395.835 ;
      RECT 67.855 393.54 67.955 395.835 ;
      RECT 67.555 393.54 67.655 395.835 ;
      RECT 67.255 393.54 67.355 395.835 ;
      RECT 66.955 393.54 67.055 395.835 ;
      RECT 66.655 393.54 66.755 395.835 ;
      RECT 66.355 393.54 66.455 395.835 ;
      RECT 66.055 393.54 66.155 395.835 ;
      RECT 65.755 393.54 65.855 395.835 ;
      RECT 65.455 393.54 65.555 395.835 ;
      RECT 65.155 2.015 65.255 6.555 ;
      RECT 65.155 6.97 65.255 11.51 ;
      RECT 65.155 11.94 65.255 14.235 ;
      RECT 65.155 14.715 65.255 19.255 ;
      RECT 65.155 19.67 65.255 24.21 ;
      RECT 65.155 24.64 65.255 26.935 ;
      RECT 65.155 27.415 65.255 31.955 ;
      RECT 65.155 32.37 65.255 36.91 ;
      RECT 65.155 37.34 65.255 39.635 ;
      RECT 65.155 40.115 65.255 44.655 ;
      RECT 65.155 45.07 65.255 49.61 ;
      RECT 65.155 50.04 65.255 52.335 ;
      RECT 65.155 52.815 65.255 57.355 ;
      RECT 65.155 57.77 65.255 62.31 ;
      RECT 65.155 62.74 65.255 65.035 ;
      RECT 65.155 65.515 65.255 70.055 ;
      RECT 65.155 70.47 65.255 75.01 ;
      RECT 65.155 75.44 65.255 77.735 ;
      RECT 65.155 78.215 65.255 82.755 ;
      RECT 65.155 83.17 65.255 87.71 ;
      RECT 65.155 88.14 65.255 90.435 ;
      RECT 65.155 90.915 65.255 95.455 ;
      RECT 65.155 95.87 65.255 100.41 ;
      RECT 65.155 100.84 65.255 103.135 ;
      RECT 65.155 103.615 65.255 108.155 ;
      RECT 65.155 108.57 65.255 113.11 ;
      RECT 65.155 113.54 65.255 115.835 ;
      RECT 65.155 116.315 65.255 120.855 ;
      RECT 65.155 121.27 65.255 125.81 ;
      RECT 65.155 126.24 65.255 128.535 ;
      RECT 65.155 129.015 65.255 133.555 ;
      RECT 65.155 133.97 65.255 138.51 ;
      RECT 65.155 138.94 65.255 141.235 ;
      RECT 65.155 141.715 65.255 146.255 ;
      RECT 65.155 146.67 65.255 151.21 ;
      RECT 65.155 151.64 65.255 153.935 ;
      RECT 65.155 154.415 65.255 158.955 ;
      RECT 65.155 159.37 65.255 163.91 ;
      RECT 65.155 164.34 65.255 166.635 ;
      RECT 65.155 167.115 65.255 171.655 ;
      RECT 65.155 172.07 65.255 176.61 ;
      RECT 65.155 177.04 65.255 179.335 ;
      RECT 65.155 221.24 65.255 225.78 ;
      RECT 65.155 226.195 65.255 230.735 ;
      RECT 65.155 231.165 65.255 233.46 ;
      RECT 65.155 233.94 65.255 238.48 ;
      RECT 65.155 238.895 65.255 243.435 ;
      RECT 65.155 243.865 65.255 246.16 ;
      RECT 65.155 246.64 65.255 251.18 ;
      RECT 65.155 251.595 65.255 256.135 ;
      RECT 65.155 256.565 65.255 258.86 ;
      RECT 65.155 259.34 65.255 263.88 ;
      RECT 65.155 264.295 65.255 268.835 ;
      RECT 65.155 269.265 65.255 271.56 ;
      RECT 65.155 272.04 65.255 276.58 ;
      RECT 65.155 276.995 65.255 281.535 ;
      RECT 65.155 281.965 65.255 284.26 ;
      RECT 65.155 284.74 65.255 289.28 ;
      RECT 65.155 289.695 65.255 294.235 ;
      RECT 65.155 294.665 65.255 296.96 ;
      RECT 65.155 297.44 65.255 301.98 ;
      RECT 65.155 302.395 65.255 306.935 ;
      RECT 65.155 307.365 65.255 309.66 ;
      RECT 65.155 310.14 65.255 314.68 ;
      RECT 65.155 315.095 65.255 319.635 ;
      RECT 65.155 320.065 65.255 322.36 ;
      RECT 65.155 322.84 65.255 327.38 ;
      RECT 65.155 327.795 65.255 332.335 ;
      RECT 65.155 332.765 65.255 335.06 ;
      RECT 65.155 335.54 65.255 340.08 ;
      RECT 65.155 340.495 65.255 345.035 ;
      RECT 65.155 345.465 65.255 347.76 ;
      RECT 65.155 348.24 65.255 352.78 ;
      RECT 65.155 353.195 65.255 357.735 ;
      RECT 65.155 358.165 65.255 360.46 ;
      RECT 65.155 360.94 65.255 365.48 ;
      RECT 65.155 365.895 65.255 370.435 ;
      RECT 65.155 370.865 65.255 373.16 ;
      RECT 65.155 373.64 65.255 378.18 ;
      RECT 65.155 378.595 65.255 383.135 ;
      RECT 65.155 383.565 65.255 385.86 ;
      RECT 65.155 386.34 65.255 390.88 ;
      RECT 65.155 391.295 65.255 395.835 ;
    LAYER M7 SPACING 0.05 ;
      RECT 177.955 0 240 400 ;
      RECT 0 0 62.045 400 ;
      RECT 118.765 0 121.235 398.28 ;
      RECT 164.505 0 175.035 395.955 ;
      RECT 151.055 0 161.585 395.955 ;
      RECT 137.605 0 148.135 395.955 ;
      RECT 124.155 0 134.685 395.955 ;
      RECT 105.315 0 115.845 395.955 ;
      RECT 91.865 0 102.395 395.955 ;
      RECT 78.415 0 88.945 395.955 ;
      RECT 64.965 0 75.495 395.955 ;
      RECT 0 0 240 1.67 ;
  END
END hb_macro_bnk_230m_4s_sample

END LIBRARY
